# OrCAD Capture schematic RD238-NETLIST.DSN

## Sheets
1 16: size A3
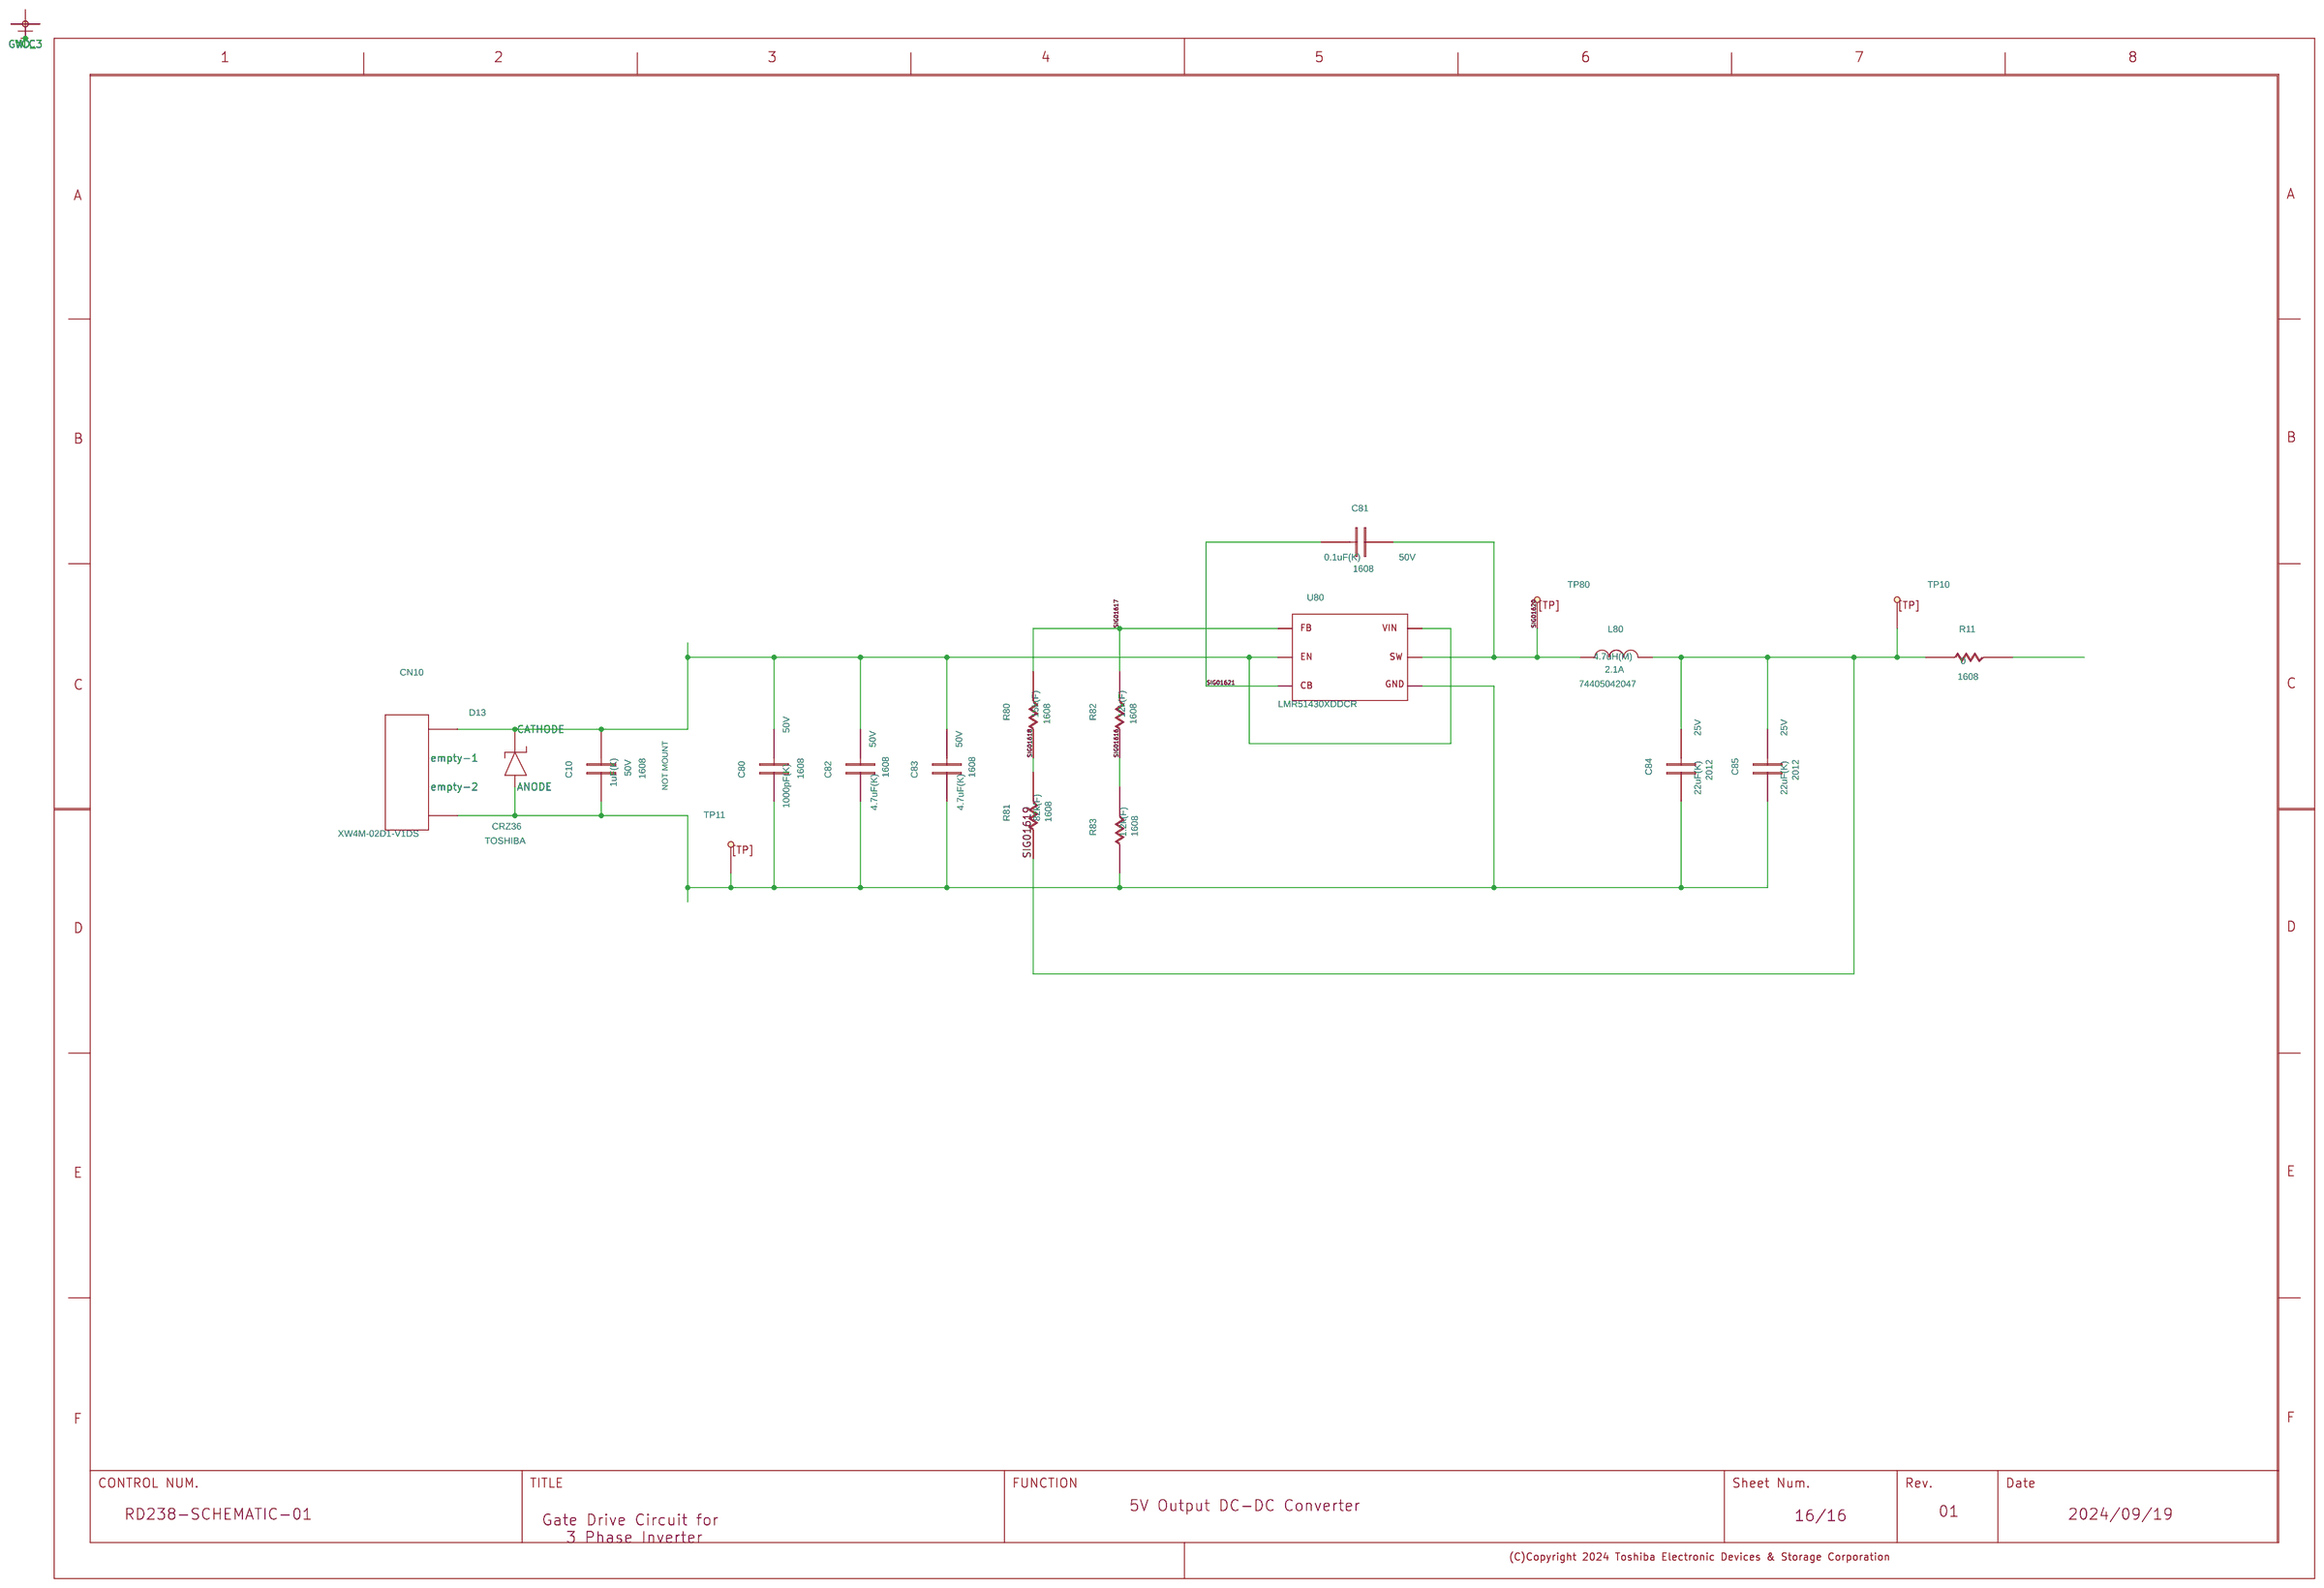
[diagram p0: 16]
2 15: size A3
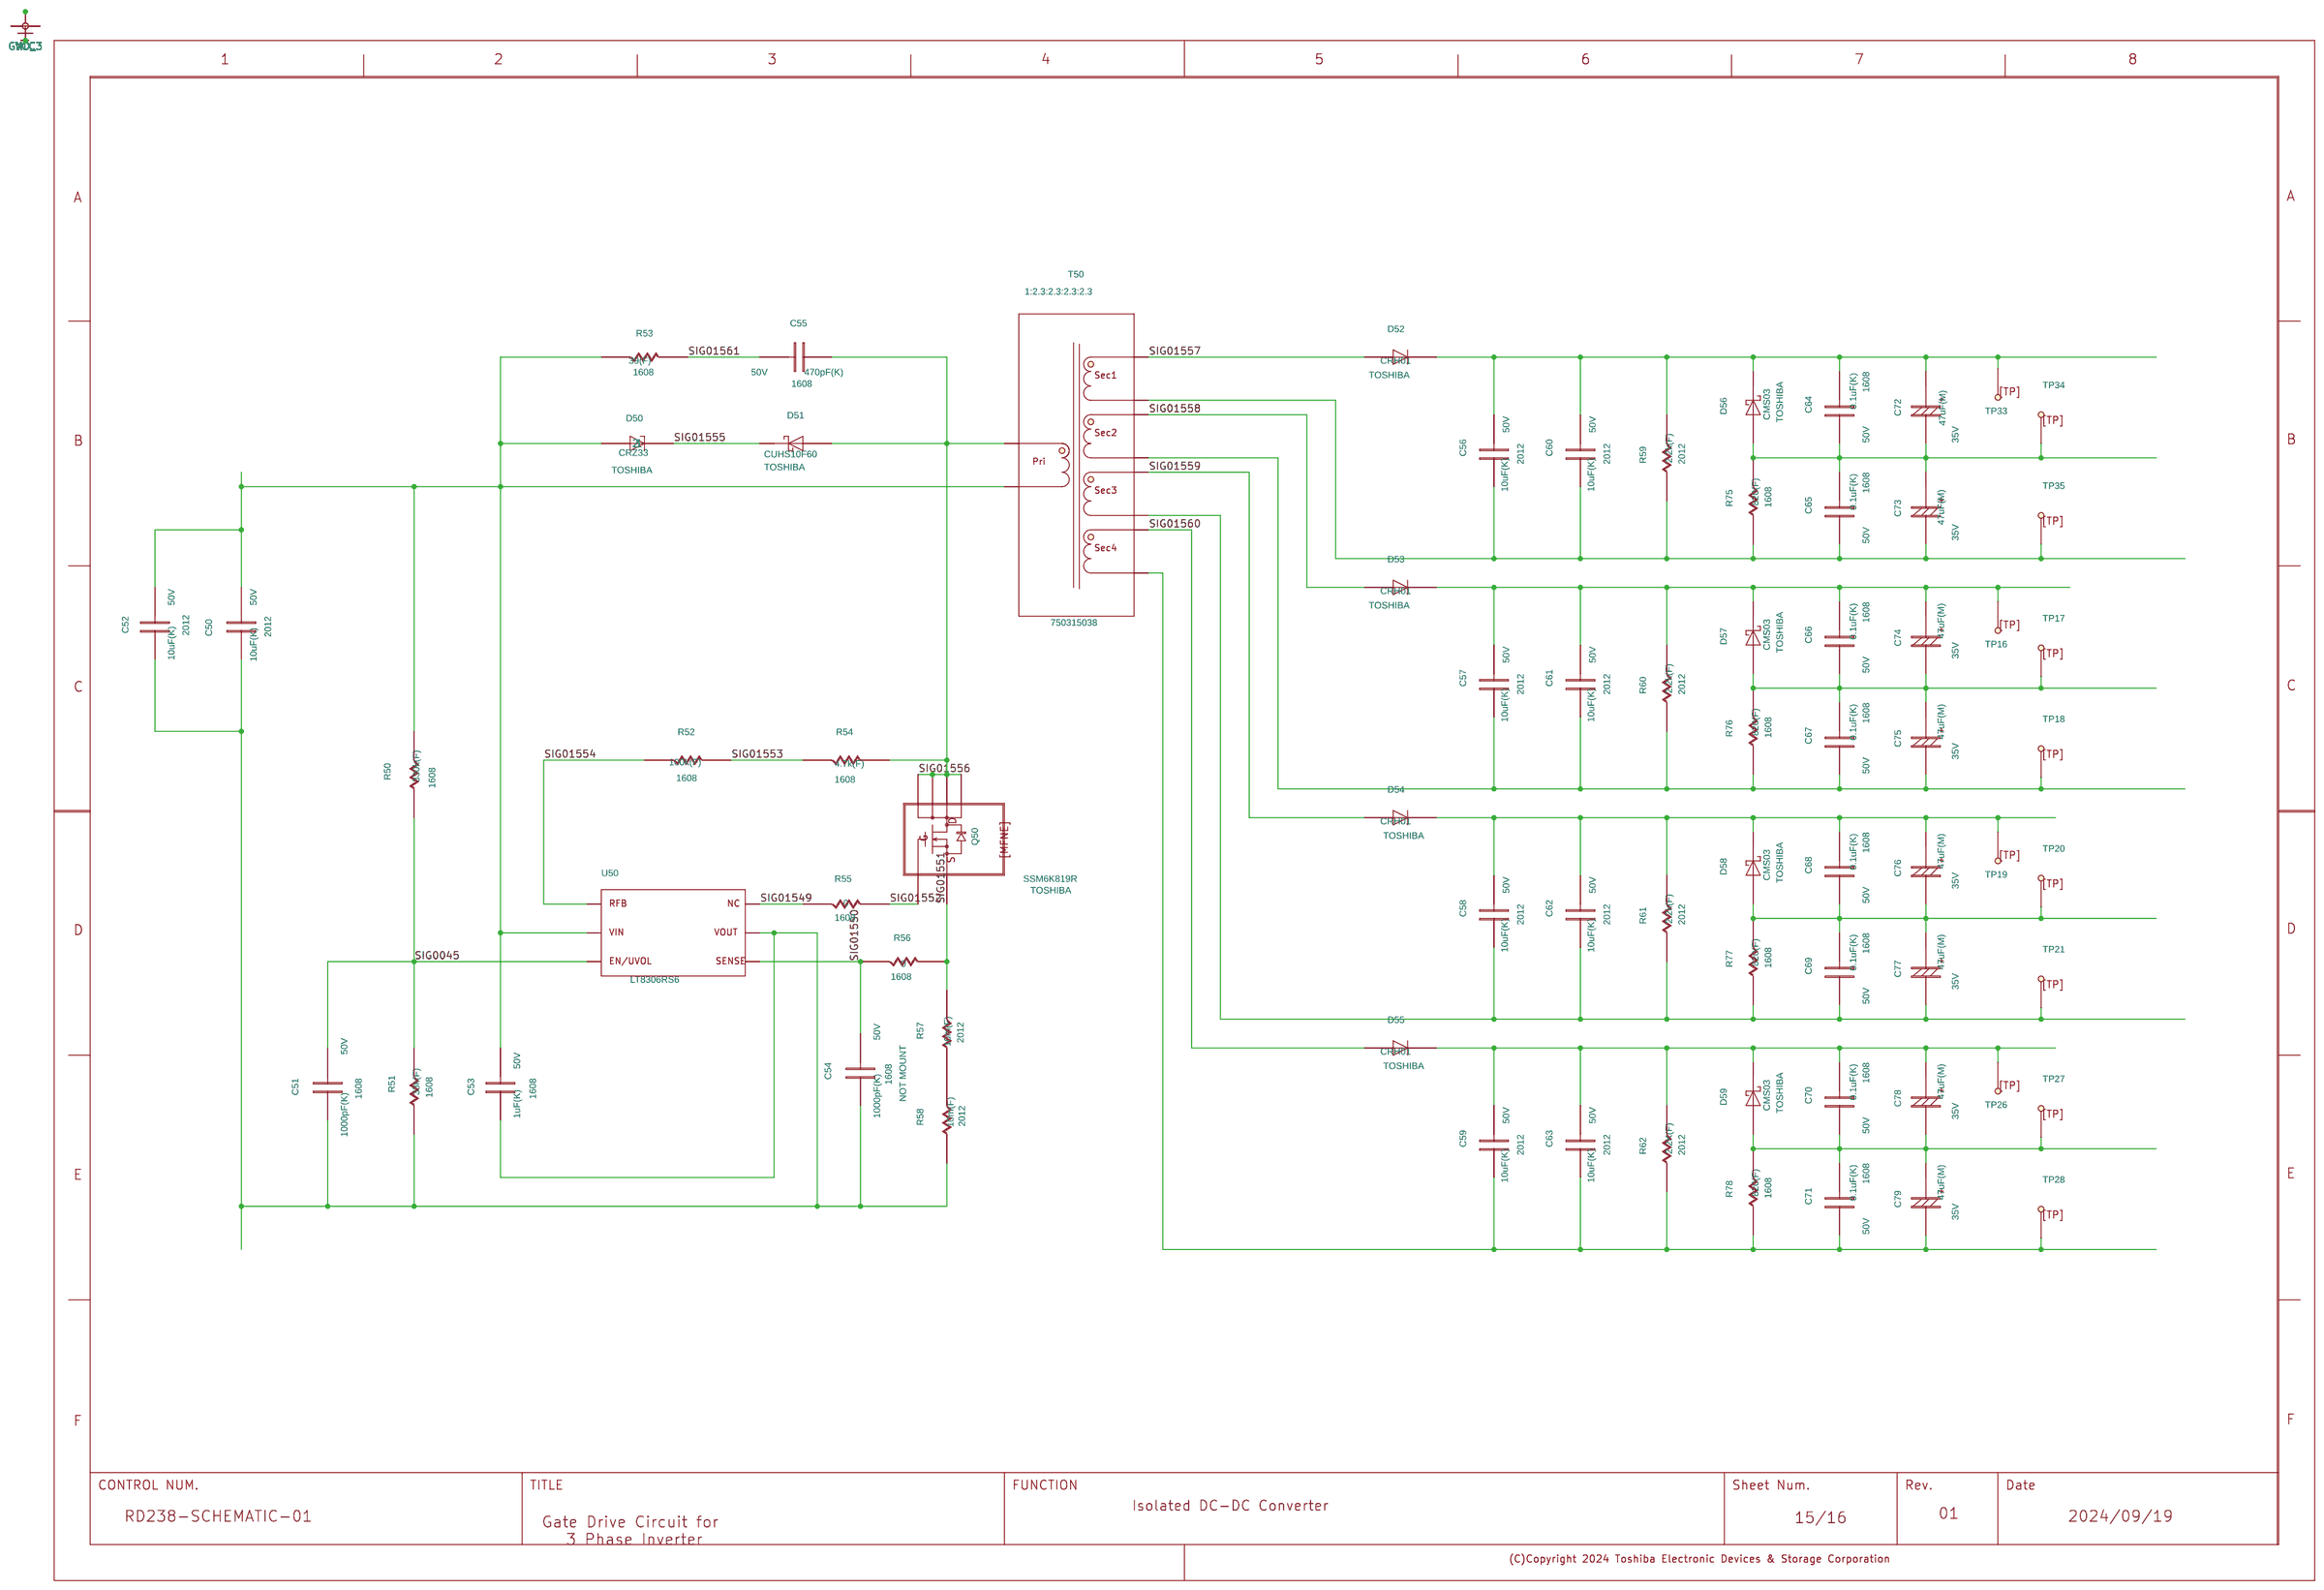
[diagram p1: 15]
3 14: size A3
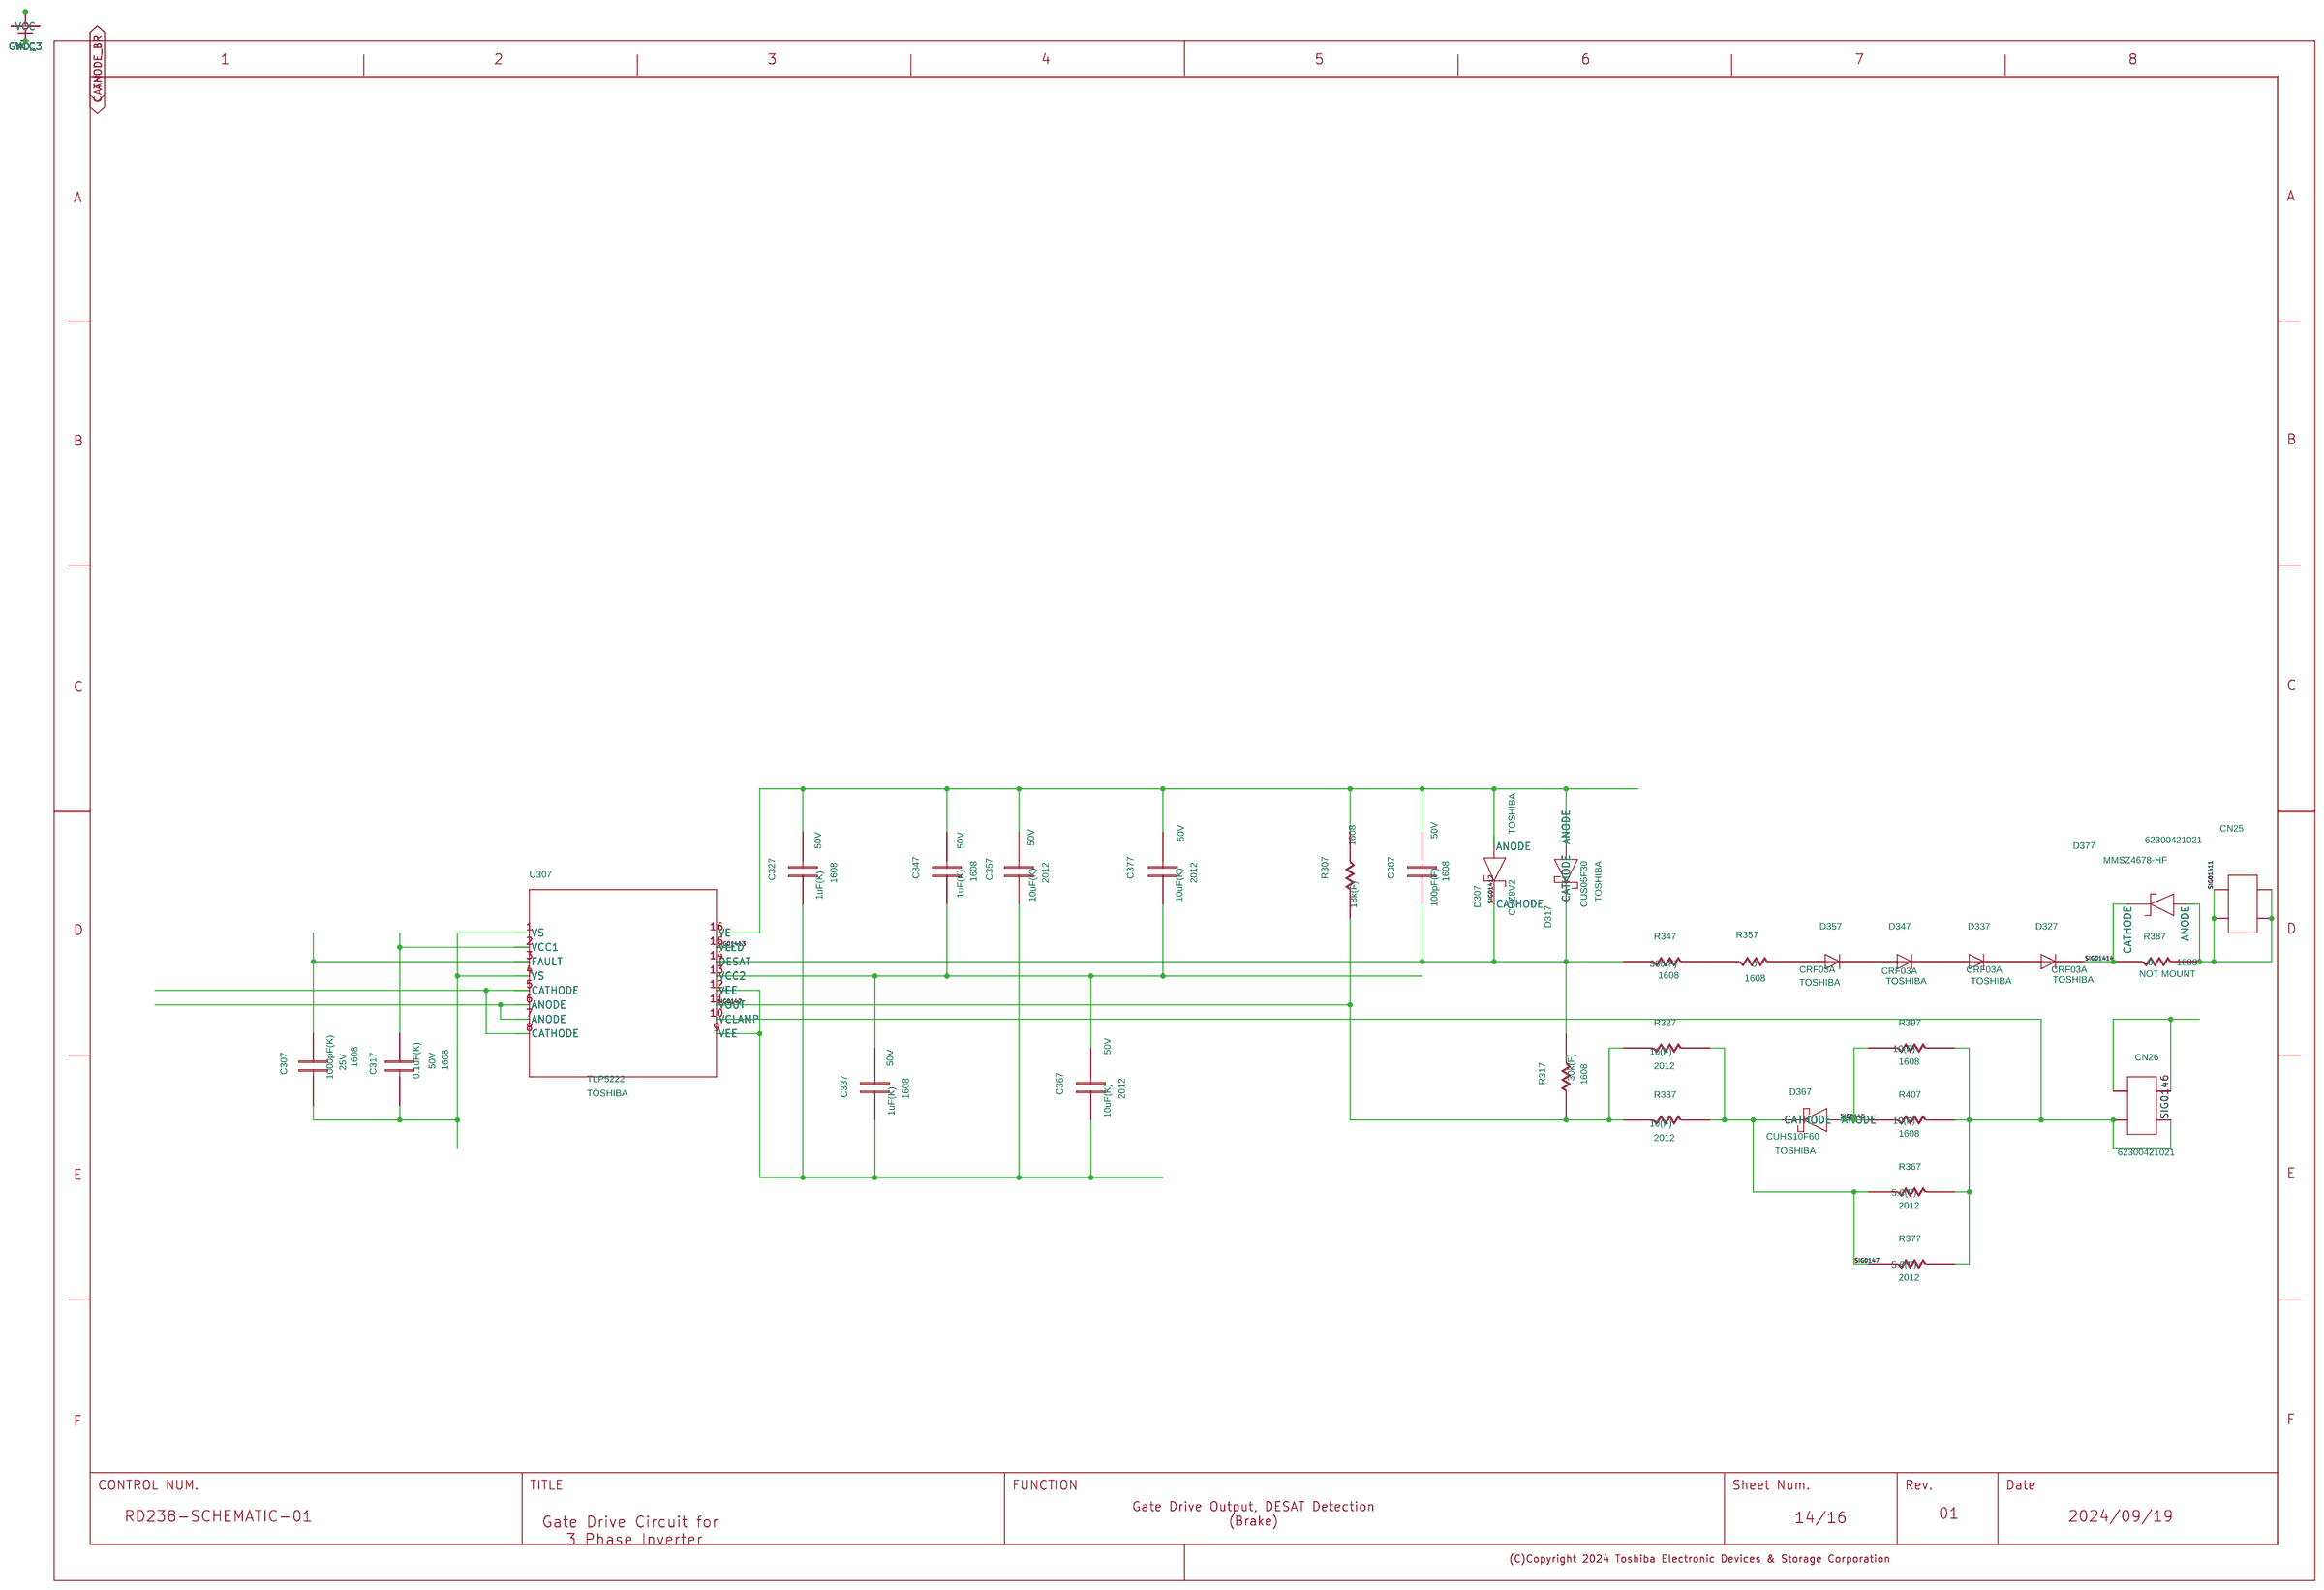
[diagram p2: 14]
4 13: size A3
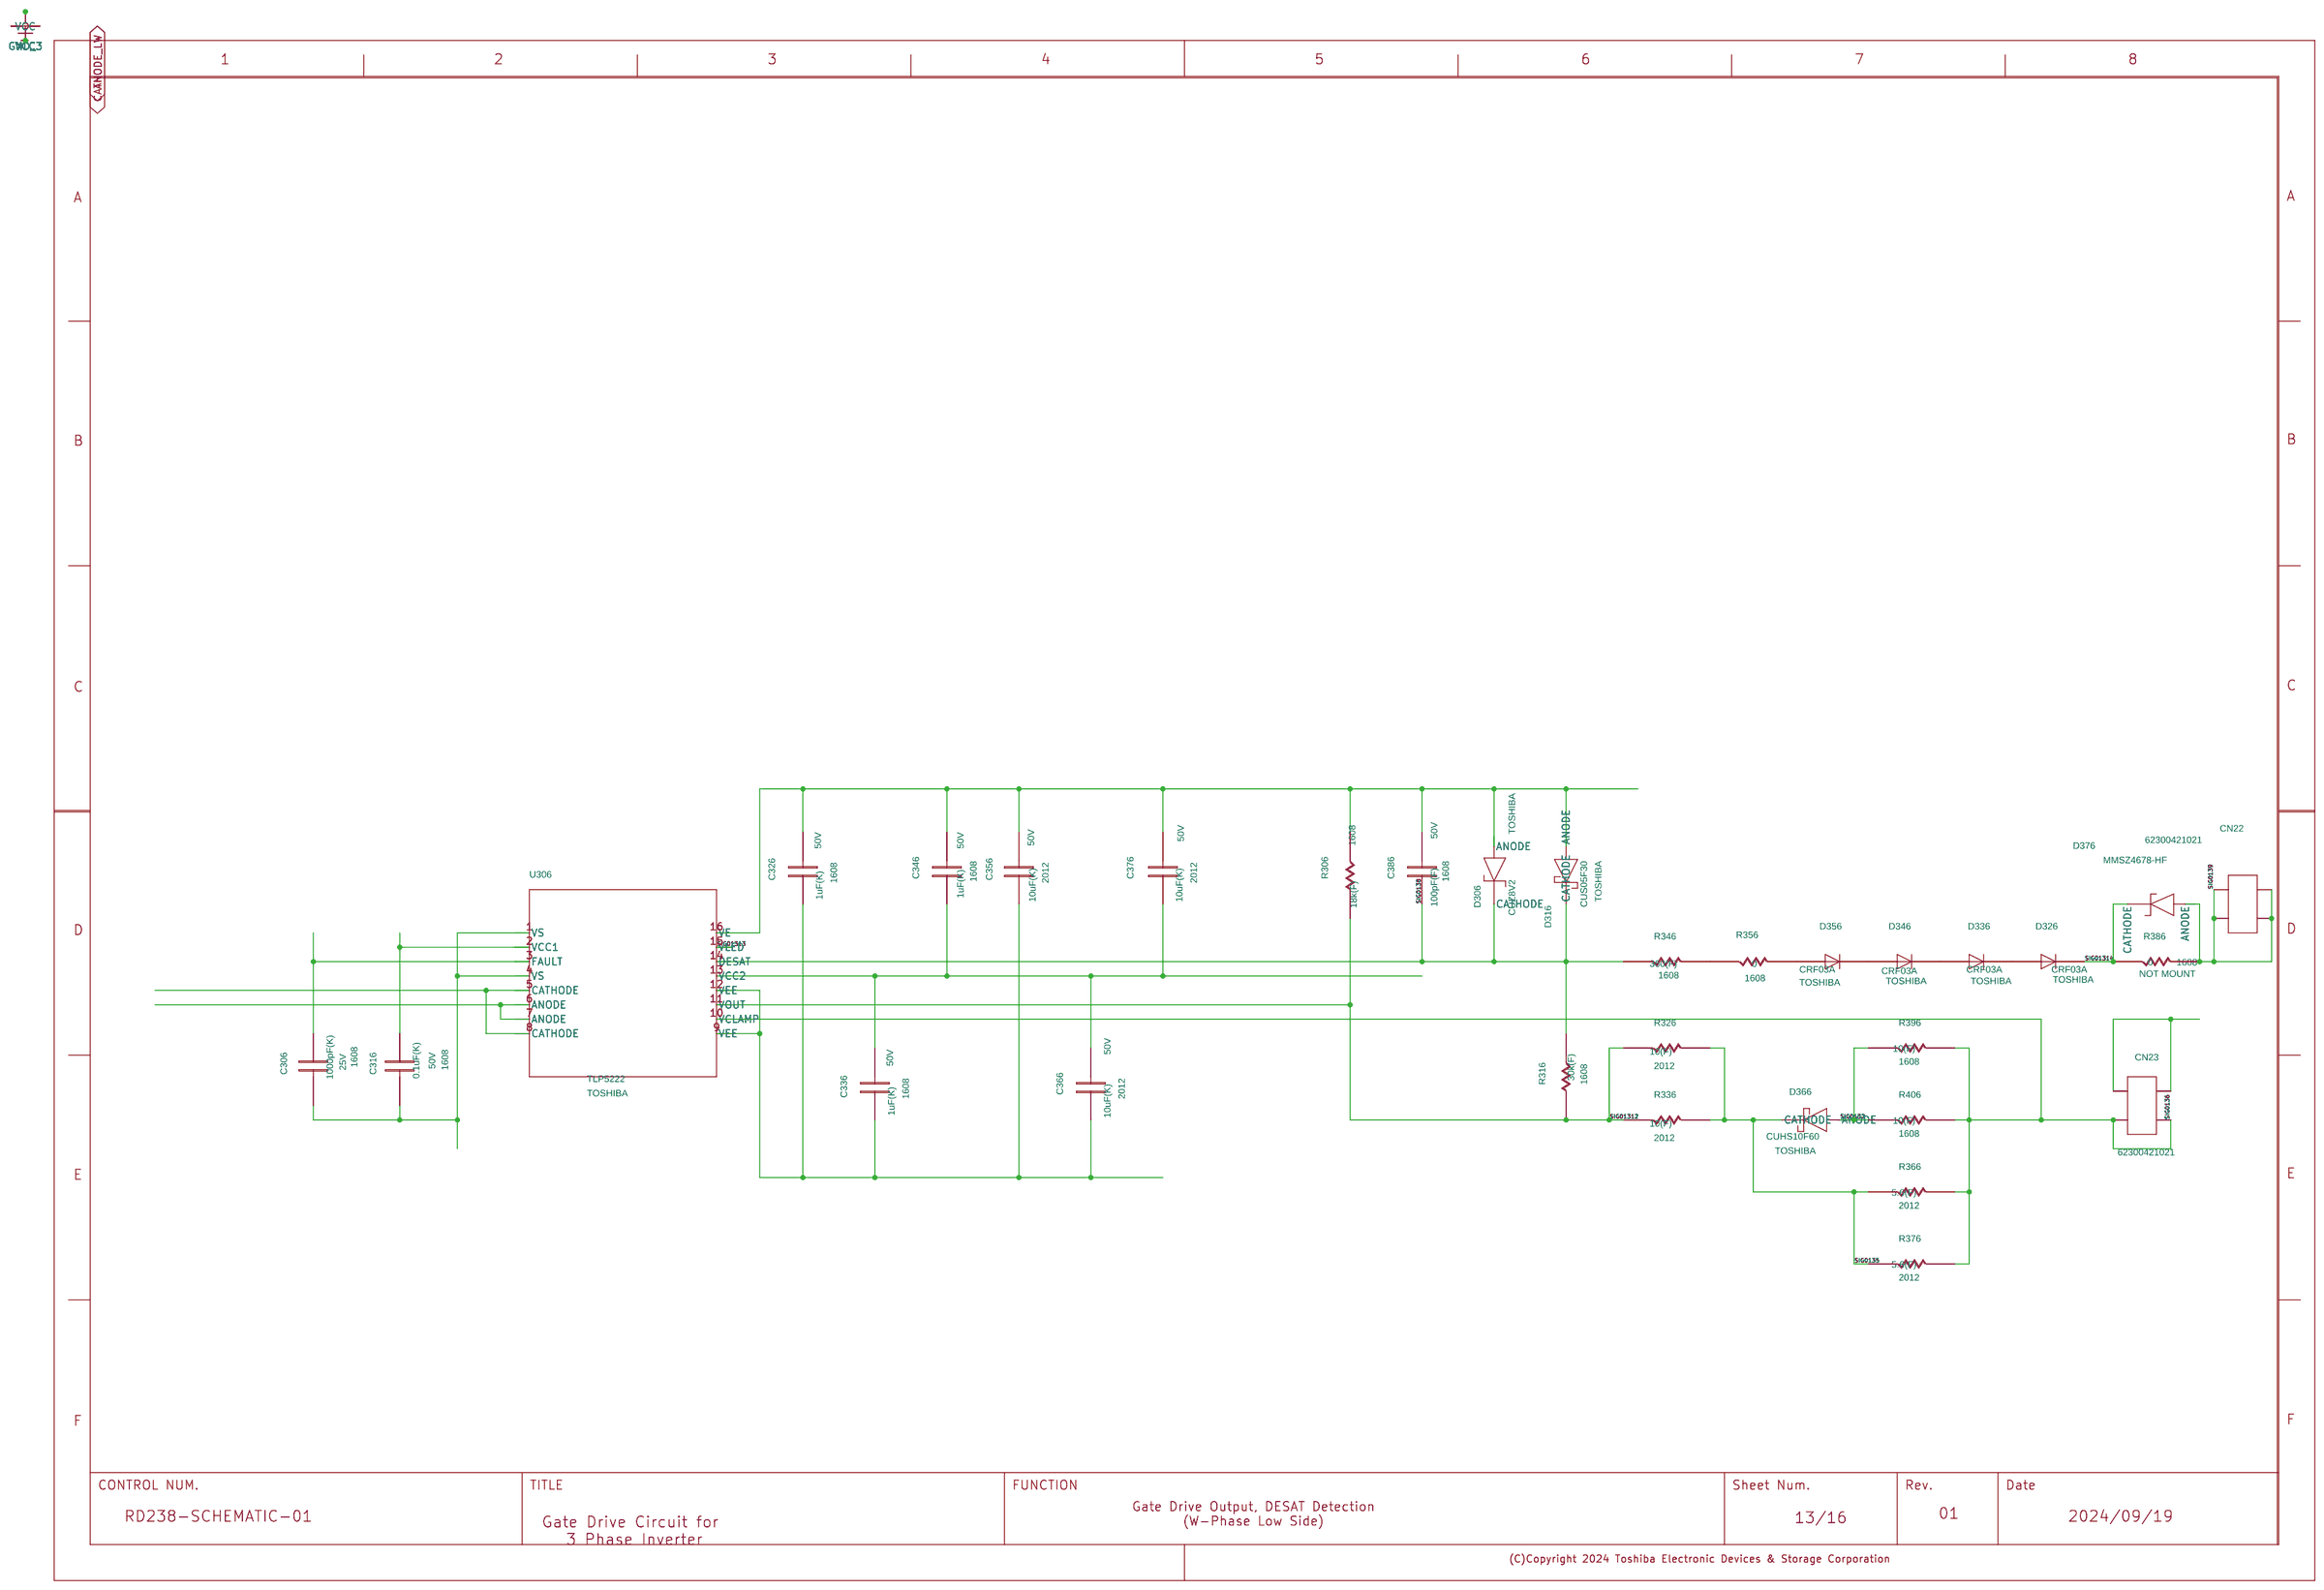
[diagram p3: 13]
5 12: size A3
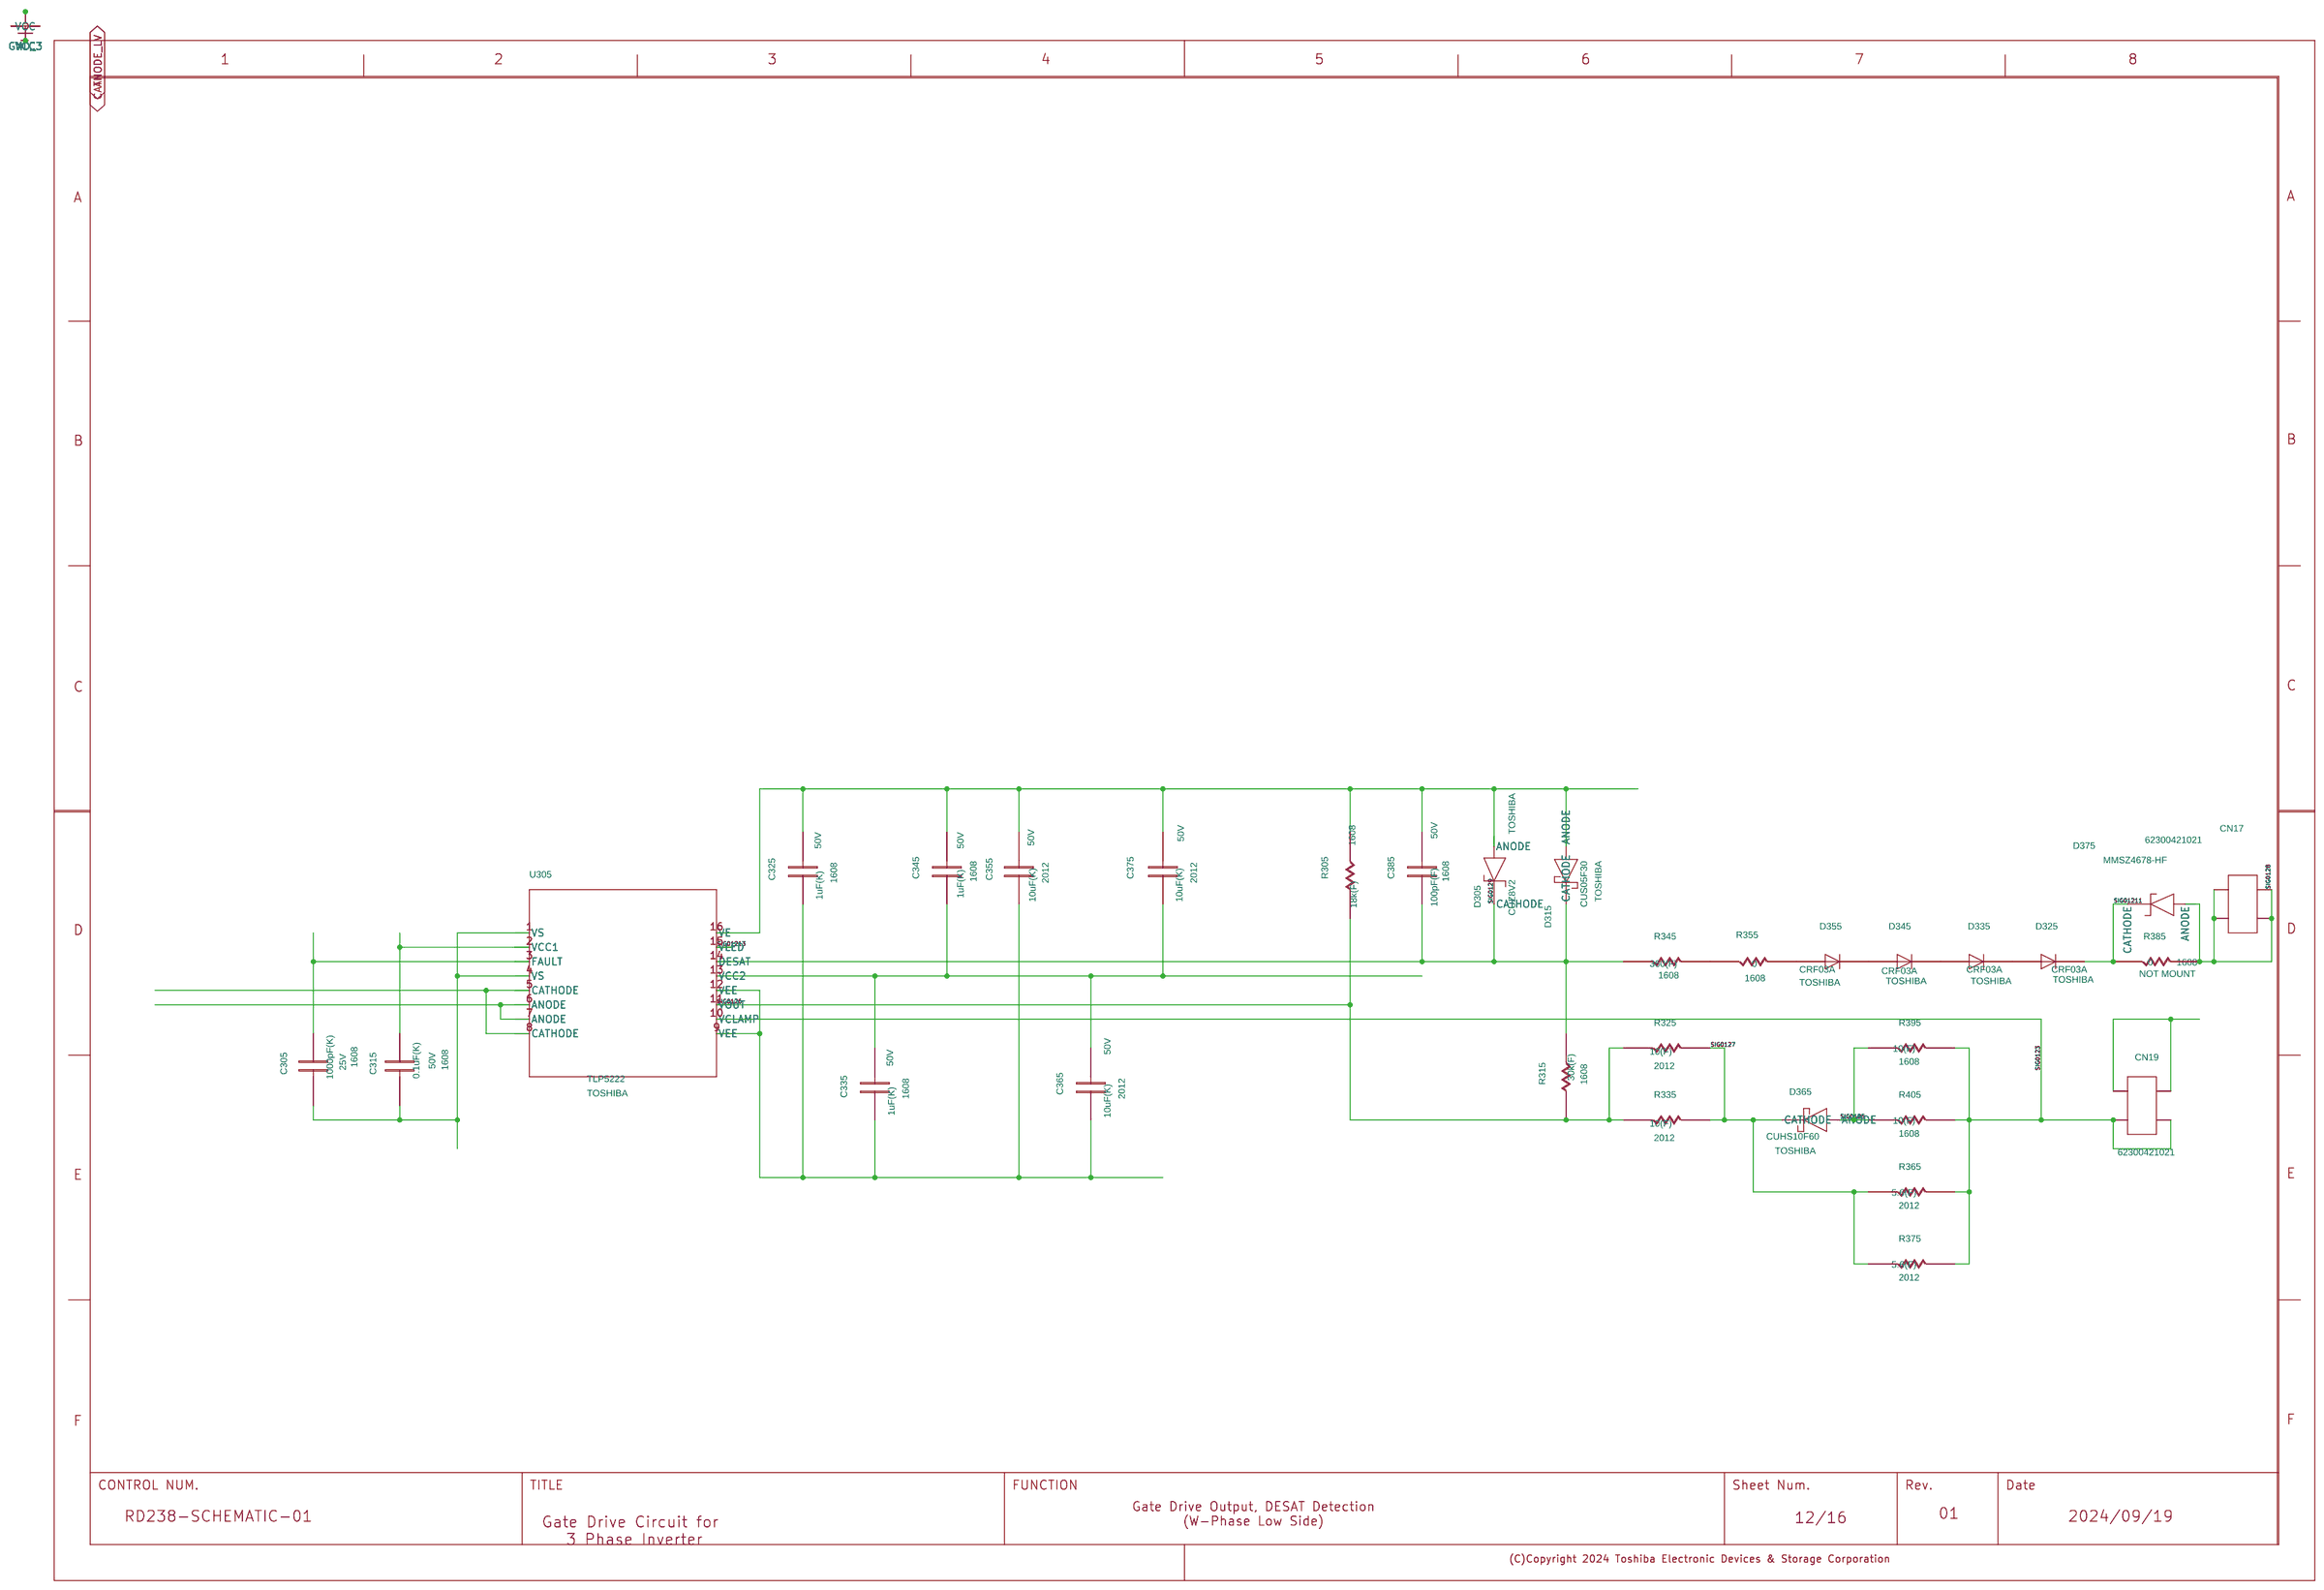
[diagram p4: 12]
6 11: size A3
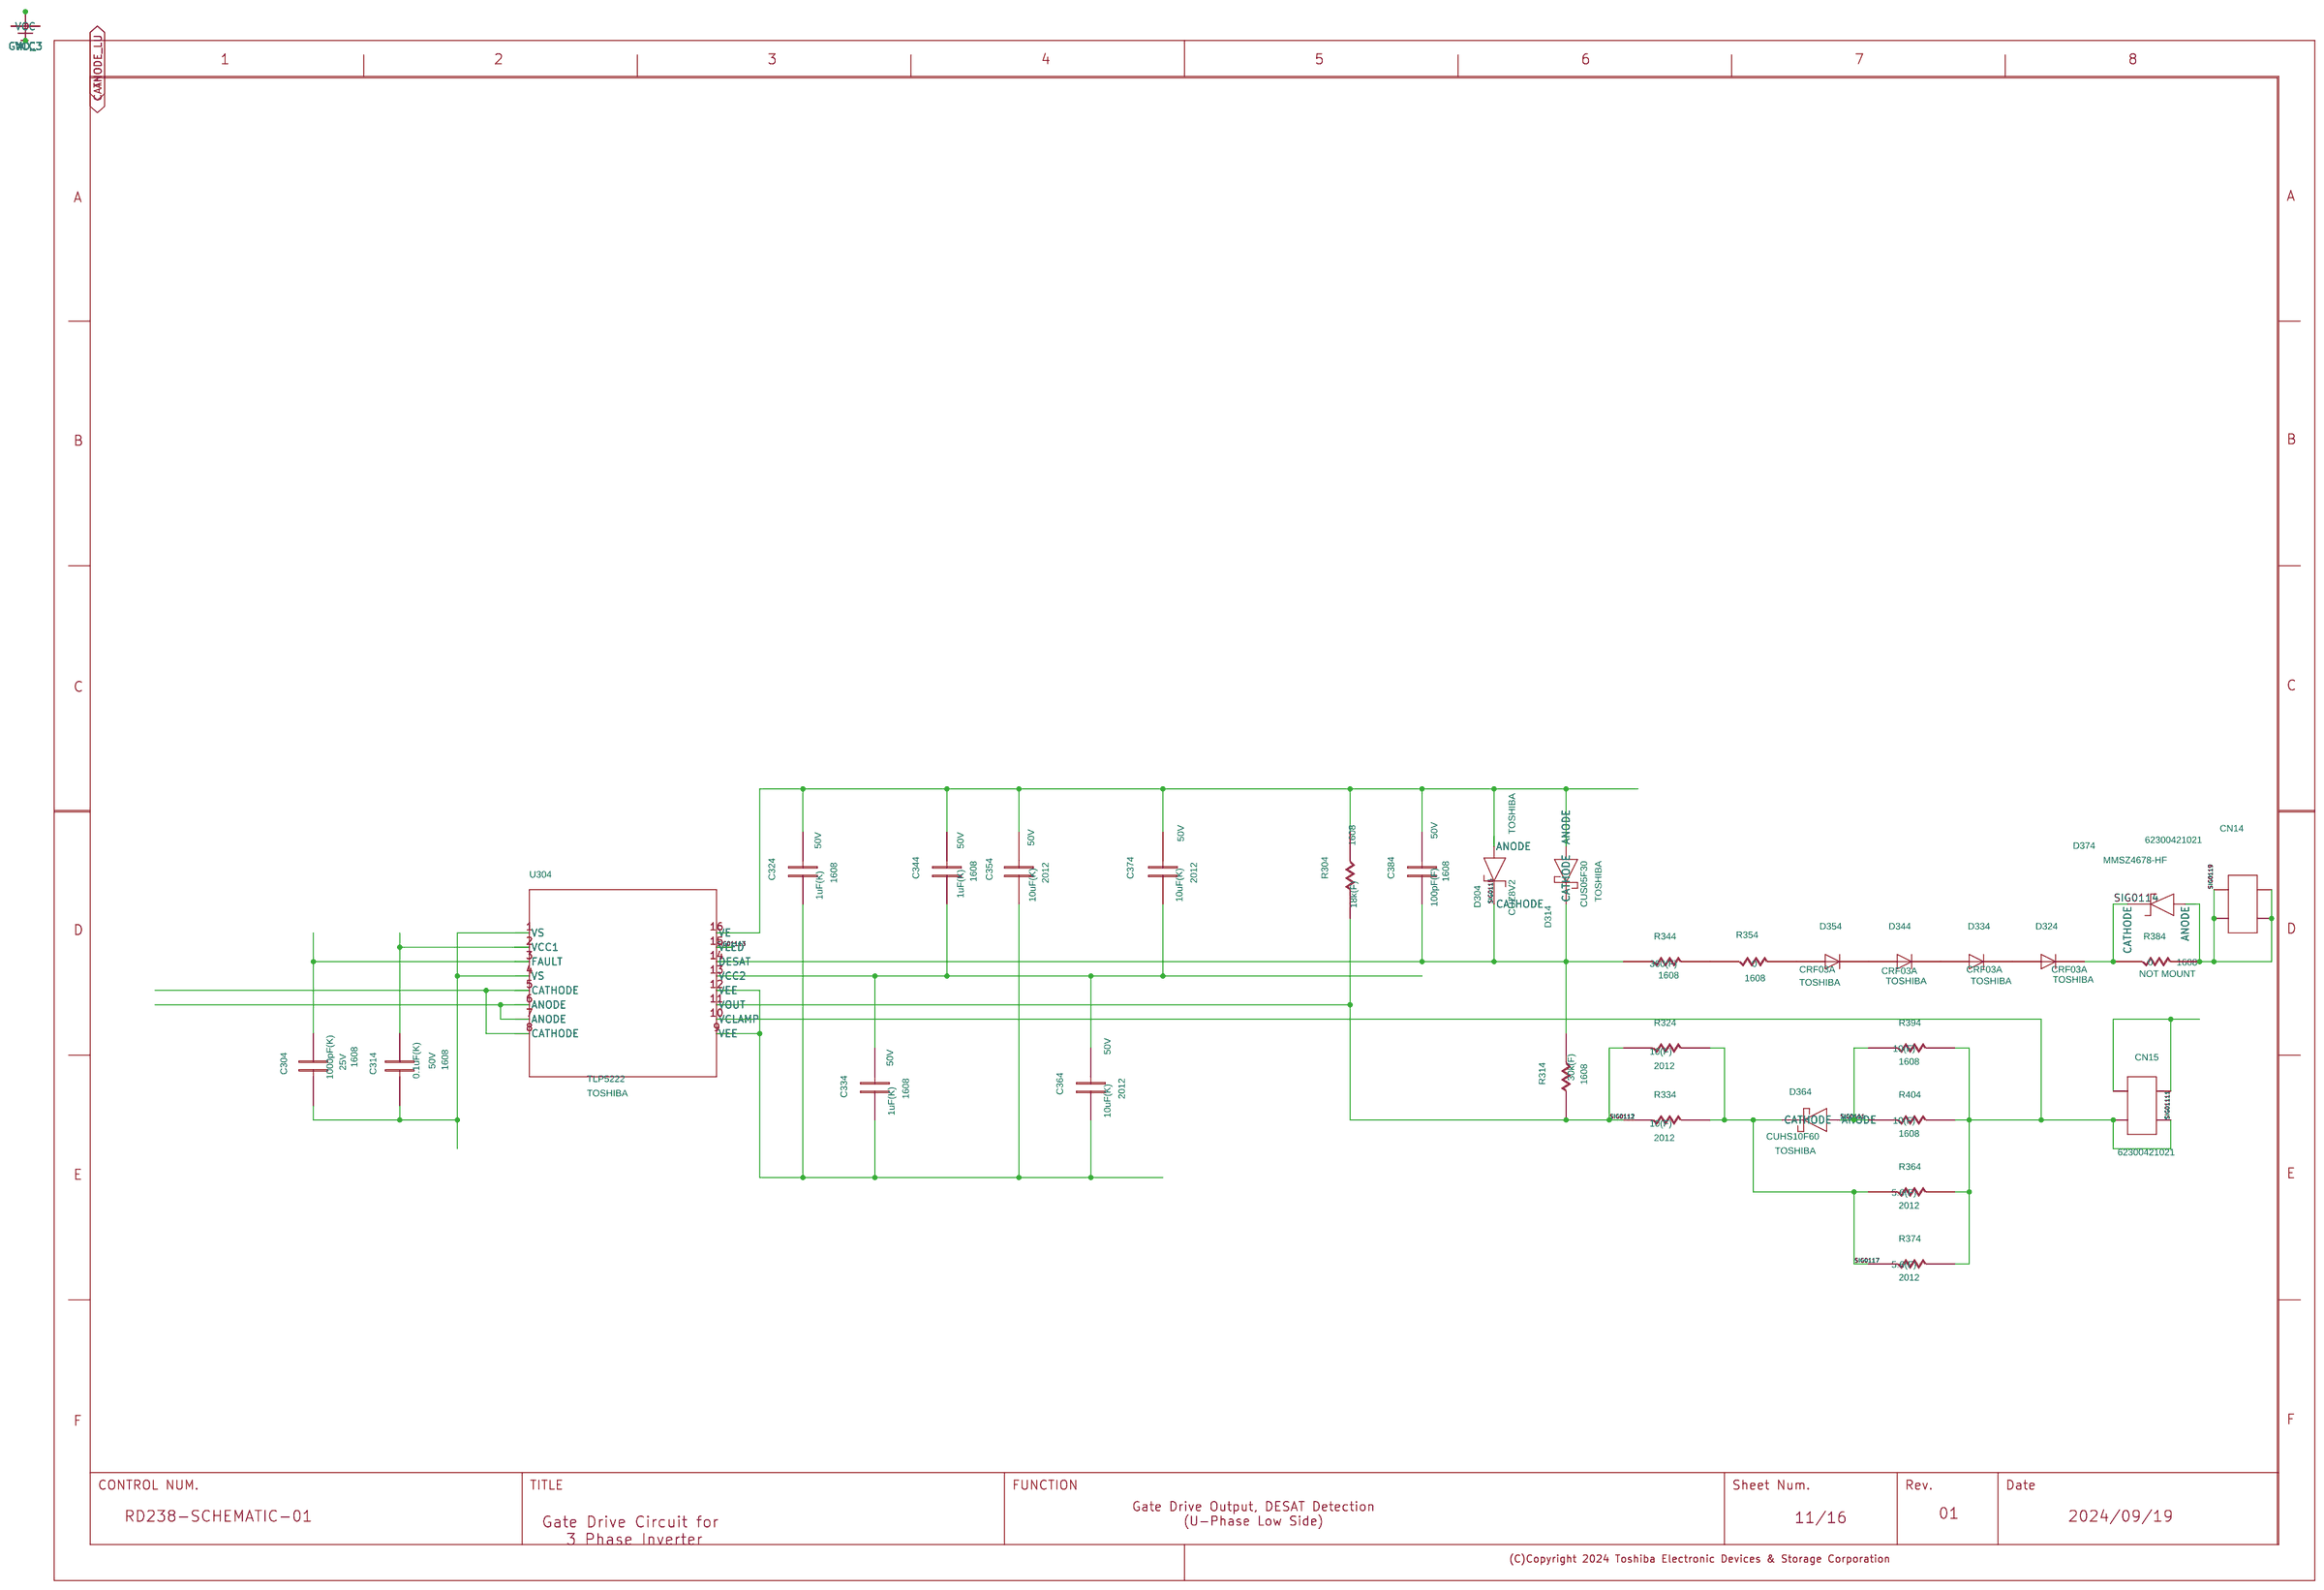
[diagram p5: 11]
7 10: size A3
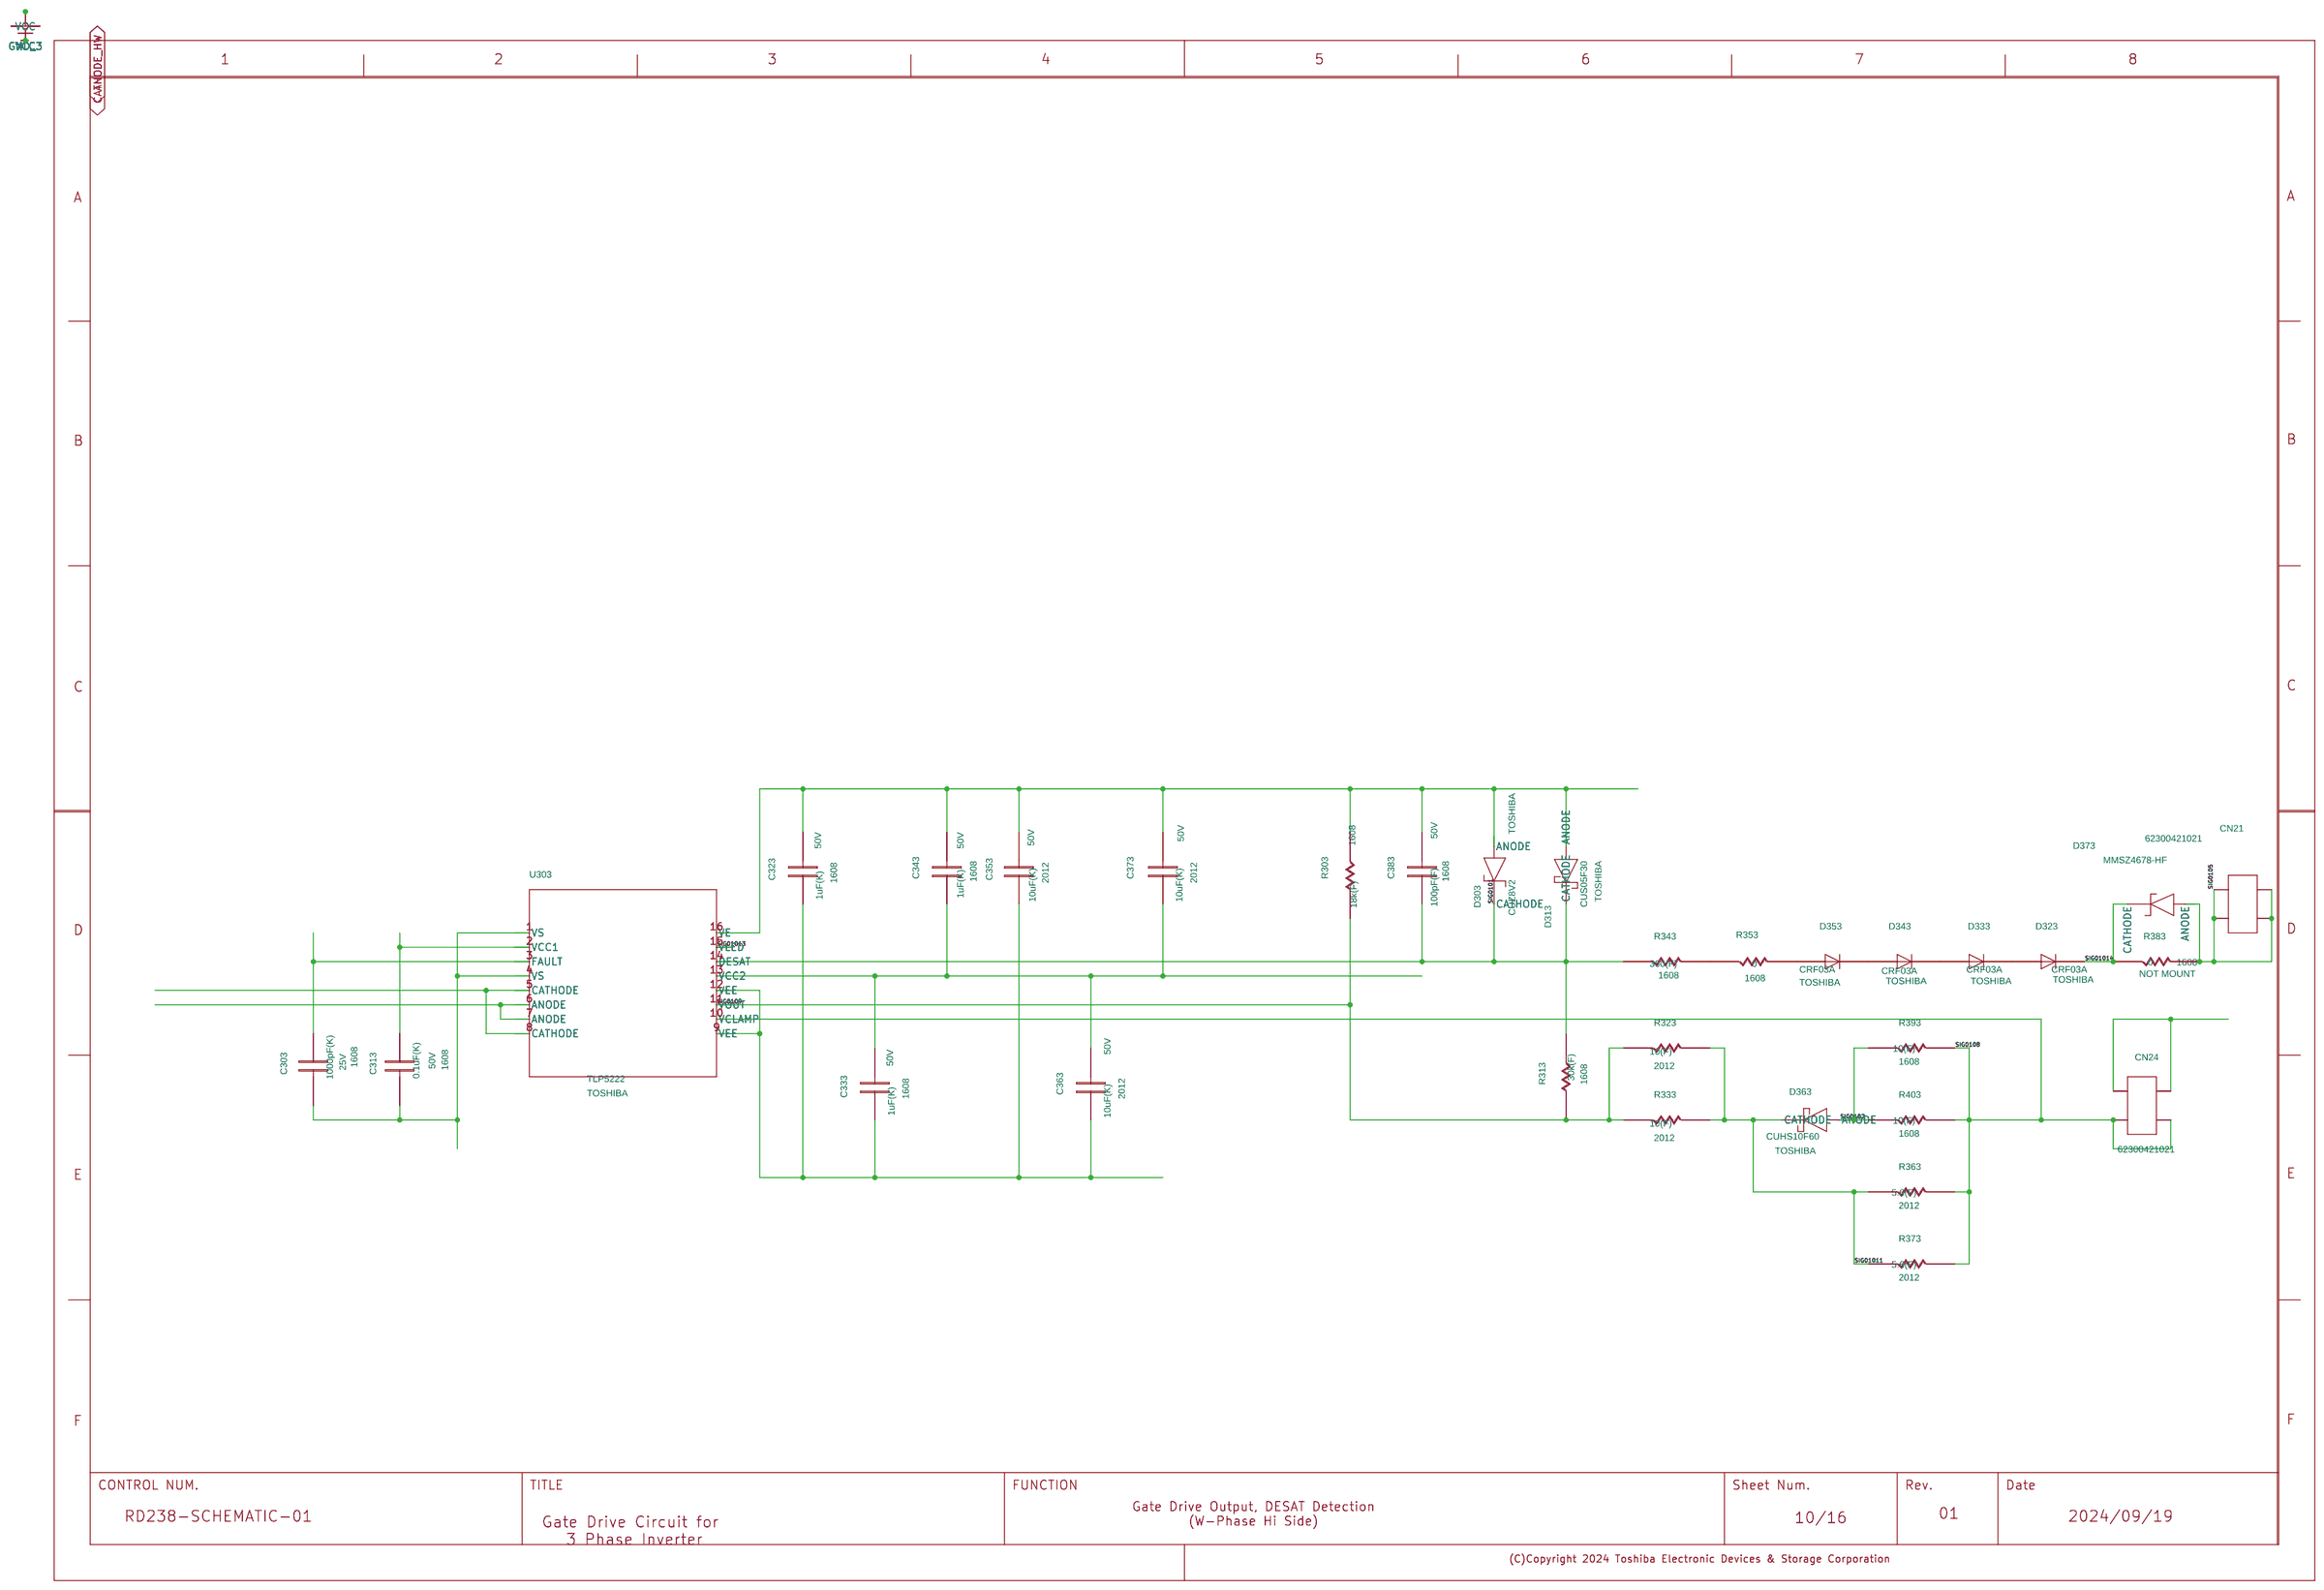
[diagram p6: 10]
8 9: size A3
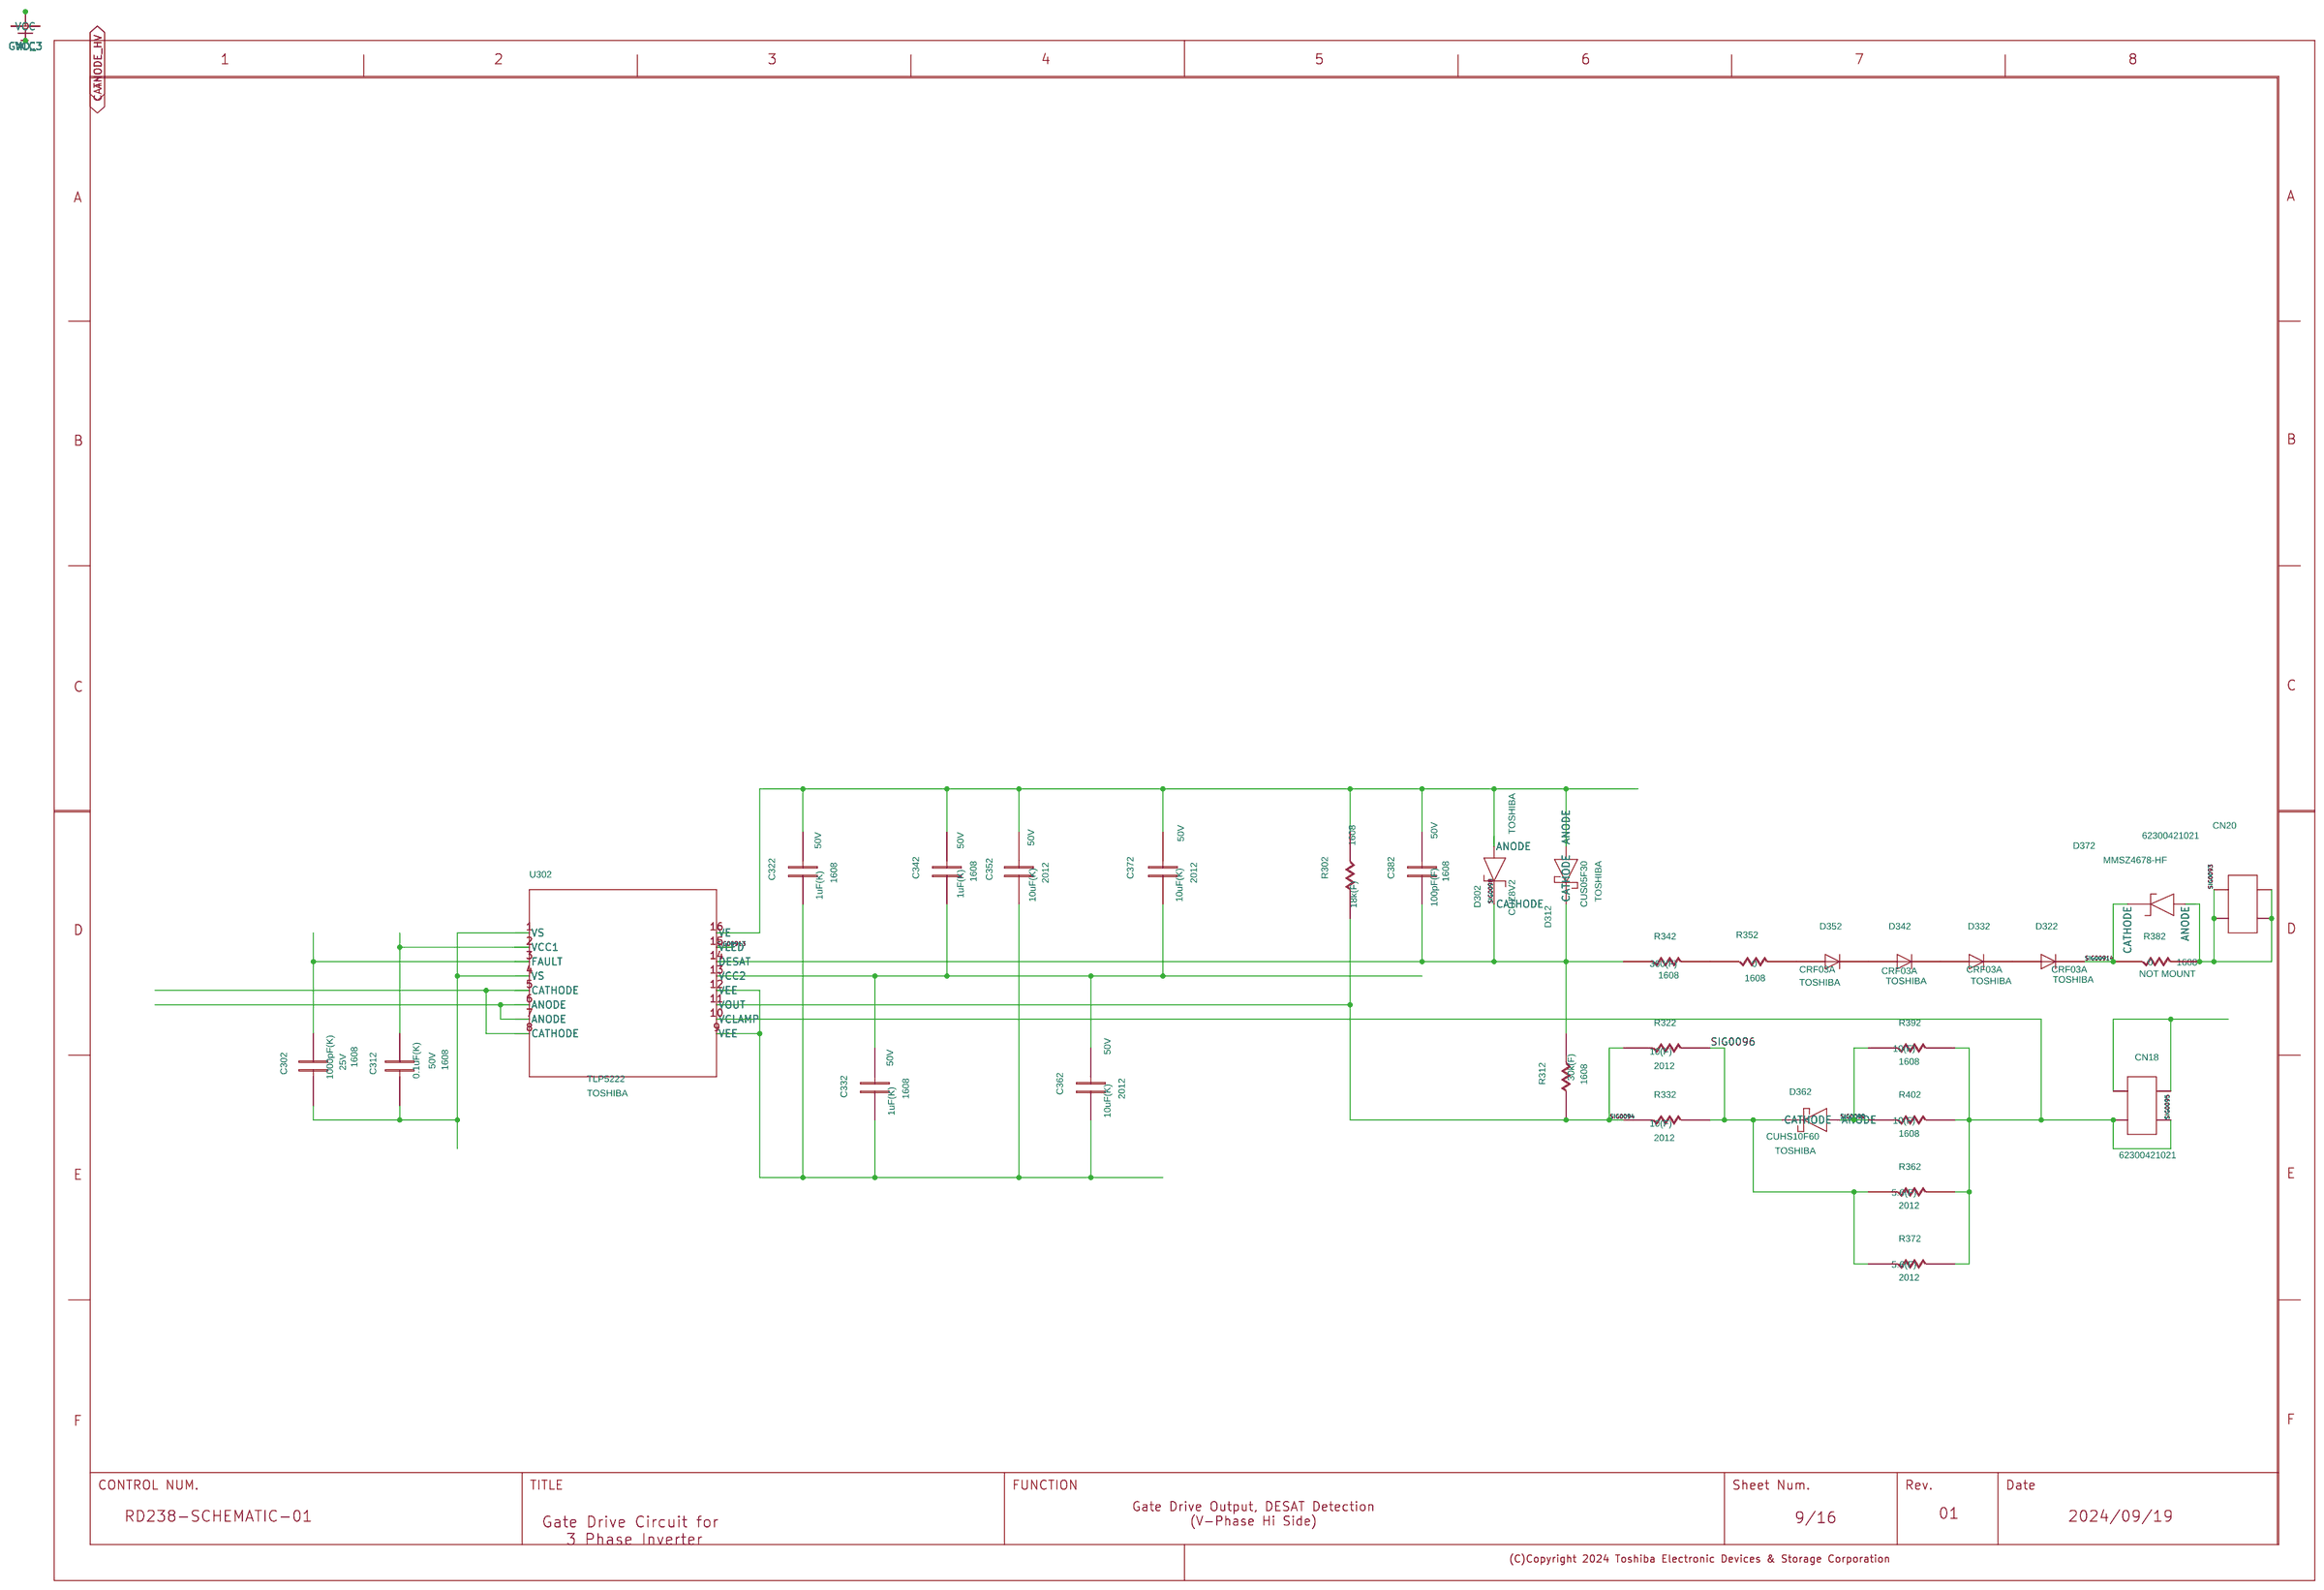
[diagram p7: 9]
9 8: size A3
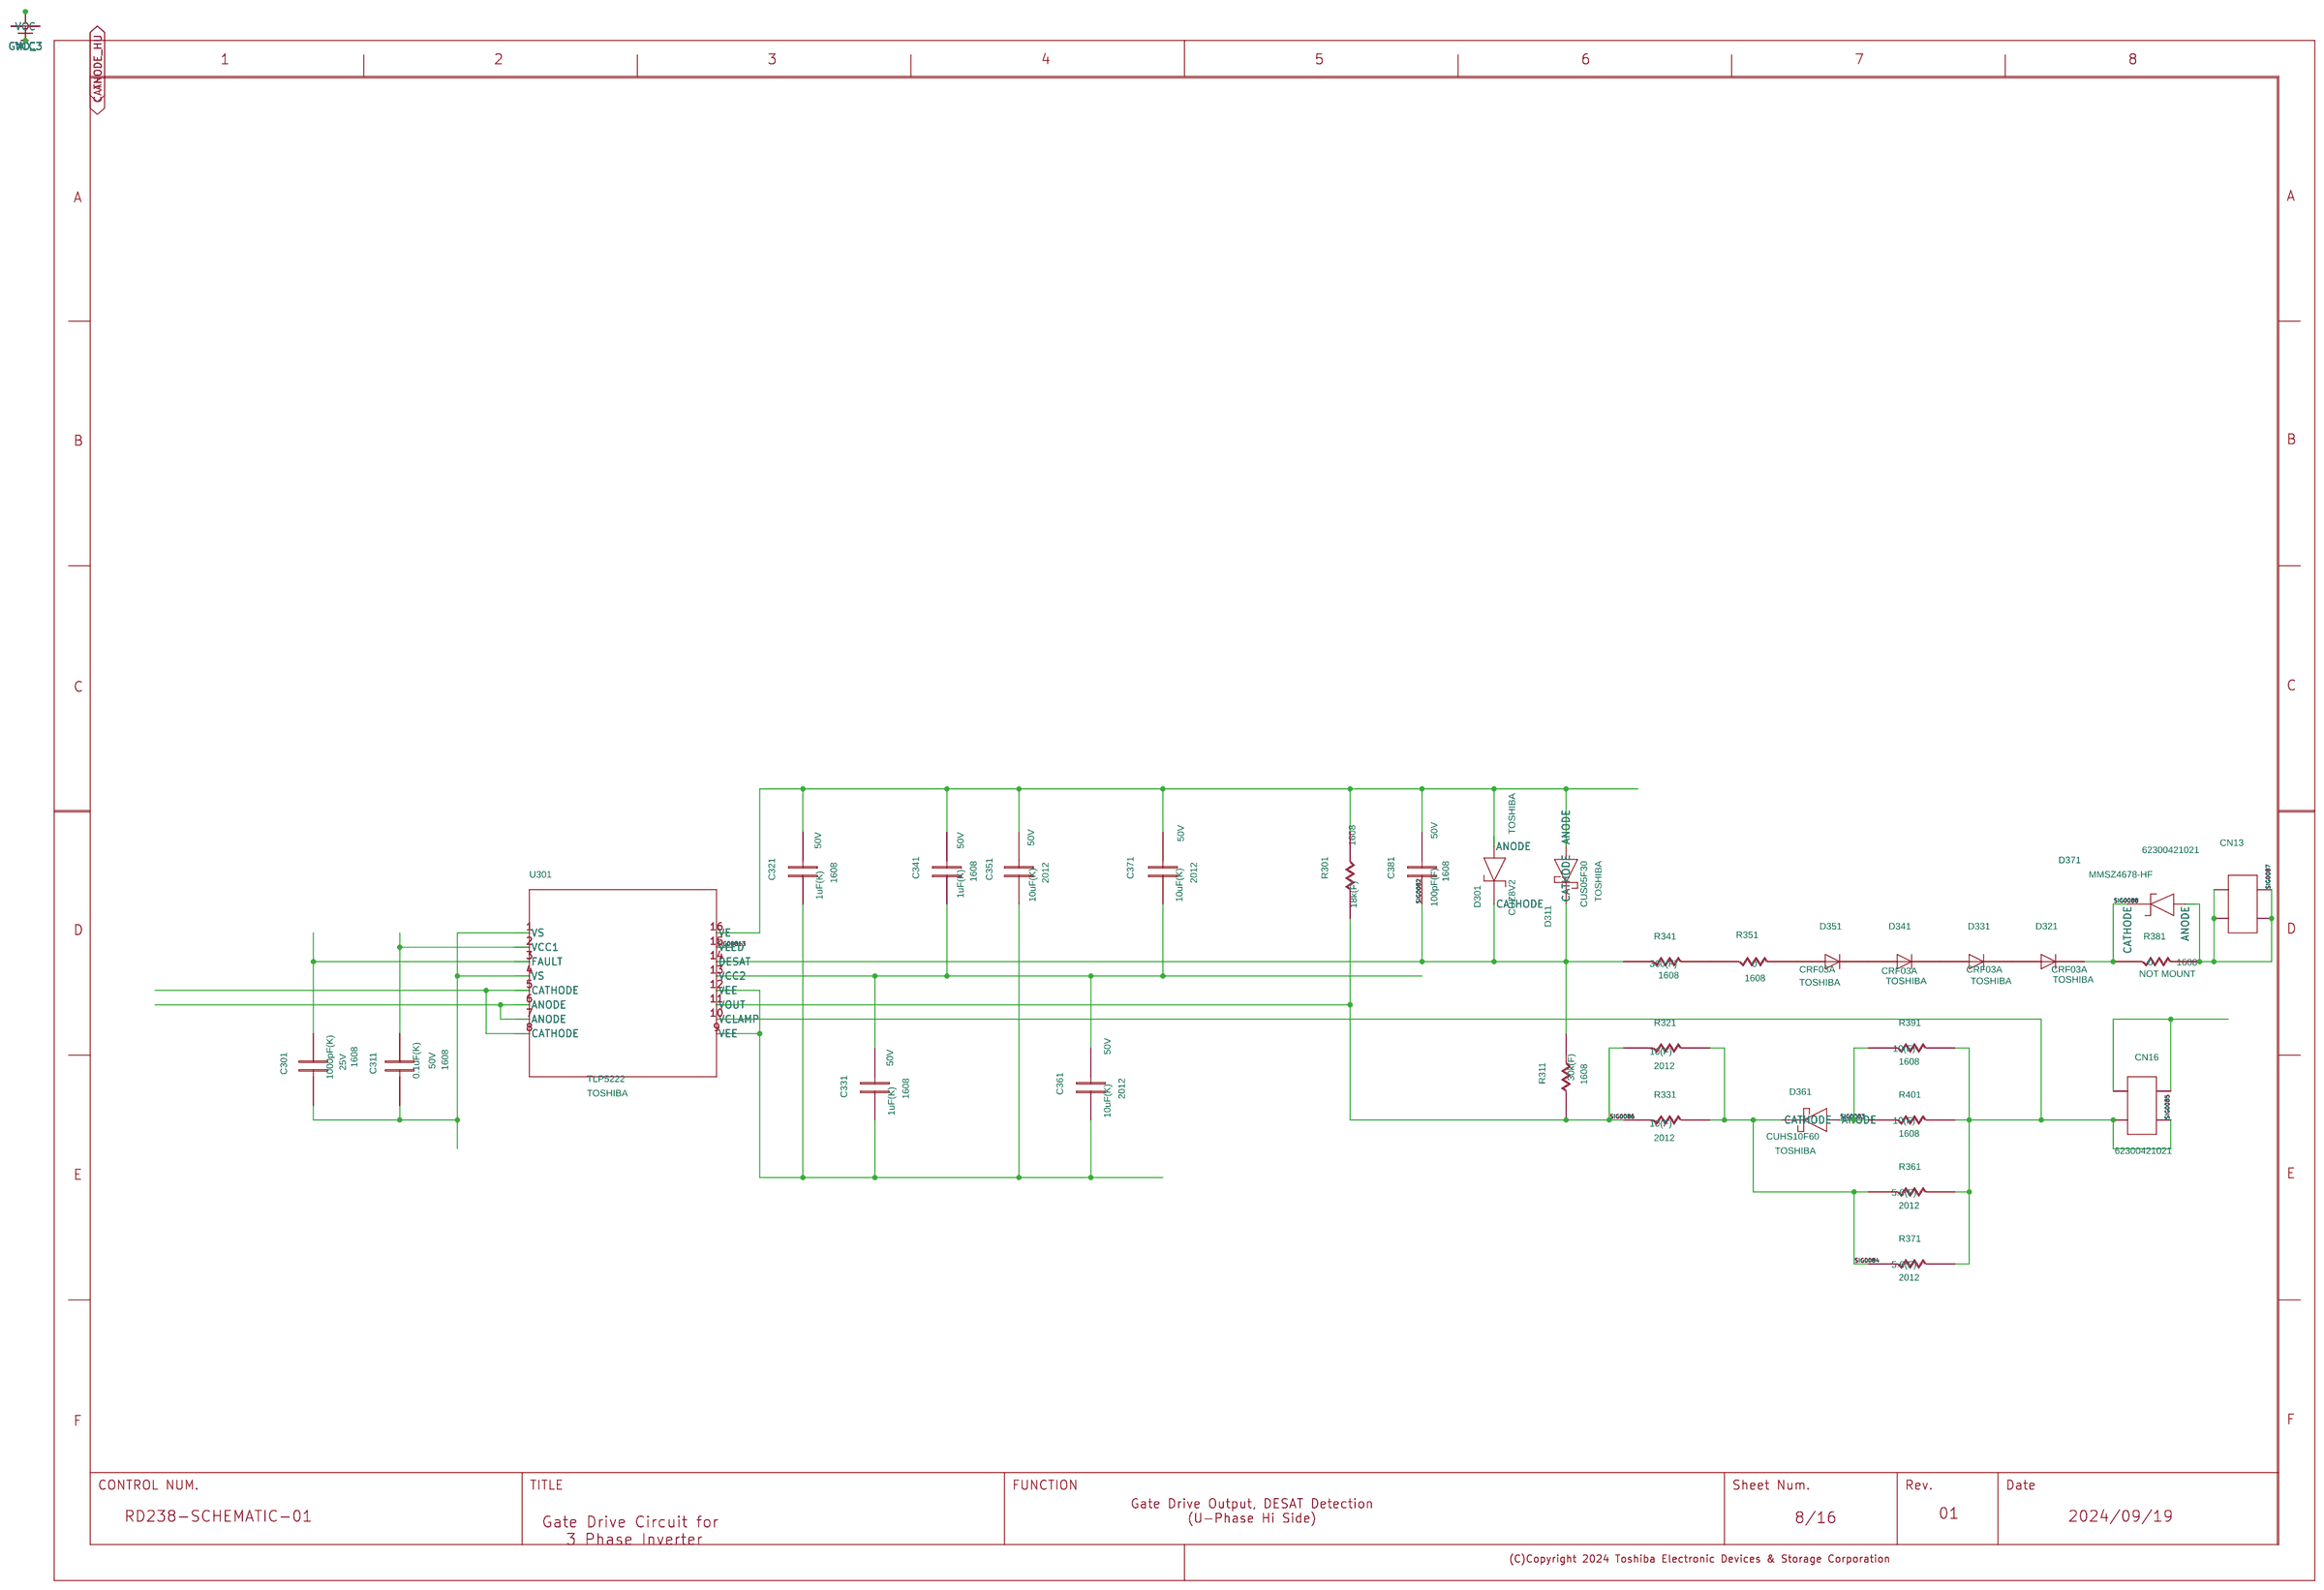
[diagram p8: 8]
10 7: size A3
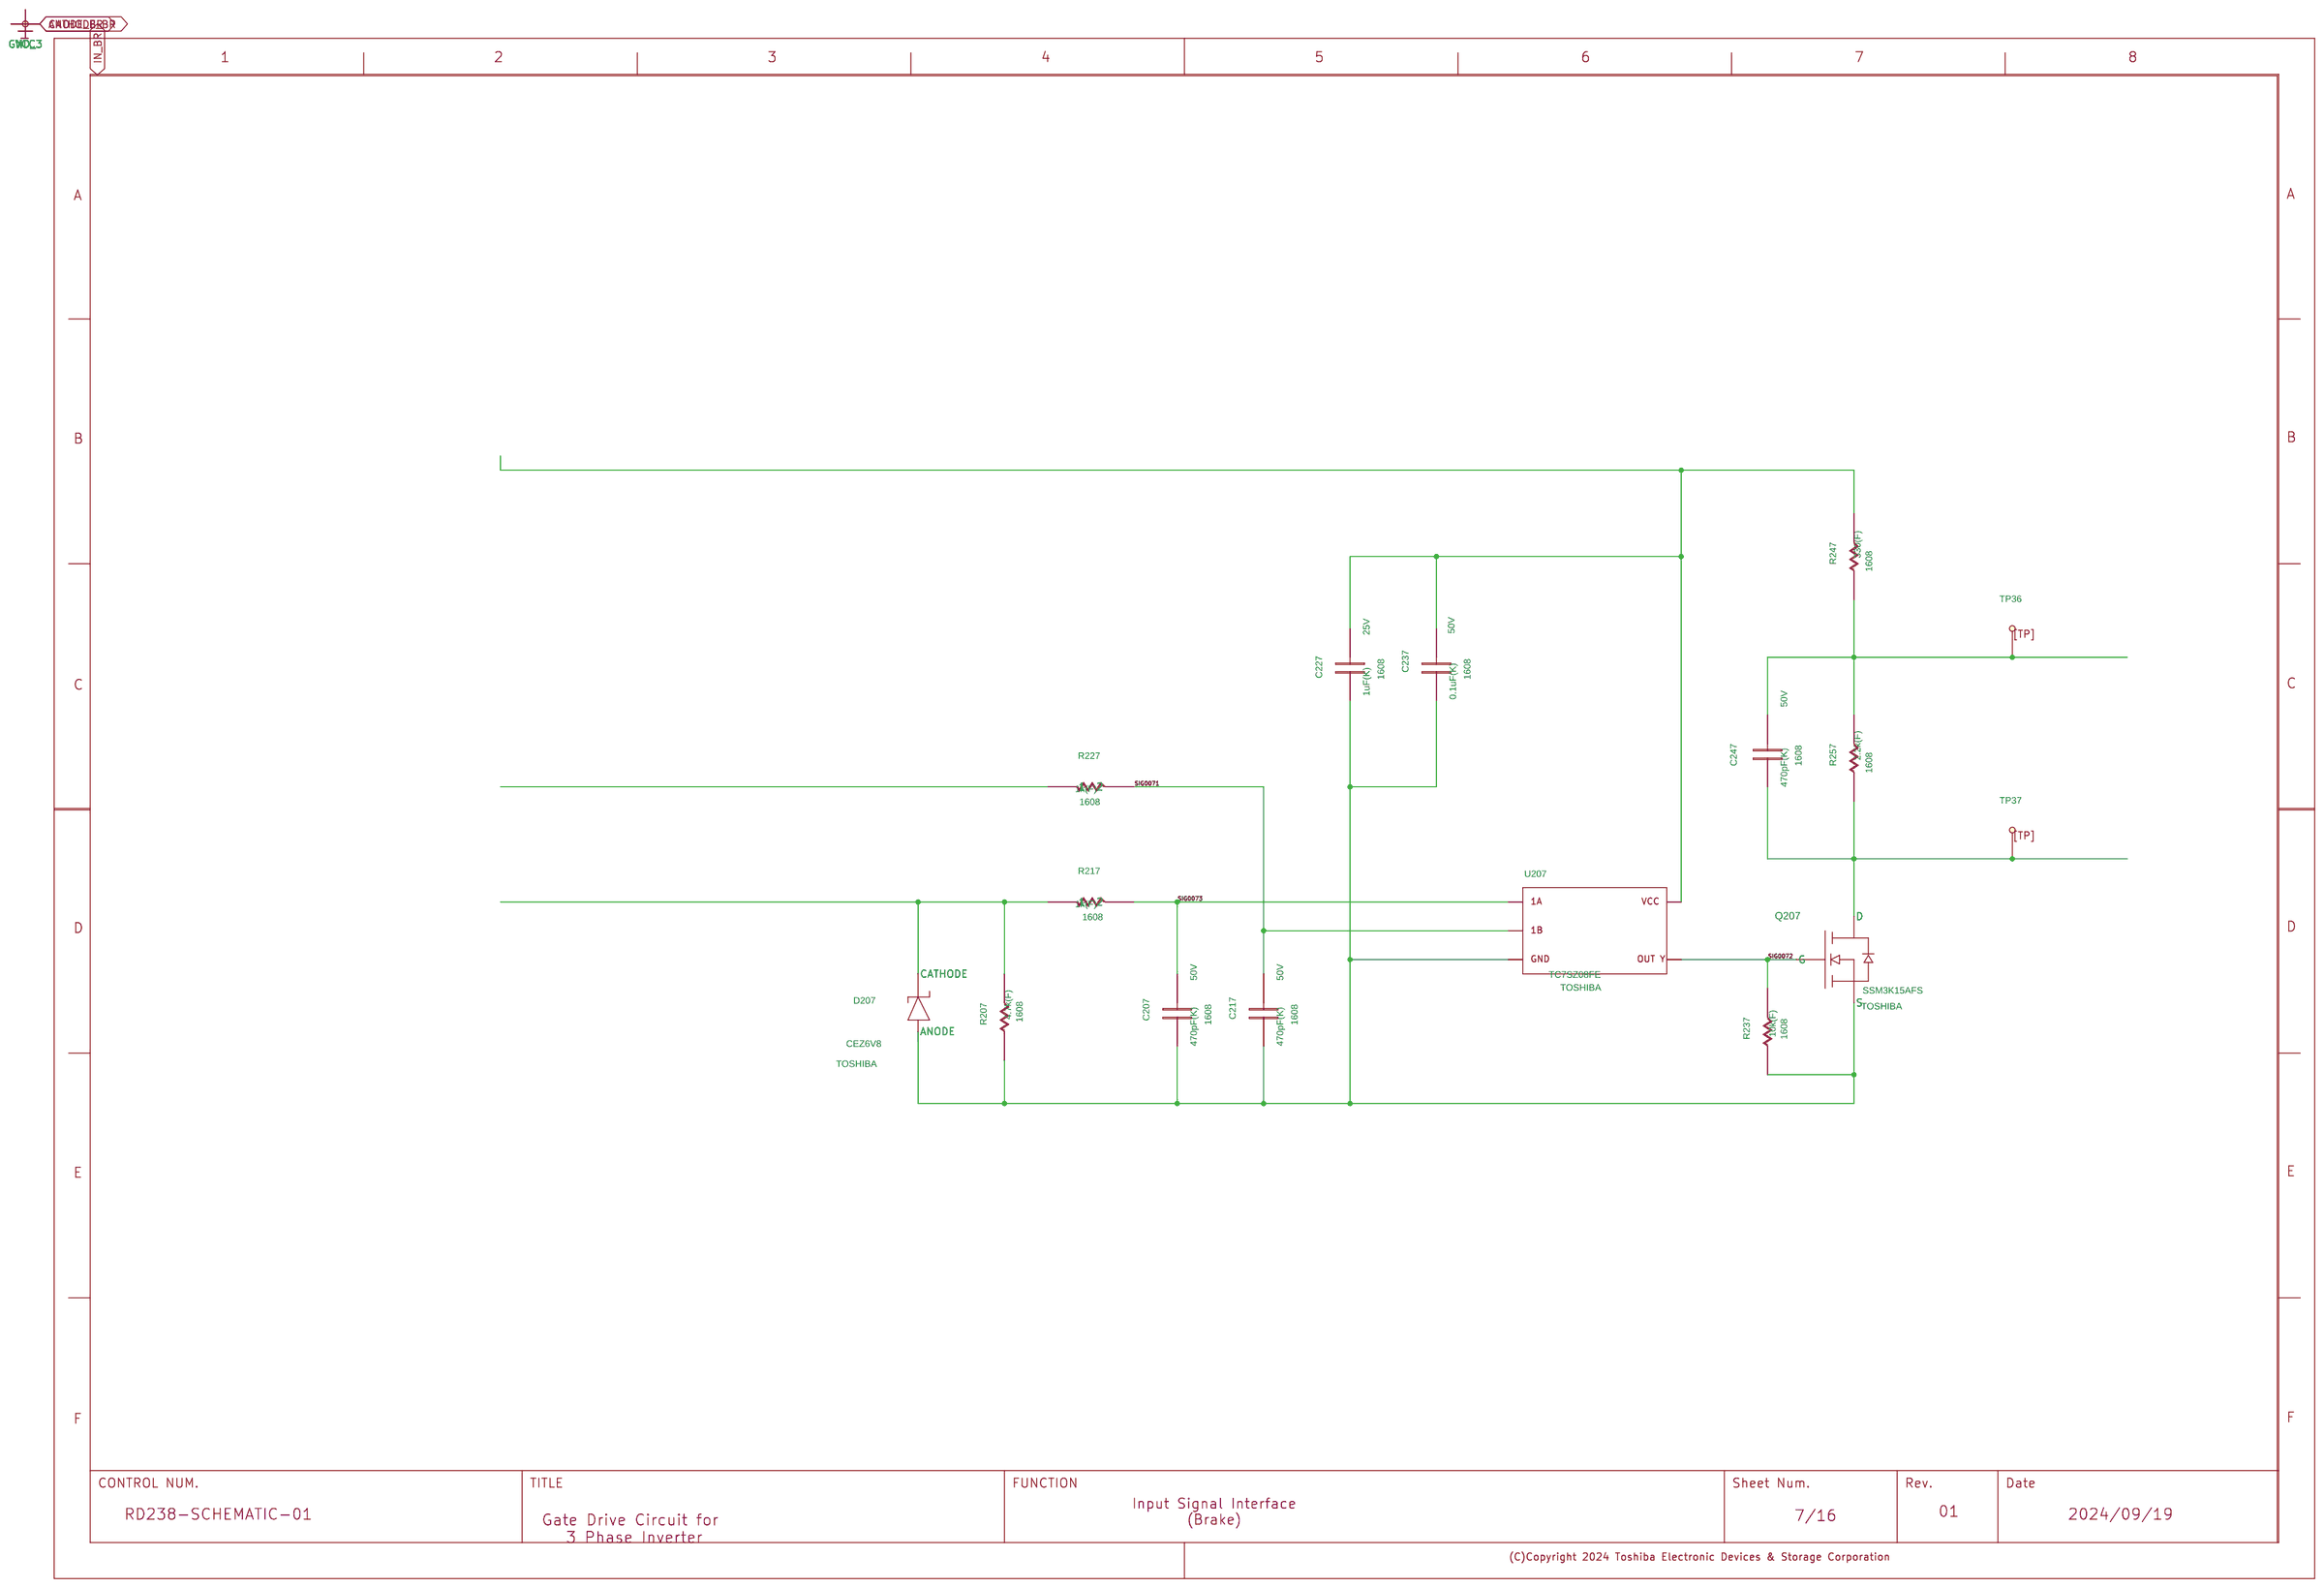
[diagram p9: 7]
11 6: size A3
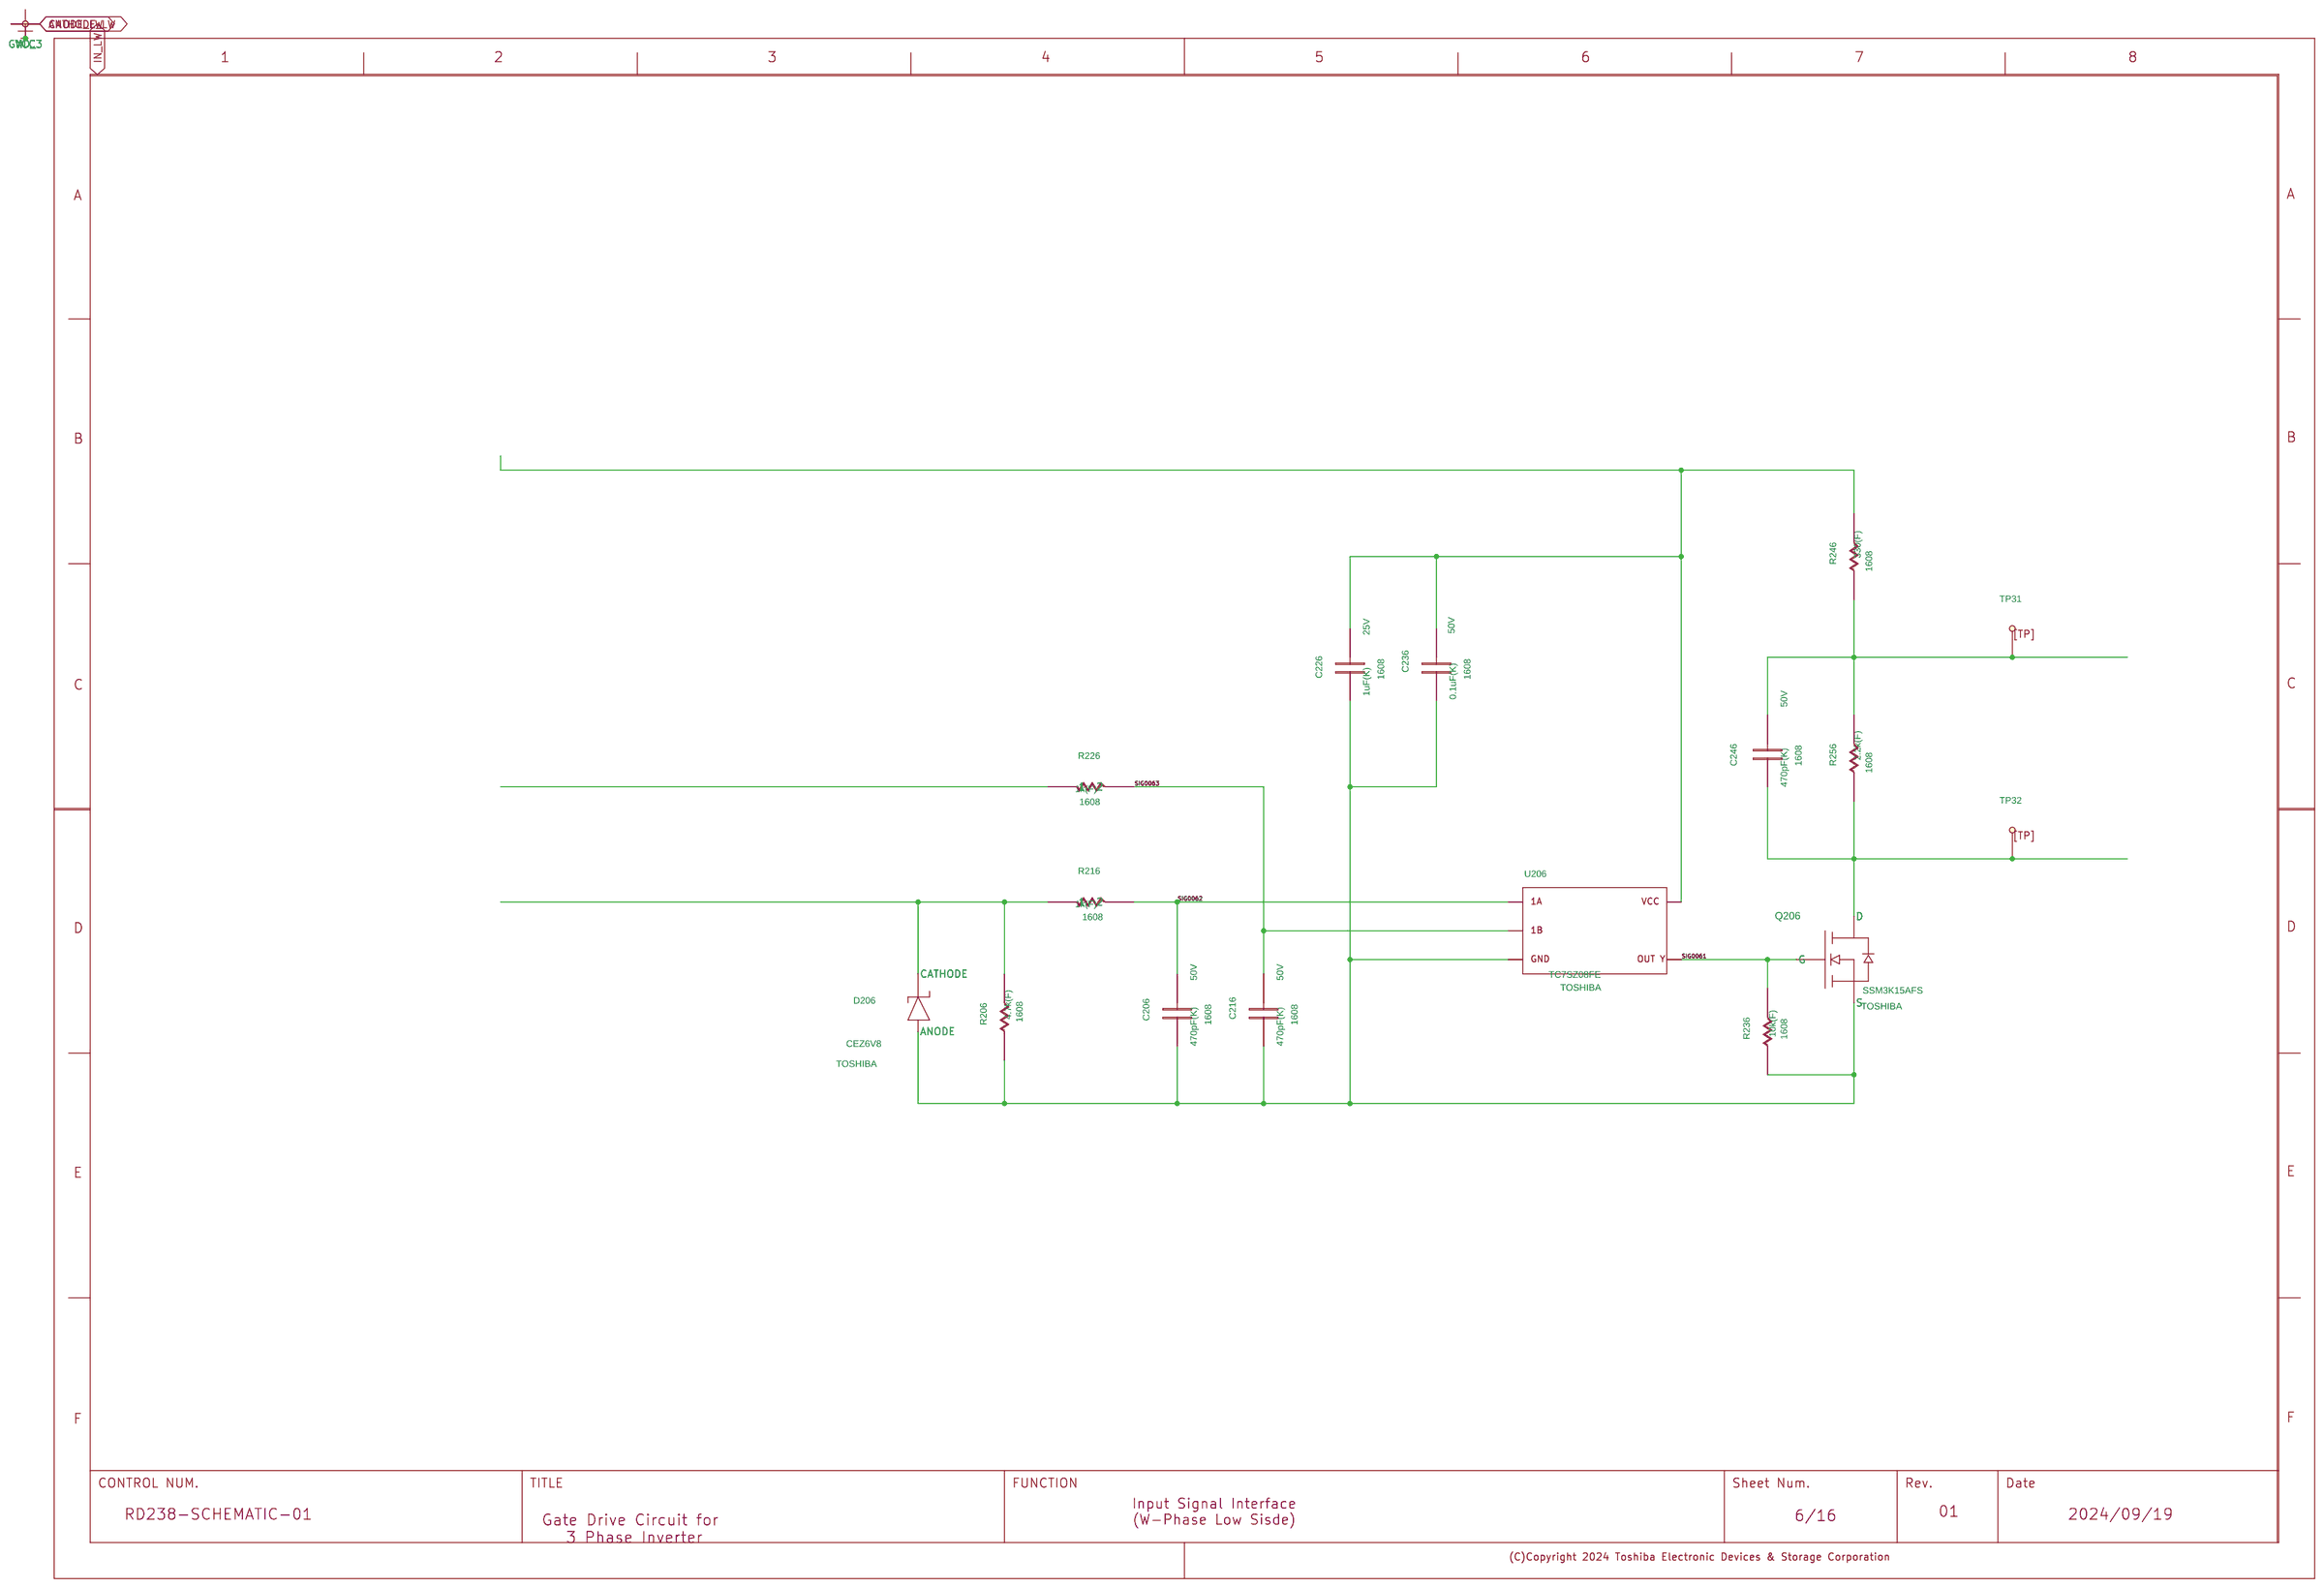
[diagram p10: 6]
12 5: size A3
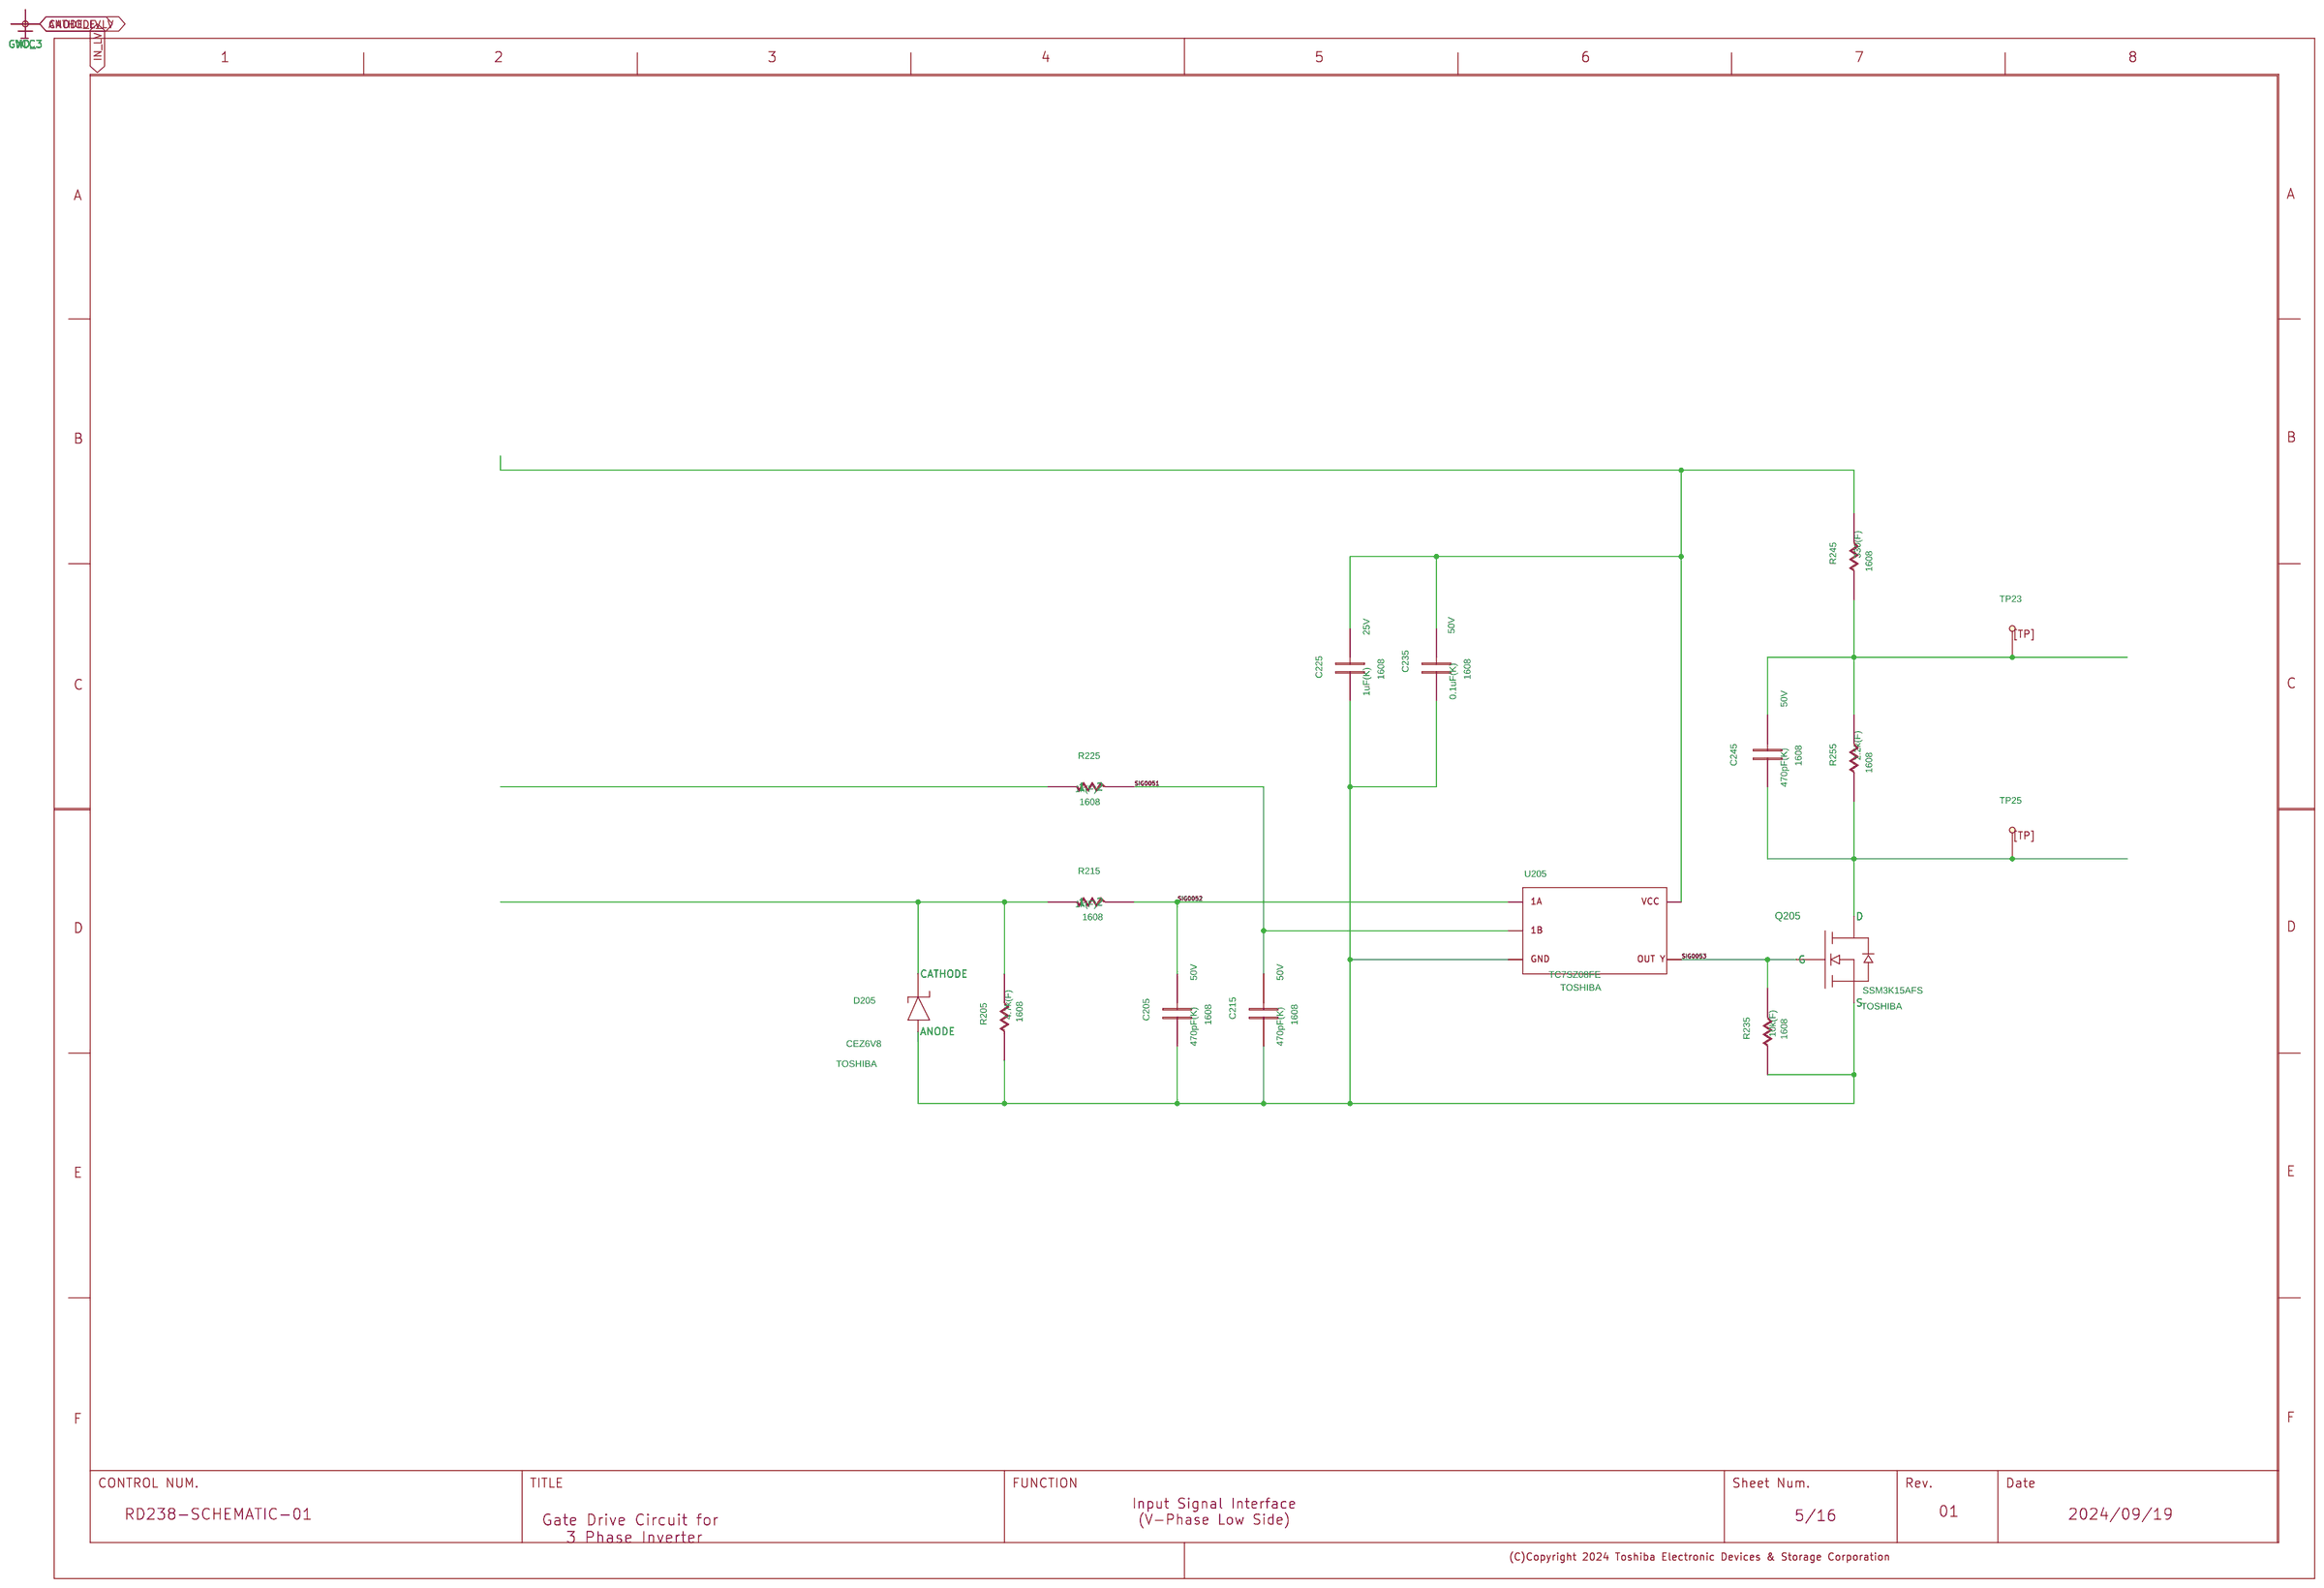
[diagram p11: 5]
13 4: size A3
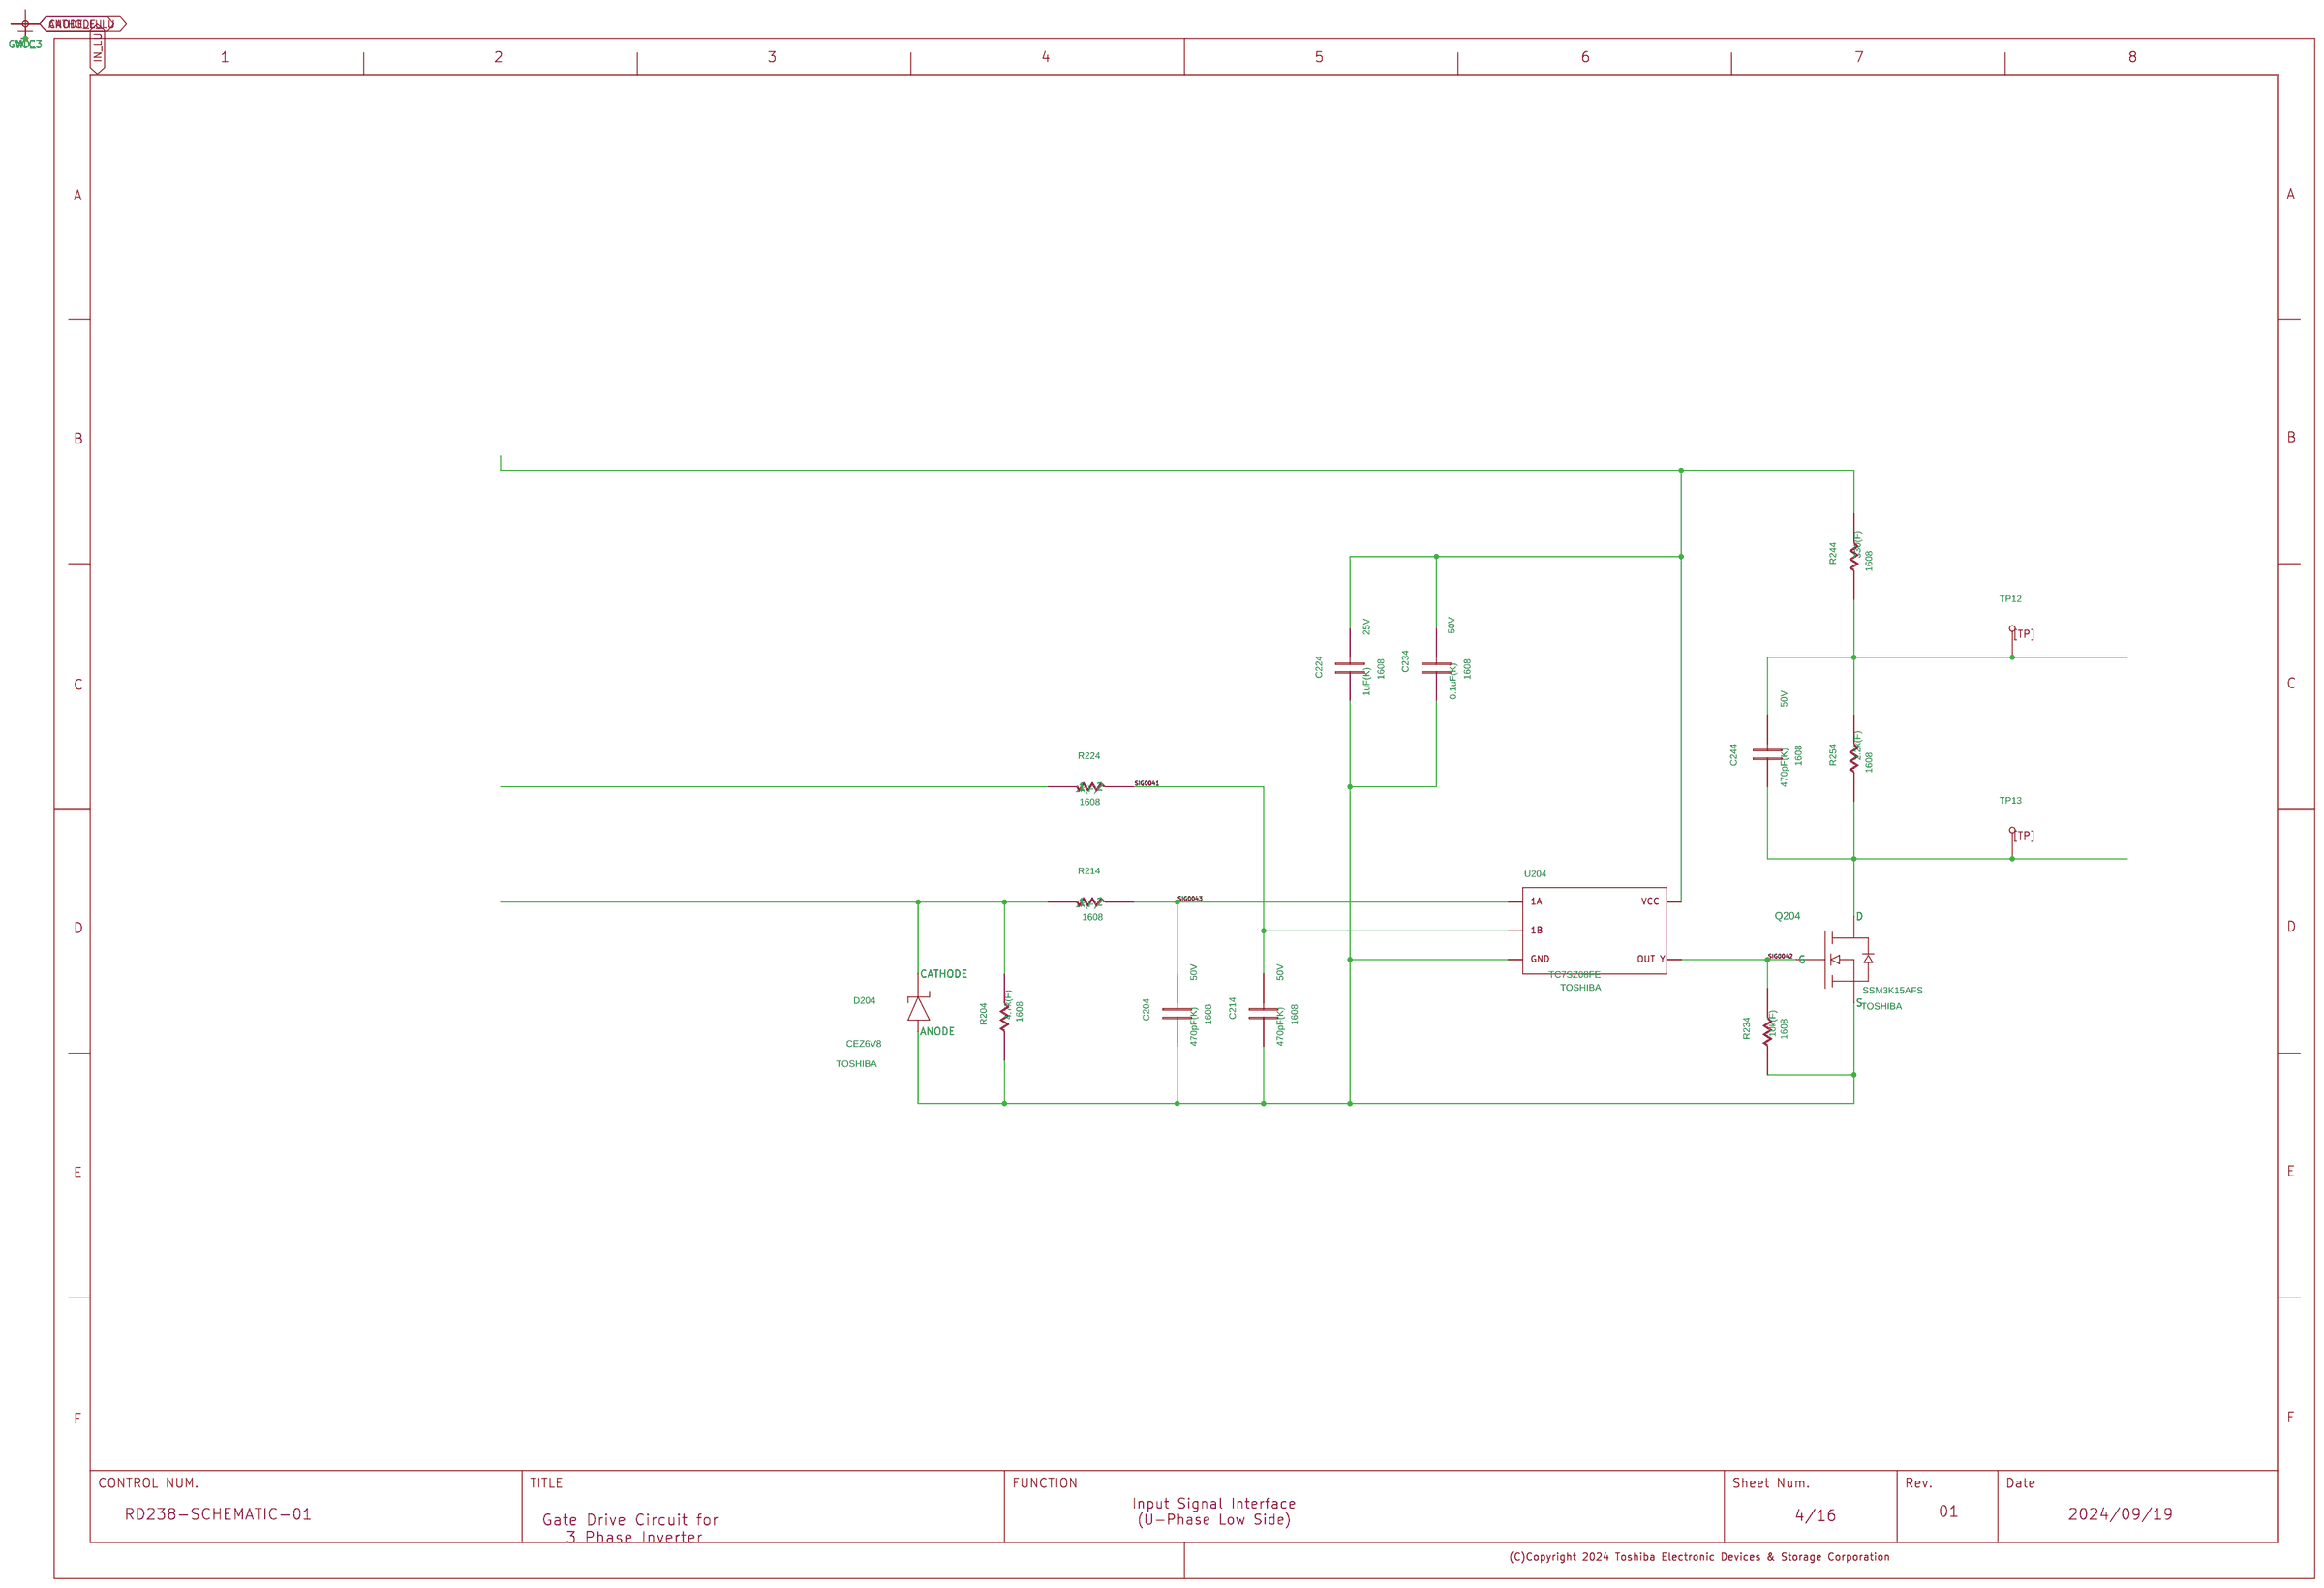
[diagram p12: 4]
14 3: size A3
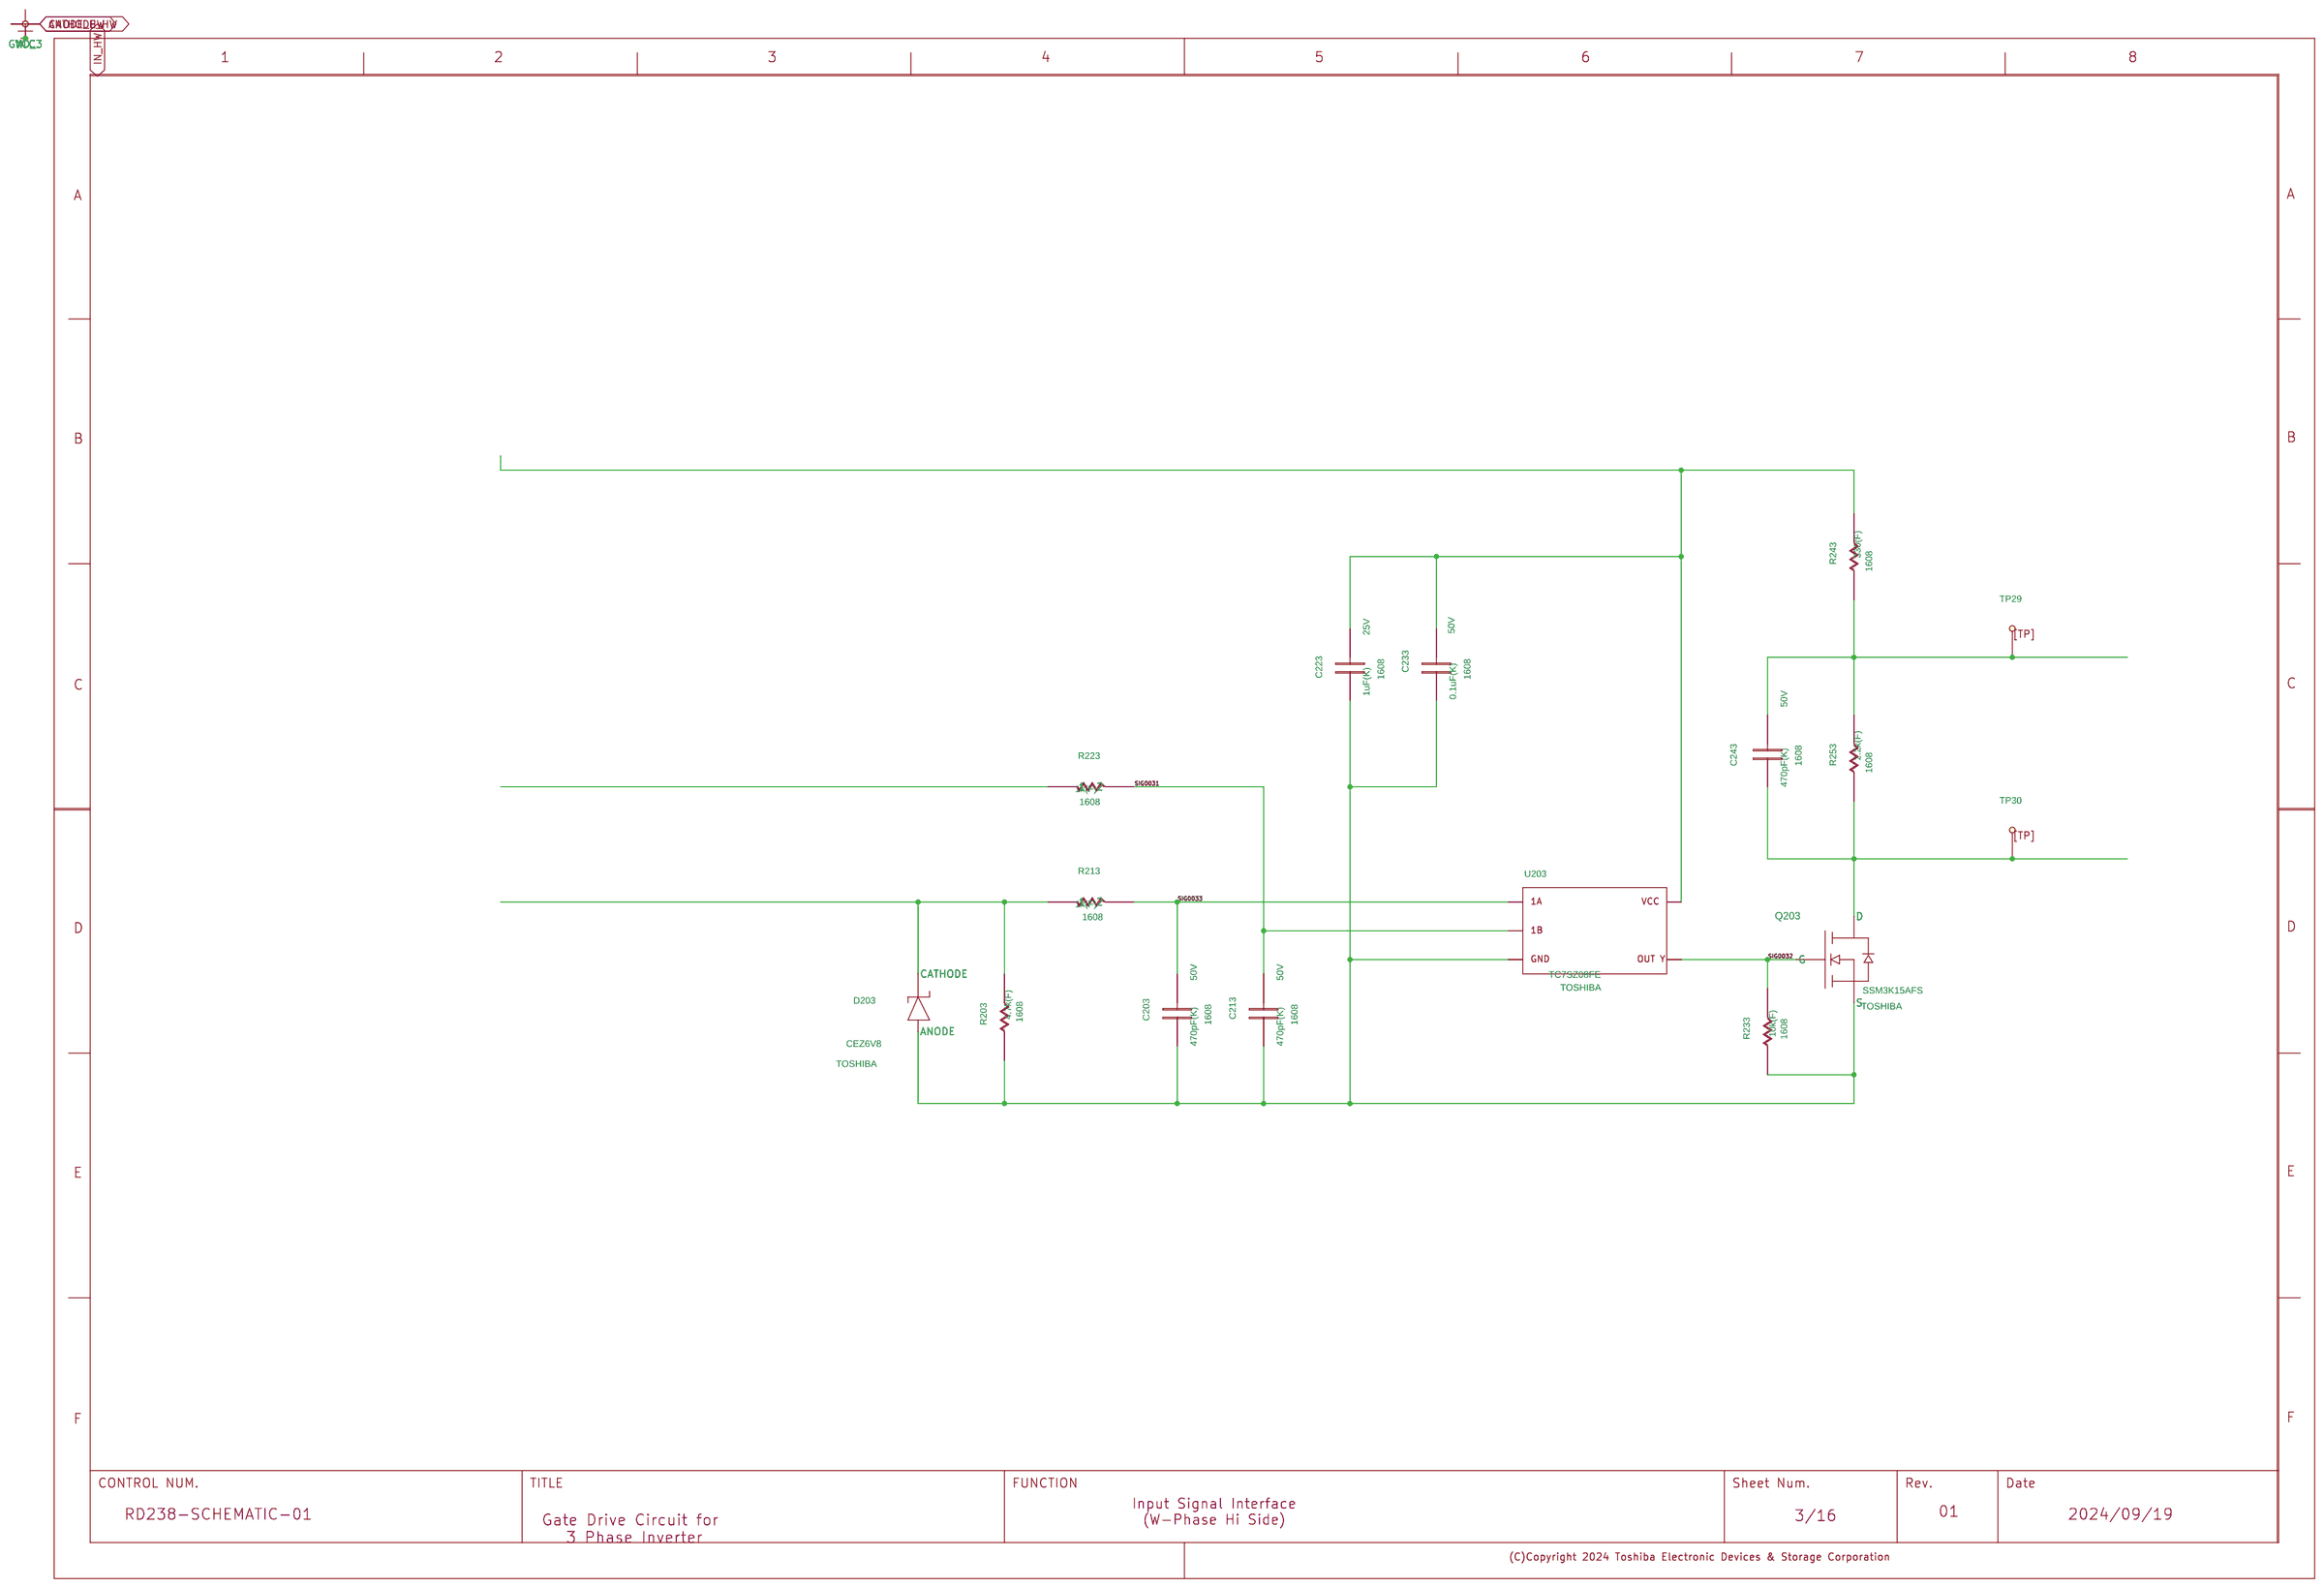
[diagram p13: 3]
15 2: size A3
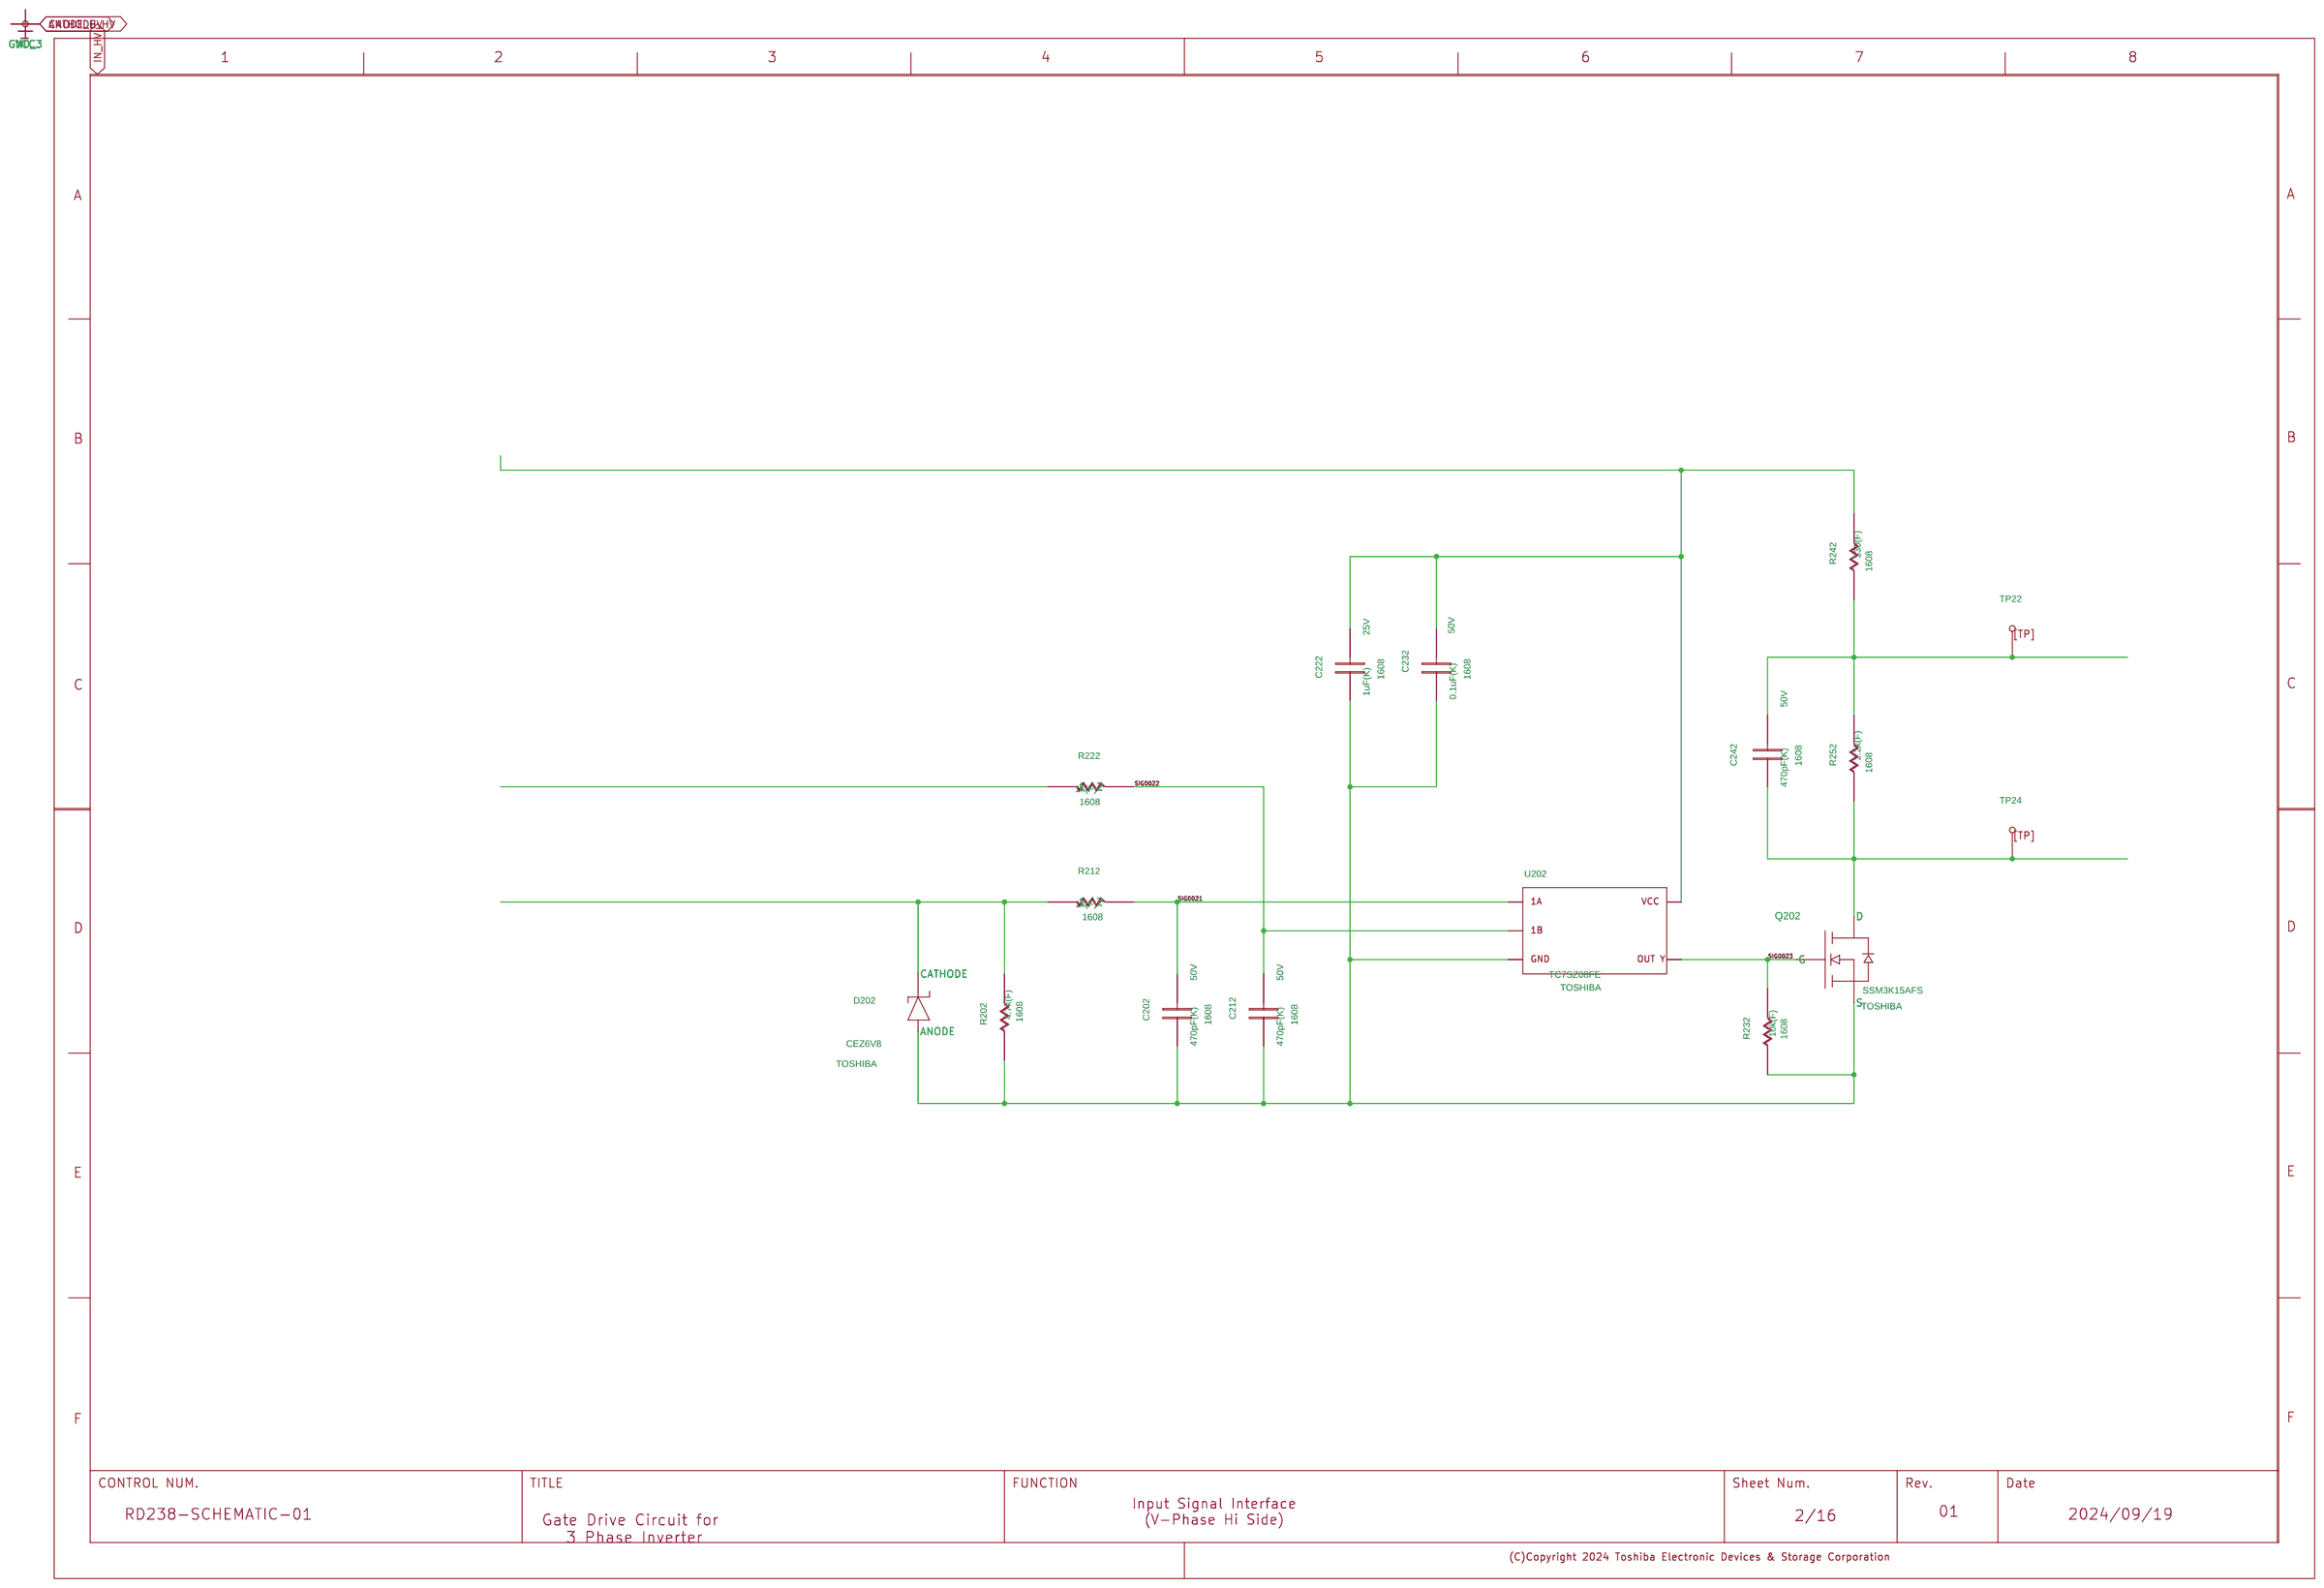
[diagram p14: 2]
16 1: size A3

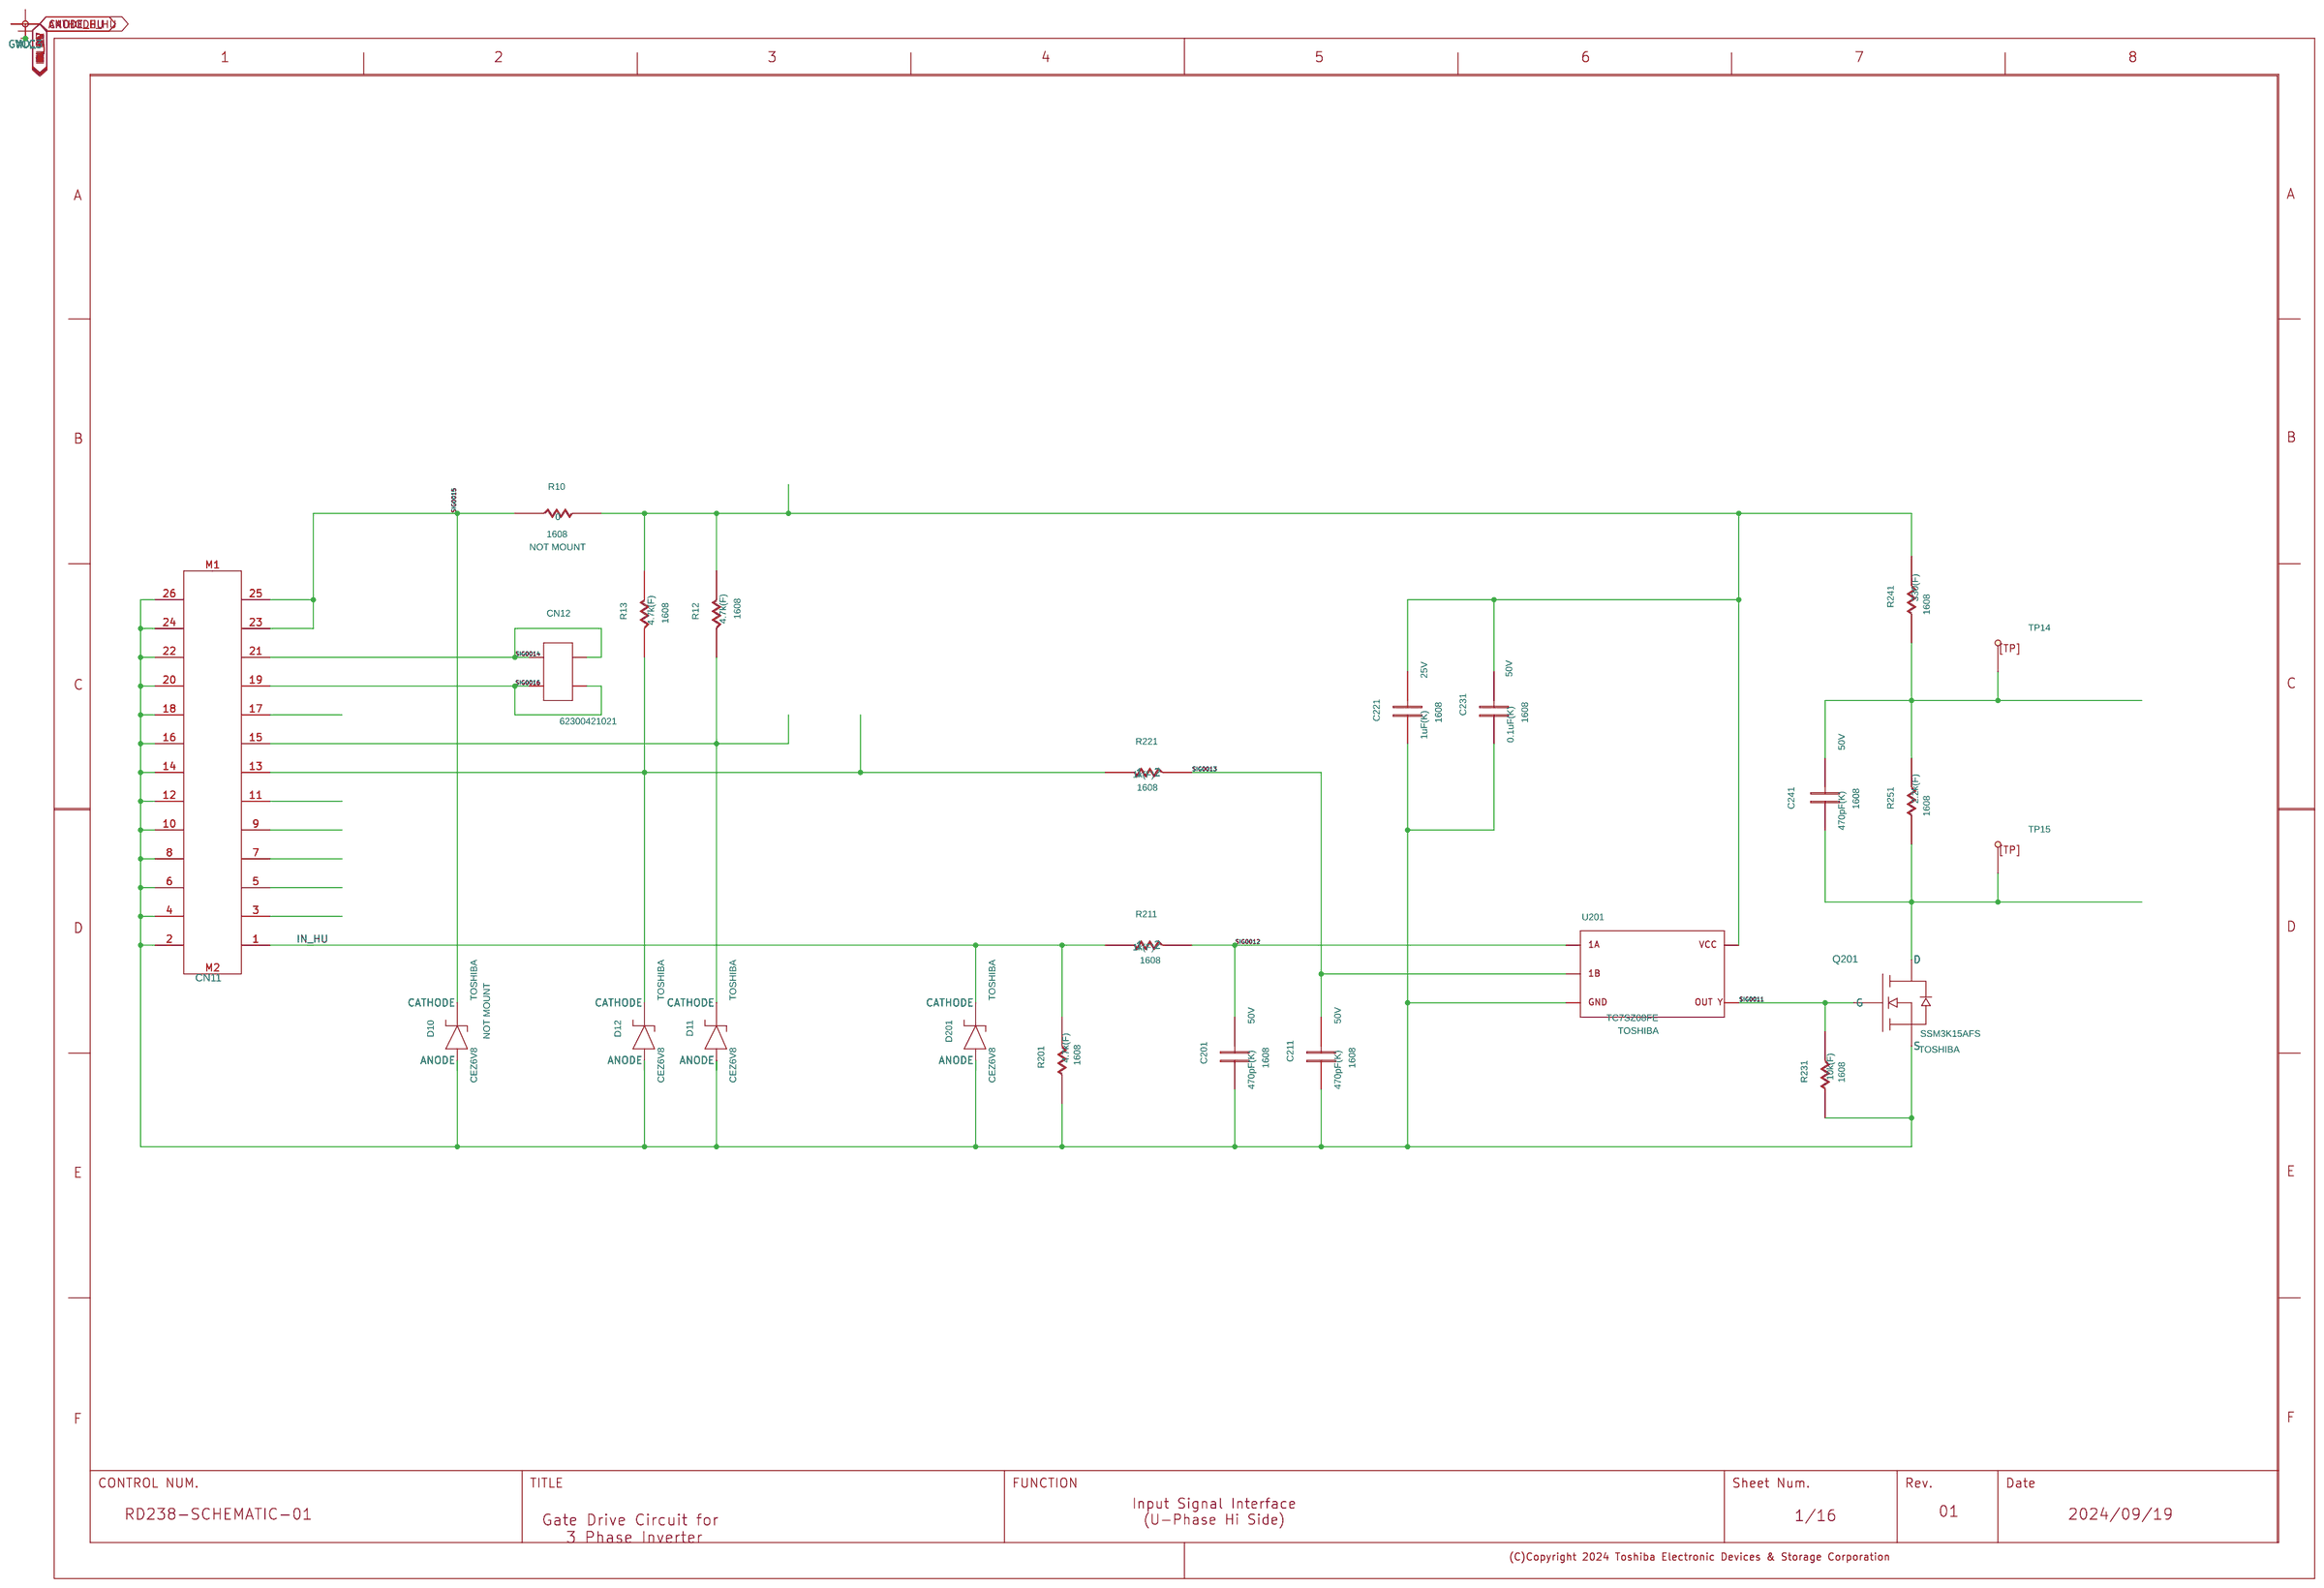
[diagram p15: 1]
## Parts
sheet 1
C201  C
C211  C
C221  C
C231  C
C241  C
CN11  XG4A-1431
CN12  TCR1HF50B
D10  CEZ5V6
D11  CEZ5V6
D12  CEZ5V6
D201  CEZ5V6
Q201  SSM3K318R
R10  R
R12  R
R13  R
R201  R
R211  R
R221  R
R231  R
R241  R
R251  R
TP14  TP
TP15  TP
U201  TCR1HF50B
U?#15  WAKU_DEF100
sheet 2
C202  C
C212  C
C222  C
C232  C
C242  C
D202  CEZ5V6
Q202  SSM3K318R
R202  R
R212  R
R222  R
R232  R
R242  R
R252  R
TP22  TP
TP24  TP
U202  TCR1HF50B
U?#14  WAKU_DEF100
sheet 3
C203  C
C213  C
C223  C
C233  C
C243  C
D203  CEZ5V6
Q203  SSM3K318R
R203  R
R213  R
R223  R
R233  R
R243  R
R253  R
TP29  TP
TP30  TP
U203  TCR1HF50B
U?#13  WAKU_DEF100
sheet 4
C204  C
C214  C
C224  C
C234  C
C244  C
D204  CEZ5V6
Q204  SSM3K318R
R204  R
R214  R
R224  R
R234  R
R244  R
R254  R
TP12  TP
TP13  TP
U204  TCR1HF50B
U?#12  WAKU_DEF100
sheet 5
C205  C
C215  C
C225  C
C235  C
C245  C
D205  CEZ5V6
Q205  SSM3K318R
R205  R
R215  R
R225  R
R235  R
R245  R
R255  R
TP23  TP
TP25  TP
U205  TCR1HF50B
U?#11  WAKU_DEF100
sheet 6
C206  C
C216  C
C226  C
C236  C
C246  C
D206  CEZ5V6
Q206  SSM3K318R
R206  R
R216  R
R226  R
R236  R
R246  R
R256  R
TP31  TP
TP32  TP
U206  TCR1HF50B
U?#10  WAKU_DEF100
sheet 7
C207  C
C217  C
C227  C
C237  C
C247  C
D207  CEZ5V6
Q207  SSM3K318R
R207  R
R217  R
R227  R
R237  R
R247  R
R257  R
TP36  TP
TP37  TP
U207  TCR1HF50B
U?#9  WAKU_DEF100
sheet 8
C301  C
C311  C
C321  C
C331  C
C341  C
C351  C
C361  C
C371  C
C381  C
CN13  TCR1HF50B
CN16  TCR1HF50B
D301  CEZ5V6
D311  1SS413
D321  D1
D331  D1
D341  D1
D351  D1
D361  1SS413
D371  CEZ5V6
R301  R
R311  R
R321  R
R331  R
R341  R
R351  R
R361  R
R371  R
R381  R
R391  R
R401  R
U301  TLP5231
U?#8  WAKU_DEF100
sheet 9
C302  C
C312  C
C322  C
C332  C
C342  C
C352  C
C362  C
C372  C
C382  C
CN18  TCR1HF50B
CN20  TCR1HF50B
D302  CEZ5V6
D312  1SS413
D322  D1
D332  D1
D342  D1
D352  D1
D362  1SS413
D372  CEZ5V6
R302  R
R312  R
R322  R
R332  R
R342  R
R352  R
R362  R
R372  R
R382  R
R392  R
R402  R
U302  TLP5231
U?#7  WAKU_DEF100
sheet 10
C303  C
C313  C
C323  C
C333  C
C343  C
C353  C
C363  C
C373  C
C383  C
CN21  TCR1HF50B
CN24  TCR1HF50B
D303  CEZ5V6
D313  1SS413
D323  D1
D333  D1
D343  D1
D353  D1
D363  1SS413
D373  CEZ5V6
R303  R
R313  R
R323  R
R333  R
R343  R
R353  R
R363  R
R373  R
R383  R
R393  R
R403  R
U303  TLP5231
U?#6  WAKU_DEF100
sheet 11
C304  C
C314  C
C324  C
C334  C
C344  C
C354  C
C364  C
C374  C
C384  C
CN14  TCR1HF50B
CN15  TCR1HF50B
D304  CEZ5V6
D314  1SS413
D324  D1
D334  D1
D344  D1
D354  D1
D364  1SS413
D374  CEZ5V6
R304  R
R314  R
R324  R
R334  R
R344  R
R354  R
R364  R
R374  R
R384  R
R394  R
R404  R
U304  TLP5231
U?#5  WAKU_DEF100
sheet 12
C305  C
C315  C
C325  C
C335  C
C345  C
C355  C
C365  C
C375  C
C385  C
CN17  TCR1HF50B
CN19  TCR1HF50B
D305  CEZ5V6
D315  1SS413
D325  D1
D335  D1
D345  D1
D355  D1
D365  1SS413
D375  CEZ5V6
R305  R
R315  R
R325  R
R335  R
R345  R
R355  R
R365  R
R375  R
R385  R
R395  R
R405  R
U305  TLP5231
U?#4  WAKU_DEF100
sheet 13
C306  C
C316  C
C326  C
C336  C
C346  C
C356  C
C366  C
C376  C
C386  C
CN22  TCR1HF50B
CN23  TCR1HF50B
D306  CEZ5V6
D316  1SS413
D326  D1
D336  D1
D346  D1
D356  D1
D366  1SS413
D376  CEZ5V6
R306  R
R316  R
R326  R
R336  R
R346  R
R356  R
R366  R
R376  R
R386  R
R396  R
R406  R
U306  TLP5231
U?#3  WAKU_DEF100
sheet 14
C307  C
C317  C
C327  C
C337  C
C347  C
C357  C
C367  C
C377  C
C387  C
CN25  TCR1HF50B
CN26  TCR1HF50B
D307  CEZ5V6
D317  1SS413
D327  D1
D337  D1
D347  D1
D357  D1
D367  1SS413
D377  CEZ5V6
R307  R
R317  R
R327  R
R337  R
R347  R
R357  R
R367  R
R377  R
R387  R
R397  R
R407  R
U307  TLP5231
U?#2  WAKU_DEF100
sheet 15
C50  C
C51  C
C52  C
C53  C
C54  C
C55  C
C56  C
C57  C
C58  C
C59  C
C60  C
C61  C
C62  C
C63  C
C64  C
C65  C
C66  C
C67  C
C68  C
C69  C
C70  C
C71  C
C72  C_2
C73  C_2
C74  C_2
C75  C_2
C76  C_2
C77  C_2
C78  C_2
C79  C_2
D50  ZD3
D51  SBD1
D52  D1
D53  D1
D54  D1
D55  D1
D56  SBD1
D57  SBD1
D58  SBD1
D59  SBD1
Q50  MFNE
R50  R
R51  R
R52  R
R53  R
R54  R
R55  R
R56  R
R57  R
R58  R
R59  R
R60  R
R61  R
R62  R
R75  R
R76  R
R77  R
R78  R
T50  750315038
TP16  TP
TP17  TP
TP18  TP
TP19  TP
TP20  TP
TP21  TP
TP26  TP
TP27  TP
TP28  TP
TP33  TP
TP34  TP
TP35  TP
U50  TCR1HF50B
U?#1  WAKU_DEF100
sheet 16
C10  C
C80  C
C81  C
C82  C
C83  C
C84  C
C85  C
CN10  XW4M-02DI-VIDS
D13  CEZ5V6
L80  L
R11  R
R80  R
R81  R
R82  R
R83  R
TP10  TP
TP11  TP
TP80  TP
U80  TCR1HF50B
U?#16  WAKU_DEF100

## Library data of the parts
C55 C201-C207 C211-C217 C241-C247 = C: COMPONENTTYPE: 4; SIZECODESMD: 1608; VAL1: 470pF(K); VAL2: 50V
C221-C227 = C: COMPONENTTYPE: 4; SIZECODESMD: 1608; VAL1: 1uF(K); VAL2: 25V
C64-C71 C81 C231-C237 C311-C317 = C: COMPONENTTYPE: 4; SIZECODESMD: 1608; VAL1: 0.1uF(K); VAL2: 50V
CN11 = XG4A_2632: COMPONENTTYPE: 4; VAL3: XG4A-2632
CN12 CN13 CN16 CN18 CN20 CN24 = NTC: COMP: CN; COMPONENTTYPE: 4; VAL3: 62300421021
D10 = CEZ5V6_D500: COMP: CEZ6V8; COMPONENTTYPE: 4; NOTMOUNT: NOT MOUNT; USERCOMPTEXT3: TOSHIBA; VAL3: CEZ6V8
D11 D12 D201 = CEZ5V6_D500: COMP: CEZ6V8; COMPONENTTYPE: 4; USERCOMPTEXT3: TOSHIBA; VAL3: CEZ6V8
Q201-Q207 = SSM3K15AFS_Q20: COMP: SSM3K15AFS; COMPONENTTYPE: 4; SAVECOUNT: 7; USERCOMPTEXT3: TOSHIBA; VAL3: SSM3K15AFS
R10 R381-R387 = R: COMPONENTTYPE: 4; NOTMOUNT: NOT MOUNT; SIZECODESMD: 1608; VAL1: 0; VAL2: 1A
R12 = R: COMPONENTTYPE: 4; NOTMOUNT: MOUNT; SIZECODESMD: 1608; VAL1: 4.7k(F); VAL2: 0.1W
R13 = R: COMPONENTTYPE: 4; NOTMOUNT: MOUNT; POWERMESURINGPROBE: YES; SIZECODESMD: 1608; VAL1: 4.7k(F); VAL2: 0.1W
R201-R207 = R: COMP: RK73H1JTTD4701F; COMPONENTTYPE: 4; SIZECODESMD: 1608; VAL1: 4.7k(F); VAL2: 0.1W
R211-R217 R221-R227 = R#1: COMPONENTTYPE: 4; CaptureCellPackProp: R##1; NOTMOUNT: MOUNT; SIZECODESMD: 1608; VAL1: 1k(F); VAL2: 100mW
R231-R237 = R: COMP: RK73H1JTTD2400F; COMPONENTTYPE: 4; SIZECODESMD: 1608; VAL1: 10k(F); VAL2: 0.1W
R241-R247 = R: COMP: RK73H1JTTD2400F; COMPONENTTYPE: 4; SIZECODESMD: 1608; VAL1: 330(F); VAL2: 0.1W
R251-R257 = R: COMP: RK73H1JTTD2400F; COMPONENTTYPE: 4; SIZECODESMD: 1608; VAL1: 2.2k(F); VAL2: 0.1W
TP10 TP11 TP14-TP21 TP26-TP28 TP33-TP35 TP80 = TP: COMP: TEST_PAD; COMPONENTTYPE: 4; VAL1: SWB
U201-U207 = TC7SZ08FE: COMP: U; COMPONENTTYPE: 4; SAVECOUNT: 8; USERCOMPTEXT3: TOSHIBA
U?#15 = WAKU_DEF100: COMPONENTTYPE: 2; DATE: 2024/09/19; DRAWINGNUMBER: RD238-SCHEMATIC-01; FUNCTION: Input Signal Interface / (U-Phase Hi Side); REVISION: 01; SHEETNUMBER: 1/16; SHTSAVECOUNT: 30; TITLE: Gate Drive Circuit for / 3 Phase Inverter; UPDATEDATE: 2024.9.19; UPDATETIME: 10:22:17
D202-D207 = CEZ5V6_D500: COMP: CEZ6V8_D201; COMPONENTTYPE: 4; USERCOMPTEXT3: TOSHIBA; VAL3: CEZ6V8
TP12 TP13 TP22-TP25 TP29-TP32 TP36 TP37 = TP: COMPONENTTYPE: 4
U?#14 = WAKU_DEF100: COMPONENTTYPE: 2; DATE: 2024/09/19; DRAWINGNUMBER: RD238-SCHEMATIC-01; FUNCTION: Input Signal Interface / (V-Phase Hi Side); REVISION: 01; SHEETNUMBER: 2/16; SHTSAVECOUNT: 20; TITLE: Gate Drive Circuit for / 3 Phase Inverter; UPDATEDATE: 2024.9.19; UPDATETIME: 10:22:17
U?#13 = WAKU_DEF100: COMPONENTTYPE: 2; DATE: 2024/09/19; DRAWINGNUMBER: RD238-SCHEMATIC-01; FUNCTION: Input Signal Interface / (W-Phase Hi Side); REVISION: 01; SHEETNUMBER: 3/16; SHTSAVECOUNT: 25; TITLE: Gate Drive Circuit for / 3 Phase Inverter; UPDATEDATE: 2024.9.19; UPDATETIME: 10:22:17
U?#12 = WAKU_DEF100: COMPONENTTYPE: 2; DATE: 2024/09/19; DRAWINGNUMBER: RD238-SCHEMATIC-01; FUNCTION: Input Signal Interface / (U-Phase Low Side); REVISION: 01; SHEETNUMBER: 4/16; SHTSAVECOUNT: 24; TITLE: Gate Drive Circuit for / 3 Phase Inverter; UPDATEDATE: 2024.9.19; UPDATETIME: 10:22:17
U?#11 = WAKU_DEF100: COMPONENTTYPE: 2; DATE: 2024/09/19; DRAWINGNUMBER: RD238-SCHEMATIC-01; FUNCTION: Input Signal Interface / (V-Phase Low Side); REVISION: 01; SHEETNUMBER: 5/16; SHTSAVECOUNT: 23; TITLE: Gate Drive Circuit for / 3 Phase Inverter; UPDATEDATE: 2024.9.19; UPDATETIME: 10:22:17
U?#10 = WAKU_DEF100: COMPONENTTYPE: 2; DATE: 2024/09/19; DRAWINGNUMBER: RD238-SCHEMATIC-01; FUNCTION: Input Signal Interface / (W-Phase Low Sisde); REVISION: 01; SHEETNUMBER: 6/16; SHTSAVECOUNT: 22; TITLE: Gate Drive Circuit for / 3 Phase Inverter; UPDATEDATE: 2024.9.19; UPDATETIME: 10:22:17
U?#9 = WAKU_DEF100: COMPONENTTYPE: 2; DATE: 2024/09/19; DRAWINGNUMBER: RD238-SCHEMATIC-01; FUNCTION: Input Signal Interface / (Brake); REVISION: 01; SHEETNUMBER: 7/16; SHTSAVECOUNT: 25; TITLE: Gate Drive Circuit for / 3 Phase Inverter; UPDATEDATE: 2024.9.19; UPDATETIME: 10:22:17
C301-C307 = C: COMPONENTTYPE: 4; SIZECODESMD: 1608; VAL1: 1000pF(K); VAL2: 25V
C53 C321-C327 C331-C337 C341-C347 = C: COMPONENTTYPE: 4; SIZECODESMD: 1608; VAL1: 1uF(K); VAL2: 50V
C50 C52 C56-C63 C351-C357 C361-C367 C371-C377 = C: COMPONENTTYPE: 4; SIZECODESMD: 2012; VAL1: 10uF(K); VAL2: 50V
C381-C387 = C: COMPONENTTYPE: 4; SIZECODESMD: 1608; VAL1: 100pF(F); VAL2: 50V
D301-D307 = CEZ5V6_D500: COMP: CUZ8V2; COMPONENTTYPE: 4; USERCOMPTEXT3: TOSHIBA; VAL3: CUZ8V2
D311-D317 = 1SS413_D501: COMP: CUS05F30; COMPONENTTYPE: 4; USERCOMPTEXT3: TOSHIBA; VAL3: CUS05F30
D321-D327 D331-D337 D341-D347 D351-D357 = D1: COMP: CRF03A; COMPONENTTYPE: 4; USERCOMPTEXT3: TOSHIBA; VAL3: CRF03A
D361-D367 = 1SS413_D501: COMP: CUHS10F60; COMPONENTTYPE: 4; USERCOMPTEXT3: TOSHIBA; VAL3: CUHS10F60
D371-D377 = CEZ5V6_D500: COMPONENTTYPE: 4; VAL3: MMSZ4678-HF
R301-R307 = R: COMPONENTTYPE: 4; SIZECODESMD: 1608; VAL1: 18k(F); VAL2: 0.1W
R311-R317 = R: COMPONENTTYPE: 4; SIZECODESMD: 1608; VAL1: 30k(F); VAL2: 0.1W
R321-R327 R331-R337 = R: COMPONENTTYPE: 4; SIZECODESMD: 2012; VAL1: 10(F); VAL2: 0.5W
R341-R347 = R: COMPONENTTYPE: 4; SIZECODESMD: 1608; VAL1: 360(F); VAL2: 0.125W
R11 R55 R56 R351-R357 = R: COMPONENTTYPE: 4; SIZECODESMD: 1608; VAL1: 0; VAL2: 1A
R361-R367 R371-R377 = R: COMPONENTTYPE: 4; SIZECODESMD: 2012; VAL1: 5.6(F); VAL2: 0.5W
R391-R397 R401-R407 = R: COMPONENTTYPE: 4; SIZECODESMD: 1608; VAL1: 10(F); VAL2: 0.5W
U301-U307 = TLP5222: COMPONENTTYPE: 4; USERCOMPTEXT3: TOSHIBA
U?#8 = WAKU_DEF100: COMPONENTTYPE: 2; DATE: 2024/09/19; DRAWINGNUMBER: RD238-SCHEMATIC-01; FUNCTION: Gate Drive Output, DESAT Detection / (U-Phase Hi Side); REVISION: 01; SHEETNUMBER: 8/16; SHTSAVECOUNT: 29; TITLE: Gate Drive Circuit for / 3 Phase Inverter; UPDATEDATE: 2024.9.19; UPDATETIME: 13:49:47
U?#7 = WAKU_DEF100: COMPONENTTYPE: 2; DATE: 2024/09/19; DRAWINGNUMBER: RD238-SCHEMATIC-01; FUNCTION: Gate Drive Output, DESAT Detection / (V-Phase Hi Side); REVISION: 01; SHEETNUMBER: 9/16; SHTSAVECOUNT: 33; TITLE: Gate Drive Circuit for / 3 Phase Inverter; UPDATEDATE: 2024.9.19; UPDATETIME: 13:49:47
CN21 = NTC: COMP: DESAT_TOPW; COMPONENTTYPE: 4; VAL3: 62300421021
U?#6 = WAKU_DEF100: COMP: VS; COMPONENTTYPE: 2; DATE: 2024/09/19; DRAWINGNUMBER: RD238-SCHEMATIC-01; FUNCTION: Gate Drive Output, DESAT Detection / (W-Phase Hi Side); REVISION: 01; SHEETNUMBER: 10/16; SHTSAVECOUNT: 30; TITLE: Gate Drive Circuit for / 3 Phase Inverter; UPDATEDATE: 2024.9.19; UPDATETIME: 13:49:47
CN14 = NTC: COMP: DESAT_BOTU; COMPONENTTYPE: 4; VAL3: 62300421021
CN15 = NTC: COMP: GS_BOTU; COMPONENTTYPE: 4; VAL3: 62300421021
U?#5 = WAKU_DEF100: COMP: VCC1; COMPONENTTYPE: 2; DATE: 2024/09/19; DRAWINGNUMBER: RD238-SCHEMATIC-01; FUNCTION: Gate Drive Output, DESAT Detection / (U-Phase Low Side); REVISION: 01; SHEETNUMBER: 11/16; SHTSAVECOUNT: 34; TITLE: Gate Drive Circuit for / 3 Phase Inverter; UPDATEDATE: 2024.9.19; UPDATETIME: 13:49:47
CN17 = NTC: COMP: DESAT_BOTV; COMPONENTTYPE: 4; VAL3: 62300421021
CN19 = NTC: COMP: GS_BOTV; COMPONENTTYPE: 4; VAL3: 62300421021
U?#4 = WAKU_DEF100: COMP: VCC1; COMPONENTTYPE: 2; DATE: 2024/09/19; DRAWINGNUMBER: RD238-SCHEMATIC-01; FUNCTION: Gate Drive Output, DESAT Detection / (W-Phase Low Side); REVISION: 01; SHEETNUMBER: 12/16; SHTSAVECOUNT: 34; TITLE: Gate Drive Circuit for / 3 Phase Inverter; UPDATEDATE: 2024.9.19; UPDATETIME: 13:49:47
CN22 = NTC: COMP: DESAT_BOTW; COMPONENTTYPE: 4; VAL3: 62300421021
CN23 = NTC: COMP: GS_BOTW; COMPONENTTYPE: 4; VAL3: 62300421021
U?#3 = WAKU_DEF100: COMP: VCC1; COMPONENTTYPE: 2; DATE: 2024/09/19; DRAWINGNUMBER: RD238-SCHEMATIC-01; FUNCTION: Gate Drive Output, DESAT Detection / (W-Phase Low Side); REVISION: 01; SHEETNUMBER: 13/16; SHTSAVECOUNT: 29; TITLE: Gate Drive Circuit for / 3 Phase Inverter; UPDATEDATE: 2024.9.19; UPDATETIME: 13:49:47
CN25 = NTC: COMP: DESAT_BR; COMPONENTTYPE: 4; VAL3: 62300421021
CN26 = NTC: COMP: GS_BR; COMPONENTTYPE: 4; VAL3: 62300421021
U?#2 = WAKU_DEF100: COMP: VCC1; COMPONENTTYPE: 2; DATE: 2024/09/19; DRAWINGNUMBER: RD238-SCHEMATIC-01; FUNCTION: Gate Drive Output, DESAT Detection / (Brake); REVISION: 01; SHEETNUMBER: 14/16; SHTSAVECOUNT: 31; TITLE: Gate Drive Circuit for / 3 Phase Inverter; UPDATEDATE: 2024.9.19; UPDATETIME: 13:49:47
C51 C80 = C: COMPONENTTYPE: 4; SIZECODESMD: 1608; VAL1: 1000pF(K); VAL2: 50V
C54 = C: COMPONENTTYPE: 4; NOTMOUNT: NOT MOUNT; SIZECODESMD: 1608; VAL1: 1000pF(K); VAL2: 50V
C72-C79 = C_2: COMP: C; COMPONENTTYPE: 4; VAL1: 47uF(M); VAL2: 35V
D50 = ZD3: COMP: CRZ33; COMPONENTTYPE: 4; USERCOMPTEXT3: TOSHIBA; VAL3: CRZ33
D51 = SBD1: COMP: CUHS10F60; COMPONENTTYPE: 4; USERCOMPTEXT3: TOSHIBA; VAL3: CUHS10F60
D52-D55 = D1: COMP: CRH01; COMPONENTTYPE: 4; USERCOMPTEXT3: TOSHIBA; VAL3: CRH01
D56-D59 = SBD1: COMP: CMS03; COMPONENTTYPE: 4; USERCOMPTEXT3: TOSHIBA; VAL3: CMS03
Q50 = MFNE: COMP: SSM6K819R; COMPONENTTYPE: 4; USERCOMPTEXT3: TOSHIBA; VAL3: SSM6K819R
R50 = R: COMPONENTTYPE: 4; SIZECODESMD: 1608; VAL1: 330k(F); VAL2: 0.1W
R51 = R: COMPONENTTYPE: 4; SIZECODESMD: 1608; VAL1: 33k(F); VAL2: 0.1W
R52 = R: COMPONENTTYPE: 4; SIZECODESMD: 1608; VAL1: 100k(F); VAL2: 100mW
R53 = R: COMPONENTTYPE: 4; SIZECODESMD: 1608; VAL1: 39(F); VAL2: 0.125W
R54 = R: COMPONENTTYPE: 4; SIZECODESMD: 1608; VAL1: 4.7k(F); VAL2: 0.1W
R57 R58 = R: COMPONENTTYPE: 4; SIZECODESMD: 2012; VAL1: 10m(F); VAL2: 0.5W
R59-R61 = R: COMPONENTTYPE: 4; SIZECODESMD: 2012; VAL1: 2.2k(F); VAL2: 0.5W
R62 = R: COMPONENTTYPE: 4; SIZECODESMD: 2012; VAL1: 2.2K(F); VAL2: 0.5W
R75-R78 = R: COMPONENTTYPE: 4; SIZECODESMD: 1608; VAL1: 820(F); VAL2: 0.125W
T50 = 750315038: COMPONENTTYPE: 4; VAL1: 1:2.3:2.3:2.3:2.3
U50 = LT8306: COMP: U; COMPONENTNAME: LT8306RS6; COMPONENTTYPE: 4; VAL3: LT8306RS6
U?#1 = WAKU_DEF100: COMPONENTTYPE: 2; DATE: 2024/09/19; DRAWINGNUMBER: RD238-SCHEMATIC-01; FUNCTION: Isolated DC-DC Converter; REVISION: 01; SHEETNUMBER: 15/16; SHTSAVECOUNT: 54; TITLE: Gate Drive Circuit for / 3 Phase Inverter; UPDATEDATE: 2024.9.19; UPDATETIME: 10:22:18
C10 = C: COMPONENTTYPE: 4; NOTMOUNT: NOT MOUNT; SIZECODESMD: 1608; VAL1: 1uF(K); VAL2: 50V
C82 C83 = C: COMPONENTTYPE: 4; SIZECODESMD: 1608; VAL1: 4.7uF(K); VAL2: 50V
C84 C85 = C: COMPONENTTYPE: 4; SIZECODESMD: 2012; VAL1: 22uF(K); VAL2: 25V
CN10 = XW4M-02DI-VIDS: COMP: CN; COMPONENTTYPE: 4; VAL3: XW4M-02D1-V1DS
D13 = CEZ5V6_D500#1: COMP: CRZ36; COMPONENTTYPE: 4; CaptureCellPackProp: CEZ5V6_D500##1; USERCOMPTEXT3: TOSHIBA; VAL3: CRZ36
L80 = L: COMPONENTTYPE: 4; VAL1: 4.7uH(M); VAL2: 2.1A; VAL3: 74405042047
R80 = R: COMPONENTTYPE: 4; SIZECODESMD: 1608; VAL1: 15k(F); VAL2: 100mW
R81 = R: COMPONENTTYPE: 4; SIZECODESMD: 1608; VAL1: 82k(F); VAL2: 100mW
R82 = R: COMPONENTTYPE: 4; SIZECODESMD: 1608; VAL1: 12k(F); VAL2: 100mW
R83 = R: COMPONENTTYPE: 4; SIZECODESMD: 1608; VAL1: 1.2k(F); VAL2: 100mW
U80 = LMR51430XDDCR: COMP: U; COMPONENTTYPE: 4
U?#16 = WAKU_DEF100: COMPONENTTYPE: 2; DATE: 2024/09/19; DRAWINGNUMBER: RD238-SCHEMATIC-01; FUNCTION: 5V Output DC-DC Converter; REVISION: 01; SHEETNUMBER: 16/16; SHTSAVECOUNT: 34; TITLE: Gate Drive Circuit for / 3 Phase Inverter; UPDATEDATE: 2024.9.19; UPDATETIME: 10:22:38

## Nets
5V: C221.2 C222.2 C223.2 C224.2 C225.2 C226.2 C227.2 C231.2 C232.2 C233.2 C234.2 C235.2 C236.2 C237.2 C311.1 C312.1 C313.1 C314.1 C315.1 C316.1 C317.1 R10.1 R11.2 R12.1 R13.1 R241.2 R242.2 R243.2 R244.2 R245.2 R246.2 R247.2 U201.5 U202.5 U203.5 U204.5 U205.5 U206.5 U207.5 U301.2(VCC1) U302.2(VCC1) U303.2(VCC1) U304.2(VCC1) U305.2(VCC1) U306.2(VCC1) U307.2(VCC1)
GND: C10.1 C50.1 C51.1 C52.1 C53.1 C54.1 C80.1 C82.1 C83.1 C84.1 C85.1 C201.1 C202.1 C203.1 C204.1 C205.1 C206.1 C207.1 C211.1 C212.1 C213.1 C214.1 C215.1 C216.1 C217.1 C221.1 C222.1 C223.1 C224.1 C225.1 C226.1 C227.1 C231.1 C232.1 C233.1 C234.1 C235.1 C236.1 C237.1 C301.2 C302.2 C303.2 C304.2 C305.2 C306.2 C307.2 C311.2 C312.2 C313.2 C314.2 C315.2 C316.2 C317.2 CN10.2 CN11.2 CN11.4 CN11.6 CN11.8 CN11.10 CN11.12 CN11.14 CN11.16 CN11.18 CN11.20 CN11.22 CN11.24 CN11.26 D10.2(ANODE) D11.2(ANODE) D12.2(ANODE) D13.1(ANODE) D201.2(ANODE) D202.2(ANODE) D203.2(ANODE) D204.2(ANODE) D205.2(ANODE) D206.2(ANODE) D207.2(ANODE) Q201.2(S) Q202.2(S) Q203.2(S) Q204.2(S) Q205.2(S) Q206.2(S) Q207.2(S) R51.1 R58.1 R83.1 R201.1 R202.1 R203.1 R204.1 R205.1 R206.1 R207.1 R231.1 R232.1 R233.1 R234.1 R235.1 R236.1 R237.1 TP11.1 U50.2 U80.1 U201.3 U202.3 U203.3 U204.3 U205.3 U206.3 U207.3 U301.1(VS) U301.4(VS) U302.1(VS) U302.4(VS) U303.1(VS) U303.4(VS) U304.1(VS) U304.4(VS) U305.1(VS) U305.4(VS) U306.1(VS) U306.4(VS) U307.1(VS) U307.4(VS)
VCC2: C56.2 C60.2 C64.2 C72.2 C334.2 C335.2 C336.2 C337.2 C344.1 C345.1 C346.1 C347.1 C364.2 C365.2 C366.2 C367.2 C374.1 C375.1 C376.1 C377.1 D52.2 D56.2 R59.2 TP33.1 U304.13(VCC2) U305.13(VCC2) U306.13(VCC2) U307.13(VCC2)
VCC2_HU: C57.2 C61.2 C66.2 C74.2 C331.2 C341.1 C361.2 C371.1 D53.2 D57.2 R60.2 TP16.1 U301.13(VCC2)
VCC2_HV: C58.2 C62.2 C68.2 C76.2 C332.2 C342.1 C362.2 C372.1 D54.2 D58.2 R61.2 TP19.1 U302.13(VCC2)
VCC2_HW: C59.2 C63.2 C70.2 C78.2 C333.2 C343.1 C363.2 C373.1 D55.2 D59.2 R62.2 TP26.1 U303.13(VCC2)
VDD: C10.2 C50.2 C52.2 C53.2 C80.2 C82.2 C83.2 CN10.1 D13.2(CATHODE) D50.1(2) R50.2 R53.2 T50.1 U50.5 U80.3 U80.5
VEE: C56.1 C60.1 C65.1 C73.1 C324.1 C325.1 C326.1 C327.1 C334.1 C335.1 C336.1 C337.1 C354.1 C355.1 C356.1 C357.1 C364.1 C365.1 C366.1 C367.1 R59.1 R75.1 T50.5 TP35.1 U304.9(VEE) U304.12(VEE) U305.9(VEE) U305.12(VEE) U306.9(VEE) U306.12(VEE) U307.9(VEE) U307.12(VEE)
VEE_HU: C57.1 C61.1 C67.1 C75.1 C321.1 C331.1 C351.1 C361.1 R60.1 R76.1 T50.8 TP18.1 U301.9(VEE) U301.12(VEE)
VEE_HV: C58.1 C62.1 C69.1 C77.1 C322.1 C332.1 C352.1 C362.1 R61.1 R77.1 T50.11 TP21.1 U302.9(VEE) U302.12(VEE)
VEE_HW: C59.1 C63.1 C71.1 C79.1 C323.1 C333.1 C353.1 C363.1 R62.1 R78.1 T50.14 TP28.1 U303.9(VEE) U303.12(VEE)
ANODE_BR: C247.2 R247.1 R257.2 TP36.1 U307.6(ANODE) U307.7(ANODE)
ANODE_HU: C241.2 R241.1 R251.2 TP14.1 U301.6(ANODE) U301.7(ANODE)
ANODE_HV: C242.2 R242.1 R252.2 TP22.1 U302.6(ANODE) U302.7(ANODE)
ANODE_HW: C243.2 R243.1 R253.2 TP29.1 U303.6(ANODE) U303.7(ANODE)
ANODE_LU: C244.2 R244.1 R254.2 TP12.1 U304.6(ANODE) U304.7(ANODE)
ANODE_LV: C245.2 R245.1 R255.2 TP23.1 U305.6(ANODE) U305.7(ANODE)
ANODE_LW: C246.2 R246.1 R256.2 TP31.1 U306.6(ANODE) U306.7(ANODE)
CATHODE_BR: C247.1 Q207.3(D) R257.1 TP37.1 U307.5(CATHODE) U307.8(CATHODE)
CATHODE_HU: C241.1 Q201.3(D) R251.1 TP15.1 U301.5(CATHODE) U301.8(CATHODE)
CATHODE_HV: C242.1 Q202.3(D) R252.1 TP24.1 U302.5(CATHODE) U302.8(CATHODE)
CATHODE_HW: C243.1 Q203.3(D) R253.1 TP30.1 U303.5(CATHODE) U303.8(CATHODE)
CATHODE_LU: C244.1 Q204.3(D) R254.1 TP13.1 U304.5(CATHODE) U304.8(CATHODE)
CATHODE_LV: C245.1 Q205.3(D) R255.1 TP25.1 U305.5(CATHODE) U305.8(CATHODE)
CATHODE_LW: C246.1 Q206.3(D) R256.1 TP32.1 U306.5(CATHODE) U306.8(CATHODE)
EN: CN11.13 D12.1(CATHODE) R13.2 R221.2(1) R222.2(1) R223.2(1) R224.2(1) R225.2(1) R226.2(1) R227.2(1)
FAULT: C301.1 C302.1 C303.1 C304.1 C305.1 C306.1 C307.1 CN11.15 D11.1(CATHODE) R12.2 U301.3(FAULT) U302.3(FAULT) U303.3(FAULT) U304.3(FAULT) U305.3(FAULT) U306.3(FAULT) U307.3(FAULT)
IN_BR: CN11.17 D207.1(CATHODE) R207.2 R217.2(1)
IN_HU: CN11.1 D201.1(CATHODE) R201.2 R211.2(1)
IN_HV: CN11.3 D202.1(CATHODE) R202.2 R212.2(1)
IN_HW: CN11.5 D203.1(CATHODE) R203.2 R213.2(1)
IN_LU: CN11.7 D204.1(CATHODE) R204.2 R214.2(1)
IN_LV: CN11.9 D205.1(CATHODE) R205.2 R215.2(1)
IN_LW: CN11.11 D206.1(CATHODE) R206.2 R216.2(1)
SIG0011: Q201.1(G) R231.2 U201.4
SIG0012: C201.2 R211.1(2) U201.1
SIG0013: C211.2 R221.1(2) U201.2
SIG0014: CN11.21 CN12.2 CN12.4
SIG0015: CN11.23 CN11.25 D10.1(CATHODE) R10.2
SIG0016: CN11.19 CN12.1 CN12.3
SIG0021: C202.2 R212.1(2) U202.1
SIG0022: C212.2 R222.1(2) U202.2
SIG0023: Q202.1(G) R232.2 U202.4
SIG0031: C213.2 R223.1(2) U203.2
SIG0032: Q203.1(G) R233.2 U203.4
SIG0033: C203.2 R213.1(2) U203.1
SIG0041: C214.2 R224.1(2) U204.2
SIG0042: Q204.1(G) R234.2 U204.4
SIG0043: C204.2 R214.1(2) U204.1
SIG0045: C51.2 R50.1 R51.2 U50.6
SIG0051: C215.2 R225.1(2) U205.2
SIG0052: C205.2 R215.1(2) U205.1
SIG0053: Q205.1(G) R235.2 U205.4
SIG0061: Q206.1(G) R236.2 U206.4
SIG0062: C206.2 R216.1(2) U206.1
SIG0063: C216.2 R226.1(2) U206.2
SIG0071: C217.2 R227.1(2) U207.2
SIG0072: Q207.1(G) R237.2 U207.4
SIG0073: C207.2 R217.1(2) U207.1
SIG0082: C381.1 D301.1(CATHODE) D311.2(CATHODE) R311.2 R341.2 U301.14(DESAT)
SIG0083: D361.1(ANODE) R391.2 R401.2
SIG0084: D361.2(CATHODE) R321.1 R331.1 R361.2 R371.2
SIG0085: CN16.1 CN16.3 R361.1 R371.1 R391.1 R401.1 U301.10(VCLAMP)
SIG0086: R301.1 R311.1 R321.2 R331.2 U301.11(VOUT)
SIG0087: CN13.1 CN13.2 CN13.3 CN13.4 D371.2(ANODE) R381.1
SIG0088: D321.2 D371.1(CATHODE) R381.2
SIG0093: CN20.1 CN20.2 CN20.3 CN20.4 D372.2(ANODE) R382.1
SIG0094: R302.1 R312.1 R322.2 R332.2 U302.11(VOUT)
SIG0095: CN18.1 CN18.3 R362.1 R372.1 R392.1 R402.1 U302.10(VCLAMP)
SIG0096: D362.2(CATHODE) R322.1 R332.1 R362.2 R372.2
SIG0098: C382.1 D302.1(CATHODE) D312.2(CATHODE) R312.2 R342.2 U302.14(DESAT)
SIG0099: D362.1(ANODE) R392.2 R402.2
SIG0101: C383.1 D303.1(CATHODE) D313.2(CATHODE) R313.2 R343.2 U303.14(DESAT)
SIG0102: D363.1(ANODE) R393.2 R403.2
SIG0105: CN21.1 CN21.2 CN21.3 CN21.4 D373.2(ANODE) R383.1
SIG0108: CN24.1 CN24.3 R363.1 R373.1 R393.1 R403.1 U303.10(VCLAMP)
SIG0109: R303.1 R313.1 R323.2 R333.2 U303.11(VOUT)
SIG0111: D364.1(ANODE) R394.2 R404.2
SIG0112: R304.1 R314.1 R324.2 R334.2 U304.11(VOUT)
SIG0114: D324.2 D374.1(CATHODE) R384.2
SIG0115: C384.1 D304.1(CATHODE) D314.2(CATHODE) R314.2 R344.2 U304.14(DESAT)
SIG0117: D364.2(CATHODE) R324.1 R334.1 R364.2 R374.2
SIG0119: CN14.1 CN14.2 CN14.3 CN14.4 D374.2(ANODE) R384.1
SIG0123: CN19.1 CN19.3 R365.1 R375.1 R395.1 R405.1 U305.10(VCLAMP)
SIG0125: D365.1(ANODE) R395.2 R405.2
SIG0126: R305.1 R315.1 R325.2 R335.2 U305.11(VOUT)
SIG0127: D365.2(CATHODE) R325.1 R335.1 R365.2 R375.2
SIG0128: CN17.1 CN17.2 CN17.3 CN17.4 D375.2(ANODE) R385.1
SIG0129: C385.1 D305.1(CATHODE) D315.2(CATHODE) R315.2 R345.2 U305.14(DESAT)
SIG0132: D366.1(ANODE) R396.2 R406.2
SIG0135: D366.2(CATHODE) R326.1 R336.1 R366.2 R376.2
SIG0136: CN23.1 CN23.3 R366.1 R376.1 R396.1 R406.1 U306.10(VCLAMP)
SIG0138: C386.1 D306.1(CATHODE) D316.2(CATHODE) R316.2 R346.2 U306.14(DESAT)
SIG0139: CN22.1 CN22.2 CN22.3 CN22.4 D376.2(ANODE) R386.1
SIG0142: R307.1 R317.1 R327.2 R337.2 U307.11(VOUT)
SIG0145: D367.1(ANODE) R397.2 R407.2
SIG0146: CN26.1 CN26.3 R367.1 R377.1 R397.1 R407.1 U307.10(VCLAMP)
SIG0147: D367.2(CATHODE) R327.1 R337.1 R367.2 R377.2
SIG00813: U301.15(VLED)
SIG00913: U302.15(VLED)
SIG00914: D322.2 D372.1(CATHODE) R382.2
SIG01011: D363.2(CATHODE) R323.1 R333.1 R363.2 R373.2
SIG01013: U303.15(VLED)
SIG01014: D323.2 D373.1(CATHODE) R383.2
SIG01111: CN15.1 CN15.3 R364.1 R374.1 R394.1 R404.1 U304.10(VCLAMP)
SIG01113: U304.15(VLED)
SIG01211: D325.2 D375.1(CATHODE) R385.2
SIG01213: U305.15(VLED)
SIG01312: R306.1 R316.1 R326.2 R336.2 U306.11(VOUT)
SIG01313: U306.15(VLED)
SIG01314: D326.2 D376.1(CATHODE) R386.2
SIG01411: CN25.1 CN25.2 CN25.3 CN25.4 D377.2(ANODE) R387.1
SIG01412: C387.1 D307.1(CATHODE) D317.2(CATHODE) R317.2 R347.2 U307.14(DESAT)
SIG01413: U307.15(VLED)
SIG01414: D327.2 D377.1(CATHODE) R387.2
SIG01549: R55.2 U50.3
SIG01550: C54.2 R56.2 U50.1
SIG01551: Q50.4 R56.1 R57.2
SIG01552: Q50.3 R55.1
SIG01553: R52.1 R54.2
SIG01554: R52.2 U50.4
SIG01555: D50.2(1) D51.2
SIG01556: C55.1 D51.1 Q50.1 Q50.2 Q50.5 Q50.6 R54.1 T50.2
SIG01557: D52.1 T50.6
SIG01558: D53.1 T50.7
SIG01559: D54.1 T50.10
SIG01560: D55.1 T50.13
SIG01561: C55.2 R53.1
SIG01616: R82.1 R83.2
SIG01617: R80.2 R82.2 U80.4
SIG01618: R80.1 R81.2
SIG01619: C84.2 C85.2 L80.2 R11.1 R81.1 TP10.1
SIG01620: C81.1 L80.1 TP80.1 U80.2
SIG01621: C81.2 U80.6
VE: C64.1 C65.2 C72.1 C73.2 C324.2 C325.2 C326.2 C327.2 C344.2 C345.2 C346.2 C347.2 C354.2 C355.2 C356.2 C357.2 C374.2 C375.2 C376.2 C377.2 C384.2 C385.2 C386.2 C387.2 CN15.2 CN15.4 CN19.2 CN19.4 CN23.2 CN23.4 CN26.2 CN26.4 D56.1 D304.2(ANODE) D305.2(ANODE) D306.2(ANODE) D307.2(ANODE) D314.1(ANODE) D315.1(ANODE) D316.1(ANODE) D317.1(ANODE) R75.2 R304.2 R305.2 R306.2 R307.2 TP34.1 U304.16(VE) U305.16(VE) U306.16(VE) U307.16(VE)
VE_HU: C66.1 C67.2 C74.1 C75.2 C321.2 C341.2 C351.2 C371.2 C381.2 CN16.2 CN16.4 D57.1 D301.2(ANODE) D311.1(ANODE) R76.2 R301.2 TP17.1 U301.16(VE)
VE_HV: C68.1 C69.2 C76.1 C77.2 C322.2 C342.2 C352.2 C372.2 C382.2 CN18.2 CN18.4 D58.1 D302.2(ANODE) D312.1(ANODE) R77.2 R302.2 TP20.1 U302.16(VE)
VE_HW: C70.1 C71.2 C78.1 C79.2 C323.2 C343.2 C353.2 C373.2 C383.2 CN24.2 CN24.4 D59.1 D303.2(ANODE) D313.1(ANODE) R78.2 R303.2 TP27.1 U303.16(VE)
N05053: D351.1 R351.1
N05054: D341.1 D351.2
N05055: D331.1 D341.2
N05056: R341.1 R351.2
N05057: D321.1 D331.2
N06119: R342.1 R352.2
N06120: D352.1 R352.1
N06121: D332.1 D342.2
N06122: D342.1 D352.2
N06123: D322.1 D332.2
N07185: D333.1 D343.2
N07186: D353.1 R353.1
N07187: R343.1 R353.2
N07188: D323.1 D333.2
N07189: D343.1 D353.2
N08251: R344.1 R354.2
N08252: D354.1 R354.1
N08253: D344.1 D354.2
N08254: D334.1 D344.2
N08255: D324.1 D334.2
N09317: D325.1 D335.2
N09318: D355.1 R355.1
N09319: D335.1 D345.2
N09320: D345.1 D355.2
N09321: R345.1 R355.2
N10383: D336.1 D346.2
N10384: D326.1 D336.2
N10385: R346.1 R356.2
N10386: D346.1 D356.2
N10387: D356.1 R356.1
N11449: D337.1 D347.2
N11450: D347.1 D357.2
N11451: D327.1 D337.2
N11452: D357.1 R357.1
N11453: R347.1 R357.2
N13384: R57.1 R58.2

Not connected (* = marked no-connect by the designer): CN10 M1(empty-1) M2(empty-2); CN11 M1 M2
